VERSION 5.8 ;
BUSBITCHARS "[]" ;
DIVIDERCHAR "/" ;
UNITS
    DATABASE MICRONS 1000 ;
END UNITS

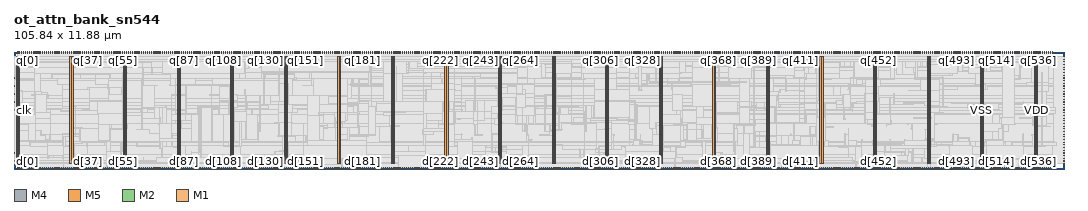
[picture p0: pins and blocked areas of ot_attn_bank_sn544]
MACRO ot_attn_bank_sn544
  FOREIGN ot_attn_bank_sn544 0 0 ;
  CLASS BLOCK ;
  SIZE 105.84 BY 11.88 ;
  PIN clk
    DIRECTION INPUT ;
    USE SIGNAL ;
    PORT
      LAYER M4 ;
        RECT  0 5.928 0.192 5.952 ;
    END
  END clk
  PIN d[0]
    DIRECTION INPUT ;
    USE SIGNAL ;
    PORT
      LAYER M5 ;
        RECT  0.384 0 0.408 0.192 ;
    END
  END d[0]
  PIN d[100]
    DIRECTION INPUT ;
    USE SIGNAL ;
    PORT
      LAYER M5 ;
        RECT  19.584 0 19.608 0.192 ;
    END
  END d[100]
  PIN d[101]
    DIRECTION INPUT ;
    USE SIGNAL ;
    PORT
      LAYER M5 ;
        RECT  19.776 0 19.8 0.192 ;
    END
  END d[101]
  PIN d[102]
    DIRECTION INPUT ;
    USE SIGNAL ;
    PORT
      LAYER M5 ;
        RECT  19.968 0 19.992 0.192 ;
    END
  END d[102]
  PIN d[103]
    DIRECTION INPUT ;
    USE SIGNAL ;
    PORT
      LAYER M5 ;
        RECT  20.16 0 20.184 0.192 ;
    END
  END d[103]
  PIN d[104]
    DIRECTION INPUT ;
    USE SIGNAL ;
    PORT
      LAYER M5 ;
        RECT  20.352 0 20.376 0.192 ;
    END
  END d[104]
  PIN d[105]
    DIRECTION INPUT ;
    USE SIGNAL ;
    PORT
      LAYER M5 ;
        RECT  20.544 0 20.568 0.192 ;
    END
  END d[105]
  PIN d[106]
    DIRECTION INPUT ;
    USE SIGNAL ;
    PORT
      LAYER M5 ;
        RECT  20.736 0 20.76 0.192 ;
    END
  END d[106]
  PIN d[107]
    DIRECTION INPUT ;
    USE SIGNAL ;
    PORT
      LAYER M5 ;
        RECT  20.928 0 20.952 0.192 ;
    END
  END d[107]
  PIN d[108]
    DIRECTION INPUT ;
    USE SIGNAL ;
    PORT
      LAYER M5 ;
        RECT  21.12 0 21.144 0.192 ;
    END
  END d[108]
  PIN d[109]
    DIRECTION INPUT ;
    USE SIGNAL ;
    PORT
      LAYER M5 ;
        RECT  21.312 0 21.336 0.192 ;
    END
  END d[109]
  PIN d[10]
    DIRECTION INPUT ;
    USE SIGNAL ;
    PORT
      LAYER M5 ;
        RECT  2.304 0 2.328 0.192 ;
    END
  END d[10]
  PIN d[110]
    DIRECTION INPUT ;
    USE SIGNAL ;
    PORT
      LAYER M5 ;
        RECT  21.504 0 21.528 0.192 ;
    END
  END d[110]
  PIN d[111]
    DIRECTION INPUT ;
    USE SIGNAL ;
    PORT
      LAYER M5 ;
        RECT  21.696 0 21.72 0.192 ;
    END
  END d[111]
  PIN d[112]
    DIRECTION INPUT ;
    USE SIGNAL ;
    PORT
      LAYER M5 ;
        RECT  21.888 0 21.912 0.192 ;
    END
  END d[112]
  PIN d[113]
    DIRECTION INPUT ;
    USE SIGNAL ;
    PORT
      LAYER M5 ;
        RECT  22.08 0 22.104 0.192 ;
    END
  END d[113]
  PIN d[114]
    DIRECTION INPUT ;
    USE SIGNAL ;
    PORT
      LAYER M5 ;
        RECT  22.272 0 22.296 0.192 ;
    END
  END d[114]
  PIN d[115]
    DIRECTION INPUT ;
    USE SIGNAL ;
    PORT
      LAYER M5 ;
        RECT  22.464 0 22.488 0.192 ;
    END
  END d[115]
  PIN d[116]
    DIRECTION INPUT ;
    USE SIGNAL ;
    PORT
      LAYER M5 ;
        RECT  22.656 0 22.68 0.192 ;
    END
  END d[116]
  PIN d[117]
    DIRECTION INPUT ;
    USE SIGNAL ;
    PORT
      LAYER M5 ;
        RECT  22.848 0 22.872 0.192 ;
    END
  END d[117]
  PIN d[118]
    DIRECTION INPUT ;
    USE SIGNAL ;
    PORT
      LAYER M5 ;
        RECT  23.04 0 23.064 0.192 ;
    END
  END d[118]
  PIN d[119]
    DIRECTION INPUT ;
    USE SIGNAL ;
    PORT
      LAYER M5 ;
        RECT  23.232 0 23.256 0.192 ;
    END
  END d[119]
  PIN d[11]
    DIRECTION INPUT ;
    USE SIGNAL ;
    PORT
      LAYER M5 ;
        RECT  2.496 0 2.52 0.192 ;
    END
  END d[11]
  PIN d[120]
    DIRECTION INPUT ;
    USE SIGNAL ;
    PORT
      LAYER M5 ;
        RECT  23.424 0 23.448 0.192 ;
    END
  END d[120]
  PIN d[121]
    DIRECTION INPUT ;
    USE SIGNAL ;
    PORT
      LAYER M5 ;
        RECT  23.616 0 23.64 0.192 ;
    END
  END d[121]
  PIN d[122]
    DIRECTION INPUT ;
    USE SIGNAL ;
    PORT
      LAYER M5 ;
        RECT  23.808 0 23.832 0.192 ;
    END
  END d[122]
  PIN d[123]
    DIRECTION INPUT ;
    USE SIGNAL ;
    PORT
      LAYER M5 ;
        RECT  24 0 24.024 0.192 ;
    END
  END d[123]
  PIN d[124]
    DIRECTION INPUT ;
    USE SIGNAL ;
    PORT
      LAYER M5 ;
        RECT  24.192 0 24.216 0.192 ;
    END
  END d[124]
  PIN d[125]
    DIRECTION INPUT ;
    USE SIGNAL ;
    PORT
      LAYER M5 ;
        RECT  24.384 0 24.408 0.192 ;
    END
  END d[125]
  PIN d[126]
    DIRECTION INPUT ;
    USE SIGNAL ;
    PORT
      LAYER M5 ;
        RECT  24.576 0 24.6 0.192 ;
    END
  END d[126]
  PIN d[127]
    DIRECTION INPUT ;
    USE SIGNAL ;
    PORT
      LAYER M5 ;
        RECT  24.768 0 24.792 0.192 ;
    END
  END d[127]
  PIN d[128]
    DIRECTION INPUT ;
    USE SIGNAL ;
    PORT
      LAYER M5 ;
        RECT  24.96 0 24.984 0.192 ;
    END
  END d[128]
  PIN d[129]
    DIRECTION INPUT ;
    USE SIGNAL ;
    PORT
      LAYER M5 ;
        RECT  25.152 0 25.176 0.192 ;
    END
  END d[129]
  PIN d[12]
    DIRECTION INPUT ;
    USE SIGNAL ;
    PORT
      LAYER M5 ;
        RECT  2.688 0 2.712 0.192 ;
    END
  END d[12]
  PIN d[130]
    DIRECTION INPUT ;
    USE SIGNAL ;
    PORT
      LAYER M5 ;
        RECT  25.344 0 25.368 0.192 ;
    END
  END d[130]
  PIN d[131]
    DIRECTION INPUT ;
    USE SIGNAL ;
    PORT
      LAYER M5 ;
        RECT  25.536 0 25.56 0.192 ;
    END
  END d[131]
  PIN d[132]
    DIRECTION INPUT ;
    USE SIGNAL ;
    PORT
      LAYER M5 ;
        RECT  25.728 0 25.752 0.192 ;
    END
  END d[132]
  PIN d[133]
    DIRECTION INPUT ;
    USE SIGNAL ;
    PORT
      LAYER M5 ;
        RECT  25.92 0 25.944 0.192 ;
    END
  END d[133]
  PIN d[134]
    DIRECTION INPUT ;
    USE SIGNAL ;
    PORT
      LAYER M5 ;
        RECT  26.112 0 26.136 0.192 ;
    END
  END d[134]
  PIN d[135]
    DIRECTION INPUT ;
    USE SIGNAL ;
    PORT
      LAYER M5 ;
        RECT  26.304 0 26.328 0.192 ;
    END
  END d[135]
  PIN d[136]
    DIRECTION INPUT ;
    USE SIGNAL ;
    PORT
      LAYER M5 ;
        RECT  26.496 0 26.52 0.192 ;
    END
  END d[136]
  PIN d[137]
    DIRECTION INPUT ;
    USE SIGNAL ;
    PORT
      LAYER M5 ;
        RECT  26.688 0 26.712 0.192 ;
    END
  END d[137]
  PIN d[138]
    DIRECTION INPUT ;
    USE SIGNAL ;
    PORT
      LAYER M5 ;
        RECT  26.88 0 26.904 0.192 ;
    END
  END d[138]
  PIN d[139]
    DIRECTION INPUT ;
    USE SIGNAL ;
    PORT
      LAYER M5 ;
        RECT  27.072 0 27.096 0.192 ;
    END
  END d[139]
  PIN d[13]
    DIRECTION INPUT ;
    USE SIGNAL ;
    PORT
      LAYER M5 ;
        RECT  2.88 0 2.904 0.192 ;
    END
  END d[13]
  PIN d[140]
    DIRECTION INPUT ;
    USE SIGNAL ;
    PORT
      LAYER M5 ;
        RECT  27.264 0 27.288 0.192 ;
    END
  END d[140]
  PIN d[141]
    DIRECTION INPUT ;
    USE SIGNAL ;
    PORT
      LAYER M5 ;
        RECT  27.456 0 27.48 0.192 ;
    END
  END d[141]
  PIN d[142]
    DIRECTION INPUT ;
    USE SIGNAL ;
    PORT
      LAYER M5 ;
        RECT  27.648 0 27.672 0.192 ;
    END
  END d[142]
  PIN d[143]
    DIRECTION INPUT ;
    USE SIGNAL ;
    PORT
      LAYER M5 ;
        RECT  27.84 0 27.864 0.192 ;
    END
  END d[143]
  PIN d[144]
    DIRECTION INPUT ;
    USE SIGNAL ;
    PORT
      LAYER M5 ;
        RECT  28.032 0 28.056 0.192 ;
    END
  END d[144]
  PIN d[145]
    DIRECTION INPUT ;
    USE SIGNAL ;
    PORT
      LAYER M5 ;
        RECT  28.224 0 28.248 0.192 ;
    END
  END d[145]
  PIN d[146]
    DIRECTION INPUT ;
    USE SIGNAL ;
    PORT
      LAYER M5 ;
        RECT  28.416 0 28.44 0.192 ;
    END
  END d[146]
  PIN d[147]
    DIRECTION INPUT ;
    USE SIGNAL ;
    PORT
      LAYER M5 ;
        RECT  28.608 0 28.632 0.192 ;
    END
  END d[147]
  PIN d[148]
    DIRECTION INPUT ;
    USE SIGNAL ;
    PORT
      LAYER M5 ;
        RECT  28.8 0 28.824 0.192 ;
    END
  END d[148]
  PIN d[149]
    DIRECTION INPUT ;
    USE SIGNAL ;
    PORT
      LAYER M5 ;
        RECT  28.992 0 29.016 0.192 ;
    END
  END d[149]
  PIN d[14]
    DIRECTION INPUT ;
    USE SIGNAL ;
    PORT
      LAYER M5 ;
        RECT  3.072 0 3.096 0.192 ;
    END
  END d[14]
  PIN d[150]
    DIRECTION INPUT ;
    USE SIGNAL ;
    PORT
      LAYER M5 ;
        RECT  29.184 0 29.208 0.192 ;
    END
  END d[150]
  PIN d[151]
    DIRECTION INPUT ;
    USE SIGNAL ;
    PORT
      LAYER M5 ;
        RECT  29.376 0 29.4 0.192 ;
    END
  END d[151]
  PIN d[152]
    DIRECTION INPUT ;
    USE SIGNAL ;
    PORT
      LAYER M5 ;
        RECT  29.568 0 29.592 0.192 ;
    END
  END d[152]
  PIN d[153]
    DIRECTION INPUT ;
    USE SIGNAL ;
    PORT
      LAYER M5 ;
        RECT  29.76 0 29.784 0.192 ;
    END
  END d[153]
  PIN d[154]
    DIRECTION INPUT ;
    USE SIGNAL ;
    PORT
      LAYER M5 ;
        RECT  29.952 0 29.976 0.192 ;
    END
  END d[154]
  PIN d[155]
    DIRECTION INPUT ;
    USE SIGNAL ;
    PORT
      LAYER M5 ;
        RECT  30.144 0 30.168 0.192 ;
    END
  END d[155]
  PIN d[156]
    DIRECTION INPUT ;
    USE SIGNAL ;
    PORT
      LAYER M5 ;
        RECT  30.336 0 30.36 0.192 ;
    END
  END d[156]
  PIN d[157]
    DIRECTION INPUT ;
    USE SIGNAL ;
    PORT
      LAYER M5 ;
        RECT  30.528 0 30.552 0.192 ;
    END
  END d[157]
  PIN d[158]
    DIRECTION INPUT ;
    USE SIGNAL ;
    PORT
      LAYER M5 ;
        RECT  30.72 0 30.744 0.192 ;
    END
  END d[158]
  PIN d[159]
    DIRECTION INPUT ;
    USE SIGNAL ;
    PORT
      LAYER M5 ;
        RECT  30.912 0 30.936 0.192 ;
    END
  END d[159]
  PIN d[15]
    DIRECTION INPUT ;
    USE SIGNAL ;
    PORT
      LAYER M5 ;
        RECT  3.264 0 3.288 0.192 ;
    END
  END d[15]
  PIN d[160]
    DIRECTION INPUT ;
    USE SIGNAL ;
    PORT
      LAYER M5 ;
        RECT  31.104 0 31.128 0.192 ;
    END
  END d[160]
  PIN d[161]
    DIRECTION INPUT ;
    USE SIGNAL ;
    PORT
      LAYER M5 ;
        RECT  31.296 0 31.32 0.192 ;
    END
  END d[161]
  PIN d[162]
    DIRECTION INPUT ;
    USE SIGNAL ;
    PORT
      LAYER M5 ;
        RECT  31.488 0 31.512 0.192 ;
    END
  END d[162]
  PIN d[163]
    DIRECTION INPUT ;
    USE SIGNAL ;
    PORT
      LAYER M5 ;
        RECT  31.68 0 31.704 0.192 ;
    END
  END d[163]
  PIN d[164]
    DIRECTION INPUT ;
    USE SIGNAL ;
    PORT
      LAYER M5 ;
        RECT  31.872 0 31.896 0.192 ;
    END
  END d[164]
  PIN d[165]
    DIRECTION INPUT ;
    USE SIGNAL ;
    PORT
      LAYER M5 ;
        RECT  32.064 0 32.088 0.192 ;
    END
  END d[165]
  PIN d[166]
    DIRECTION INPUT ;
    USE SIGNAL ;
    PORT
      LAYER M5 ;
        RECT  32.256 0 32.28 0.192 ;
    END
  END d[166]
  PIN d[167]
    DIRECTION INPUT ;
    USE SIGNAL ;
    PORT
      LAYER M5 ;
        RECT  32.448 0 32.472 0.192 ;
    END
  END d[167]
  PIN d[168]
    DIRECTION INPUT ;
    USE SIGNAL ;
    PORT
      LAYER M5 ;
        RECT  32.64 0 32.664 0.192 ;
    END
  END d[168]
  PIN d[169]
    DIRECTION INPUT ;
    USE SIGNAL ;
    PORT
      LAYER M5 ;
        RECT  32.832 0 32.856 0.192 ;
    END
  END d[169]
  PIN d[16]
    DIRECTION INPUT ;
    USE SIGNAL ;
    PORT
      LAYER M5 ;
        RECT  3.456 0 3.48 0.192 ;
    END
  END d[16]
  PIN d[170]
    DIRECTION INPUT ;
    USE SIGNAL ;
    PORT
      LAYER M5 ;
        RECT  33.024 0 33.048 0.192 ;
    END
  END d[170]
  PIN d[171]
    DIRECTION INPUT ;
    USE SIGNAL ;
    PORT
      LAYER M5 ;
        RECT  33.216 0 33.24 0.192 ;
    END
  END d[171]
  PIN d[172]
    DIRECTION INPUT ;
    USE SIGNAL ;
    PORT
      LAYER M5 ;
        RECT  33.408 0 33.432 0.192 ;
    END
  END d[172]
  PIN d[173]
    DIRECTION INPUT ;
    USE SIGNAL ;
    PORT
      LAYER M5 ;
        RECT  33.6 0 33.624 0.192 ;
    END
  END d[173]
  PIN d[174]
    DIRECTION INPUT ;
    USE SIGNAL ;
    PORT
      LAYER M5 ;
        RECT  33.792 0 33.816 0.192 ;
    END
  END d[174]
  PIN d[175]
    DIRECTION INPUT ;
    USE SIGNAL ;
    PORT
      LAYER M5 ;
        RECT  33.984 0 34.008 0.192 ;
    END
  END d[175]
  PIN d[176]
    DIRECTION INPUT ;
    USE SIGNAL ;
    PORT
      LAYER M5 ;
        RECT  34.176 0 34.2 0.192 ;
    END
  END d[176]
  PIN d[177]
    DIRECTION INPUT ;
    USE SIGNAL ;
    PORT
      LAYER M5 ;
        RECT  34.368 0 34.392 0.192 ;
    END
  END d[177]
  PIN d[178]
    DIRECTION INPUT ;
    USE SIGNAL ;
    PORT
      LAYER M5 ;
        RECT  34.56 0 34.584 0.192 ;
    END
  END d[178]
  PIN d[179]
    DIRECTION INPUT ;
    USE SIGNAL ;
    PORT
      LAYER M5 ;
        RECT  34.752 0 34.776 0.192 ;
    END
  END d[179]
  PIN d[17]
    DIRECTION INPUT ;
    USE SIGNAL ;
    PORT
      LAYER M5 ;
        RECT  3.648 0 3.672 0.192 ;
    END
  END d[17]
  PIN d[180]
    DIRECTION INPUT ;
    USE SIGNAL ;
    PORT
      LAYER M5 ;
        RECT  34.944 0 34.968 0.192 ;
    END
  END d[180]
  PIN d[181]
    DIRECTION INPUT ;
    USE SIGNAL ;
    PORT
      LAYER M5 ;
        RECT  35.136 0 35.16 0.192 ;
    END
  END d[181]
  PIN d[182]
    DIRECTION INPUT ;
    USE SIGNAL ;
    PORT
      LAYER M5 ;
        RECT  35.328 0 35.352 0.192 ;
    END
  END d[182]
  PIN d[183]
    DIRECTION INPUT ;
    USE SIGNAL ;
    PORT
      LAYER M5 ;
        RECT  35.52 0 35.544 0.192 ;
    END
  END d[183]
  PIN d[184]
    DIRECTION INPUT ;
    USE SIGNAL ;
    PORT
      LAYER M5 ;
        RECT  35.712 0 35.736 0.192 ;
    END
  END d[184]
  PIN d[185]
    DIRECTION INPUT ;
    USE SIGNAL ;
    PORT
      LAYER M5 ;
        RECT  35.904 0 35.928 0.192 ;
    END
  END d[185]
  PIN d[186]
    DIRECTION INPUT ;
    USE SIGNAL ;
    PORT
      LAYER M5 ;
        RECT  36.096 0 36.12 0.192 ;
    END
  END d[186]
  PIN d[187]
    DIRECTION INPUT ;
    USE SIGNAL ;
    PORT
      LAYER M5 ;
        RECT  36.288 0 36.312 0.192 ;
    END
  END d[187]
  PIN d[188]
    DIRECTION INPUT ;
    USE SIGNAL ;
    PORT
      LAYER M5 ;
        RECT  36.48 0 36.504 0.192 ;
    END
  END d[188]
  PIN d[189]
    DIRECTION INPUT ;
    USE SIGNAL ;
    PORT
      LAYER M5 ;
        RECT  36.672 0 36.696 0.192 ;
    END
  END d[189]
  PIN d[18]
    DIRECTION INPUT ;
    USE SIGNAL ;
    PORT
      LAYER M5 ;
        RECT  3.84 0 3.864 0.192 ;
    END
  END d[18]
  PIN d[190]
    DIRECTION INPUT ;
    USE SIGNAL ;
    PORT
      LAYER M5 ;
        RECT  36.864 0 36.888 0.192 ;
    END
  END d[190]
  PIN d[191]
    DIRECTION INPUT ;
    USE SIGNAL ;
    PORT
      LAYER M5 ;
        RECT  37.056 0 37.08 0.192 ;
    END
  END d[191]
  PIN d[192]
    DIRECTION INPUT ;
    USE SIGNAL ;
    PORT
      LAYER M5 ;
        RECT  37.248 0 37.272 0.192 ;
    END
  END d[192]
  PIN d[193]
    DIRECTION INPUT ;
    USE SIGNAL ;
    PORT
      LAYER M5 ;
        RECT  37.44 0 37.464 0.192 ;
    END
  END d[193]
  PIN d[194]
    DIRECTION INPUT ;
    USE SIGNAL ;
    PORT
      LAYER M5 ;
        RECT  37.632 0 37.656 0.192 ;
    END
  END d[194]
  PIN d[195]
    DIRECTION INPUT ;
    USE SIGNAL ;
    PORT
      LAYER M5 ;
        RECT  37.824 0 37.848 0.192 ;
    END
  END d[195]
  PIN d[196]
    DIRECTION INPUT ;
    USE SIGNAL ;
    PORT
      LAYER M5 ;
        RECT  38.016 0 38.04 0.192 ;
    END
  END d[196]
  PIN d[197]
    DIRECTION INPUT ;
    USE SIGNAL ;
    PORT
      LAYER M5 ;
        RECT  38.208 0 38.232 0.192 ;
    END
  END d[197]
  PIN d[198]
    DIRECTION INPUT ;
    USE SIGNAL ;
    PORT
      LAYER M5 ;
        RECT  38.4 0 38.424 0.192 ;
    END
  END d[198]
  PIN d[199]
    DIRECTION INPUT ;
    USE SIGNAL ;
    PORT
      LAYER M5 ;
        RECT  38.592 0 38.616 0.192 ;
    END
  END d[199]
  PIN d[19]
    DIRECTION INPUT ;
    USE SIGNAL ;
    PORT
      LAYER M5 ;
        RECT  4.032 0 4.056 0.192 ;
    END
  END d[19]
  PIN d[1]
    DIRECTION INPUT ;
    USE SIGNAL ;
    PORT
      LAYER M5 ;
        RECT  0.576 0 0.6 0.192 ;
    END
  END d[1]
  PIN d[200]
    DIRECTION INPUT ;
    USE SIGNAL ;
    PORT
      LAYER M5 ;
        RECT  38.784 0 38.808 0.192 ;
    END
  END d[200]
  PIN d[201]
    DIRECTION INPUT ;
    USE SIGNAL ;
    PORT
      LAYER M5 ;
        RECT  38.976 0 39 0.192 ;
    END
  END d[201]
  PIN d[202]
    DIRECTION INPUT ;
    USE SIGNAL ;
    PORT
      LAYER M5 ;
        RECT  39.168 0 39.192 0.192 ;
    END
  END d[202]
  PIN d[203]
    DIRECTION INPUT ;
    USE SIGNAL ;
    PORT
      LAYER M5 ;
        RECT  39.36 0 39.384 0.192 ;
    END
  END d[203]
  PIN d[204]
    DIRECTION INPUT ;
    USE SIGNAL ;
    PORT
      LAYER M5 ;
        RECT  39.552 0 39.576 0.192 ;
    END
  END d[204]
  PIN d[205]
    DIRECTION INPUT ;
    USE SIGNAL ;
    PORT
      LAYER M5 ;
        RECT  39.744 0 39.768 0.192 ;
    END
  END d[205]
  PIN d[206]
    DIRECTION INPUT ;
    USE SIGNAL ;
    PORT
      LAYER M5 ;
        RECT  39.936 0 39.96 0.192 ;
    END
  END d[206]
  PIN d[207]
    DIRECTION INPUT ;
    USE SIGNAL ;
    PORT
      LAYER M5 ;
        RECT  40.128 0 40.152 0.192 ;
    END
  END d[207]
  PIN d[208]
    DIRECTION INPUT ;
    USE SIGNAL ;
    PORT
      LAYER M5 ;
        RECT  40.32 0 40.344 0.192 ;
    END
  END d[208]
  PIN d[209]
    DIRECTION INPUT ;
    USE SIGNAL ;
    PORT
      LAYER M5 ;
        RECT  40.512 0 40.536 0.192 ;
    END
  END d[209]
  PIN d[20]
    DIRECTION INPUT ;
    USE SIGNAL ;
    PORT
      LAYER M5 ;
        RECT  4.224 0 4.248 0.192 ;
    END
  END d[20]
  PIN d[210]
    DIRECTION INPUT ;
    USE SIGNAL ;
    PORT
      LAYER M5 ;
        RECT  40.704 0 40.728 0.192 ;
    END
  END d[210]
  PIN d[211]
    DIRECTION INPUT ;
    USE SIGNAL ;
    PORT
      LAYER M5 ;
        RECT  40.896 0 40.92 0.192 ;
    END
  END d[211]
  PIN d[212]
    DIRECTION INPUT ;
    USE SIGNAL ;
    PORT
      LAYER M5 ;
        RECT  41.088 0 41.112 0.192 ;
    END
  END d[212]
  PIN d[213]
    DIRECTION INPUT ;
    USE SIGNAL ;
    PORT
      LAYER M5 ;
        RECT  41.28 0 41.304 0.192 ;
    END
  END d[213]
  PIN d[214]
    DIRECTION INPUT ;
    USE SIGNAL ;
    PORT
      LAYER M5 ;
        RECT  41.472 0 41.496 0.192 ;
    END
  END d[214]
  PIN d[215]
    DIRECTION INPUT ;
    USE SIGNAL ;
    PORT
      LAYER M5 ;
        RECT  41.664 0 41.688 0.192 ;
    END
  END d[215]
  PIN d[216]
    DIRECTION INPUT ;
    USE SIGNAL ;
    PORT
      LAYER M5 ;
        RECT  41.856 0 41.88 0.192 ;
    END
  END d[216]
  PIN d[217]
    DIRECTION INPUT ;
    USE SIGNAL ;
    PORT
      LAYER M5 ;
        RECT  42.048 0 42.072 0.192 ;
    END
  END d[217]
  PIN d[218]
    DIRECTION INPUT ;
    USE SIGNAL ;
    PORT
      LAYER M5 ;
        RECT  42.24 0 42.264 0.192 ;
    END
  END d[218]
  PIN d[219]
    DIRECTION INPUT ;
    USE SIGNAL ;
    PORT
      LAYER M5 ;
        RECT  42.432 0 42.456 0.192 ;
    END
  END d[219]
  PIN d[21]
    DIRECTION INPUT ;
    USE SIGNAL ;
    PORT
      LAYER M5 ;
        RECT  4.416 0 4.44 0.192 ;
    END
  END d[21]
  PIN d[220]
    DIRECTION INPUT ;
    USE SIGNAL ;
    PORT
      LAYER M5 ;
        RECT  42.624 0 42.648 0.192 ;
    END
  END d[220]
  PIN d[221]
    DIRECTION INPUT ;
    USE SIGNAL ;
    PORT
      LAYER M5 ;
        RECT  42.816 0 42.84 0.192 ;
    END
  END d[221]
  PIN d[222]
    DIRECTION INPUT ;
    USE SIGNAL ;
    PORT
      LAYER M5 ;
        RECT  43.008 0 43.032 0.192 ;
    END
  END d[222]
  PIN d[223]
    DIRECTION INPUT ;
    USE SIGNAL ;
    PORT
      LAYER M5 ;
        RECT  43.2 0 43.224 0.192 ;
    END
  END d[223]
  PIN d[224]
    DIRECTION INPUT ;
    USE SIGNAL ;
    PORT
      LAYER M5 ;
        RECT  43.392 0 43.416 0.192 ;
    END
  END d[224]
  PIN d[225]
    DIRECTION INPUT ;
    USE SIGNAL ;
    PORT
      LAYER M5 ;
        RECT  43.584 0 43.608 0.192 ;
    END
  END d[225]
  PIN d[226]
    DIRECTION INPUT ;
    USE SIGNAL ;
    PORT
      LAYER M5 ;
        RECT  43.776 0 43.8 0.192 ;
    END
  END d[226]
  PIN d[227]
    DIRECTION INPUT ;
    USE SIGNAL ;
    PORT
      LAYER M5 ;
        RECT  43.968 0 43.992 0.192 ;
    END
  END d[227]
  PIN d[228]
    DIRECTION INPUT ;
    USE SIGNAL ;
    PORT
      LAYER M5 ;
        RECT  44.16 0 44.184 0.192 ;
    END
  END d[228]
  PIN d[229]
    DIRECTION INPUT ;
    USE SIGNAL ;
    PORT
      LAYER M5 ;
        RECT  44.352 0 44.376 0.192 ;
    END
  END d[229]
  PIN d[22]
    DIRECTION INPUT ;
    USE SIGNAL ;
    PORT
      LAYER M5 ;
        RECT  4.608 0 4.632 0.192 ;
    END
  END d[22]
  PIN d[230]
    DIRECTION INPUT ;
    USE SIGNAL ;
    PORT
      LAYER M5 ;
        RECT  44.544 0 44.568 0.192 ;
    END
  END d[230]
  PIN d[231]
    DIRECTION INPUT ;
    USE SIGNAL ;
    PORT
      LAYER M5 ;
        RECT  44.736 0 44.76 0.192 ;
    END
  END d[231]
  PIN d[232]
    DIRECTION INPUT ;
    USE SIGNAL ;
    PORT
      LAYER M5 ;
        RECT  44.928 0 44.952 0.192 ;
    END
  END d[232]
  PIN d[233]
    DIRECTION INPUT ;
    USE SIGNAL ;
    PORT
      LAYER M5 ;
        RECT  45.12 0 45.144 0.192 ;
    END
  END d[233]
  PIN d[234]
    DIRECTION INPUT ;
    USE SIGNAL ;
    PORT
      LAYER M5 ;
        RECT  45.312 0 45.336 0.192 ;
    END
  END d[234]
  PIN d[235]
    DIRECTION INPUT ;
    USE SIGNAL ;
    PORT
      LAYER M5 ;
        RECT  45.504 0 45.528 0.192 ;
    END
  END d[235]
  PIN d[236]
    DIRECTION INPUT ;
    USE SIGNAL ;
    PORT
      LAYER M5 ;
        RECT  45.696 0 45.72 0.192 ;
    END
  END d[236]
  PIN d[237]
    DIRECTION INPUT ;
    USE SIGNAL ;
    PORT
      LAYER M5 ;
        RECT  45.888 0 45.912 0.192 ;
    END
  END d[237]
  PIN d[238]
    DIRECTION INPUT ;
    USE SIGNAL ;
    PORT
      LAYER M5 ;
        RECT  46.08 0 46.104 0.192 ;
    END
  END d[238]
  PIN d[239]
    DIRECTION INPUT ;
    USE SIGNAL ;
    PORT
      LAYER M5 ;
        RECT  46.272 0 46.296 0.192 ;
    END
  END d[239]
  PIN d[23]
    DIRECTION INPUT ;
    USE SIGNAL ;
    PORT
      LAYER M5 ;
        RECT  4.8 0 4.824 0.192 ;
    END
  END d[23]
  PIN d[240]
    DIRECTION INPUT ;
    USE SIGNAL ;
    PORT
      LAYER M5 ;
        RECT  46.464 0 46.488 0.192 ;
    END
  END d[240]
  PIN d[241]
    DIRECTION INPUT ;
    USE SIGNAL ;
    PORT
      LAYER M5 ;
        RECT  46.656 0 46.68 0.192 ;
    END
  END d[241]
  PIN d[242]
    DIRECTION INPUT ;
    USE SIGNAL ;
    PORT
      LAYER M5 ;
        RECT  46.848 0 46.872 0.192 ;
    END
  END d[242]
  PIN d[243]
    DIRECTION INPUT ;
    USE SIGNAL ;
    PORT
      LAYER M5 ;
        RECT  47.04 0 47.064 0.192 ;
    END
  END d[243]
  PIN d[244]
    DIRECTION INPUT ;
    USE SIGNAL ;
    PORT
      LAYER M5 ;
        RECT  47.232 0 47.256 0.192 ;
    END
  END d[244]
  PIN d[245]
    DIRECTION INPUT ;
    USE SIGNAL ;
    PORT
      LAYER M5 ;
        RECT  47.424 0 47.448 0.192 ;
    END
  END d[245]
  PIN d[246]
    DIRECTION INPUT ;
    USE SIGNAL ;
    PORT
      LAYER M5 ;
        RECT  47.616 0 47.64 0.192 ;
    END
  END d[246]
  PIN d[247]
    DIRECTION INPUT ;
    USE SIGNAL ;
    PORT
      LAYER M5 ;
        RECT  47.808 0 47.832 0.192 ;
    END
  END d[247]
  PIN d[248]
    DIRECTION INPUT ;
    USE SIGNAL ;
    PORT
      LAYER M5 ;
        RECT  48 0 48.024 0.192 ;
    END
  END d[248]
  PIN d[249]
    DIRECTION INPUT ;
    USE SIGNAL ;
    PORT
      LAYER M5 ;
        RECT  48.192 0 48.216 0.192 ;
    END
  END d[249]
  PIN d[24]
    DIRECTION INPUT ;
    USE SIGNAL ;
    PORT
      LAYER M5 ;
        RECT  4.992 0 5.016 0.192 ;
    END
  END d[24]
  PIN d[250]
    DIRECTION INPUT ;
    USE SIGNAL ;
    PORT
      LAYER M5 ;
        RECT  48.384 0 48.408 0.192 ;
    END
  END d[250]
  PIN d[251]
    DIRECTION INPUT ;
    USE SIGNAL ;
    PORT
      LAYER M5 ;
        RECT  48.576 0 48.6 0.192 ;
    END
  END d[251]
  PIN d[252]
    DIRECTION INPUT ;
    USE SIGNAL ;
    PORT
      LAYER M5 ;
        RECT  48.768 0 48.792 0.192 ;
    END
  END d[252]
  PIN d[253]
    DIRECTION INPUT ;
    USE SIGNAL ;
    PORT
      LAYER M5 ;
        RECT  48.96 0 48.984 0.192 ;
    END
  END d[253]
  PIN d[254]
    DIRECTION INPUT ;
    USE SIGNAL ;
    PORT
      LAYER M5 ;
        RECT  49.152 0 49.176 0.192 ;
    END
  END d[254]
  PIN d[255]
    DIRECTION INPUT ;
    USE SIGNAL ;
    PORT
      LAYER M5 ;
        RECT  49.344 0 49.368 0.192 ;
    END
  END d[255]
  PIN d[256]
    DIRECTION INPUT ;
    USE SIGNAL ;
    PORT
      LAYER M5 ;
        RECT  49.536 0 49.56 0.192 ;
    END
  END d[256]
  PIN d[257]
    DIRECTION INPUT ;
    USE SIGNAL ;
    PORT
      LAYER M5 ;
        RECT  49.728 0 49.752 0.192 ;
    END
  END d[257]
  PIN d[258]
    DIRECTION INPUT ;
    USE SIGNAL ;
    PORT
      LAYER M5 ;
        RECT  49.92 0 49.944 0.192 ;
    END
  END d[258]
  PIN d[259]
    DIRECTION INPUT ;
    USE SIGNAL ;
    PORT
      LAYER M5 ;
        RECT  50.112 0 50.136 0.192 ;
    END
  END d[259]
  PIN d[25]
    DIRECTION INPUT ;
    USE SIGNAL ;
    PORT
      LAYER M5 ;
        RECT  5.184 0 5.208 0.192 ;
    END
  END d[25]
  PIN d[260]
    DIRECTION INPUT ;
    USE SIGNAL ;
    PORT
      LAYER M5 ;
        RECT  50.304 0 50.328 0.192 ;
    END
  END d[260]
  PIN d[261]
    DIRECTION INPUT ;
    USE SIGNAL ;
    PORT
      LAYER M5 ;
        RECT  50.496 0 50.52 0.192 ;
    END
  END d[261]
  PIN d[262]
    DIRECTION INPUT ;
    USE SIGNAL ;
    PORT
      LAYER M5 ;
        RECT  50.688 0 50.712 0.192 ;
    END
  END d[262]
  PIN d[263]
    DIRECTION INPUT ;
    USE SIGNAL ;
    PORT
      LAYER M5 ;
        RECT  50.88 0 50.904 0.192 ;
    END
  END d[263]
  PIN d[264]
    DIRECTION INPUT ;
    USE SIGNAL ;
    PORT
      LAYER M5 ;
        RECT  51.072 0 51.096 0.192 ;
    END
  END d[264]
  PIN d[265]
    DIRECTION INPUT ;
    USE SIGNAL ;
    PORT
      LAYER M5 ;
        RECT  51.264 0 51.288 0.192 ;
    END
  END d[265]
  PIN d[266]
    DIRECTION INPUT ;
    USE SIGNAL ;
    PORT
      LAYER M5 ;
        RECT  51.456 0 51.48 0.192 ;
    END
  END d[266]
  PIN d[267]
    DIRECTION INPUT ;
    USE SIGNAL ;
    PORT
      LAYER M5 ;
        RECT  51.648 0 51.672 0.192 ;
    END
  END d[267]
  PIN d[268]
    DIRECTION INPUT ;
    USE SIGNAL ;
    PORT
      LAYER M5 ;
        RECT  51.84 0 51.864 0.192 ;
    END
  END d[268]
  PIN d[269]
    DIRECTION INPUT ;
    USE SIGNAL ;
    PORT
      LAYER M5 ;
        RECT  52.032 0 52.056 0.192 ;
    END
  END d[269]
  PIN d[26]
    DIRECTION INPUT ;
    USE SIGNAL ;
    PORT
      LAYER M5 ;
        RECT  5.376 0 5.4 0.192 ;
    END
  END d[26]
  PIN d[270]
    DIRECTION INPUT ;
    USE SIGNAL ;
    PORT
      LAYER M5 ;
        RECT  52.224 0 52.248 0.192 ;
    END
  END d[270]
  PIN d[271]
    DIRECTION INPUT ;
    USE SIGNAL ;
    PORT
      LAYER M5 ;
        RECT  52.416 0 52.44 0.192 ;
    END
  END d[271]
  PIN d[272]
    DIRECTION INPUT ;
    USE SIGNAL ;
    PORT
      LAYER M5 ;
        RECT  52.608 0 52.632 0.192 ;
    END
  END d[272]
  PIN d[273]
    DIRECTION INPUT ;
    USE SIGNAL ;
    PORT
      LAYER M5 ;
        RECT  52.8 0 52.824 0.192 ;
    END
  END d[273]
  PIN d[274]
    DIRECTION INPUT ;
    USE SIGNAL ;
    PORT
      LAYER M5 ;
        RECT  52.992 0 53.016 0.192 ;
    END
  END d[274]
  PIN d[275]
    DIRECTION INPUT ;
    USE SIGNAL ;
    PORT
      LAYER M5 ;
        RECT  53.184 0 53.208 0.192 ;
    END
  END d[275]
  PIN d[276]
    DIRECTION INPUT ;
    USE SIGNAL ;
    PORT
      LAYER M5 ;
        RECT  53.376 0 53.4 0.192 ;
    END
  END d[276]
  PIN d[277]
    DIRECTION INPUT ;
    USE SIGNAL ;
    PORT
      LAYER M5 ;
        RECT  53.568 0 53.592 0.192 ;
    END
  END d[277]
  PIN d[278]
    DIRECTION INPUT ;
    USE SIGNAL ;
    PORT
      LAYER M5 ;
        RECT  53.76 0 53.784 0.192 ;
    END
  END d[278]
  PIN d[279]
    DIRECTION INPUT ;
    USE SIGNAL ;
    PORT
      LAYER M5 ;
        RECT  53.952 0 53.976 0.192 ;
    END
  END d[279]
  PIN d[27]
    DIRECTION INPUT ;
    USE SIGNAL ;
    PORT
      LAYER M5 ;
        RECT  5.568 0 5.592 0.192 ;
    END
  END d[27]
  PIN d[280]
    DIRECTION INPUT ;
    USE SIGNAL ;
    PORT
      LAYER M5 ;
        RECT  54.144 0 54.168 0.192 ;
    END
  END d[280]
  PIN d[281]
    DIRECTION INPUT ;
    USE SIGNAL ;
    PORT
      LAYER M5 ;
        RECT  54.336 0 54.36 0.192 ;
    END
  END d[281]
  PIN d[282]
    DIRECTION INPUT ;
    USE SIGNAL ;
    PORT
      LAYER M5 ;
        RECT  54.528 0 54.552 0.192 ;
    END
  END d[282]
  PIN d[283]
    DIRECTION INPUT ;
    USE SIGNAL ;
    PORT
      LAYER M5 ;
        RECT  54.72 0 54.744 0.192 ;
    END
  END d[283]
  PIN d[284]
    DIRECTION INPUT ;
    USE SIGNAL ;
    PORT
      LAYER M5 ;
        RECT  54.912 0 54.936 0.192 ;
    END
  END d[284]
  PIN d[285]
    DIRECTION INPUT ;
    USE SIGNAL ;
    PORT
      LAYER M5 ;
        RECT  55.104 0 55.128 0.192 ;
    END
  END d[285]
  PIN d[286]
    DIRECTION INPUT ;
    USE SIGNAL ;
    PORT
      LAYER M5 ;
        RECT  55.296 0 55.32 0.192 ;
    END
  END d[286]
  PIN d[287]
    DIRECTION INPUT ;
    USE SIGNAL ;
    PORT
      LAYER M5 ;
        RECT  55.488 0 55.512 0.192 ;
    END
  END d[287]
  PIN d[288]
    DIRECTION INPUT ;
    USE SIGNAL ;
    PORT
      LAYER M5 ;
        RECT  55.68 0 55.704 0.192 ;
    END
  END d[288]
  PIN d[289]
    DIRECTION INPUT ;
    USE SIGNAL ;
    PORT
      LAYER M5 ;
        RECT  55.872 0 55.896 0.192 ;
    END
  END d[289]
  PIN d[28]
    DIRECTION INPUT ;
    USE SIGNAL ;
    PORT
      LAYER M5 ;
        RECT  5.76 0 5.784 0.192 ;
    END
  END d[28]
  PIN d[290]
    DIRECTION INPUT ;
    USE SIGNAL ;
    PORT
      LAYER M5 ;
        RECT  56.064 0 56.088 0.192 ;
    END
  END d[290]
  PIN d[291]
    DIRECTION INPUT ;
    USE SIGNAL ;
    PORT
      LAYER M5 ;
        RECT  56.256 0 56.28 0.192 ;
    END
  END d[291]
  PIN d[292]
    DIRECTION INPUT ;
    USE SIGNAL ;
    PORT
      LAYER M5 ;
        RECT  56.448 0 56.472 0.192 ;
    END
  END d[292]
  PIN d[293]
    DIRECTION INPUT ;
    USE SIGNAL ;
    PORT
      LAYER M5 ;
        RECT  56.64 0 56.664 0.192 ;
    END
  END d[293]
  PIN d[294]
    DIRECTION INPUT ;
    USE SIGNAL ;
    PORT
      LAYER M5 ;
        RECT  56.832 0 56.856 0.192 ;
    END
  END d[294]
  PIN d[295]
    DIRECTION INPUT ;
    USE SIGNAL ;
    PORT
      LAYER M5 ;
        RECT  57.024 0 57.048 0.192 ;
    END
  END d[295]
  PIN d[296]
    DIRECTION INPUT ;
    USE SIGNAL ;
    PORT
      LAYER M5 ;
        RECT  57.216 0 57.24 0.192 ;
    END
  END d[296]
  PIN d[297]
    DIRECTION INPUT ;
    USE SIGNAL ;
    PORT
      LAYER M5 ;
        RECT  57.408 0 57.432 0.192 ;
    END
  END d[297]
  PIN d[298]
    DIRECTION INPUT ;
    USE SIGNAL ;
    PORT
      LAYER M5 ;
        RECT  57.6 0 57.624 0.192 ;
    END
  END d[298]
  PIN d[299]
    DIRECTION INPUT ;
    USE SIGNAL ;
    PORT
      LAYER M5 ;
        RECT  57.792 0 57.816 0.192 ;
    END
  END d[299]
  PIN d[29]
    DIRECTION INPUT ;
    USE SIGNAL ;
    PORT
      LAYER M5 ;
        RECT  5.952 0 5.976 0.192 ;
    END
  END d[29]
  PIN d[2]
    DIRECTION INPUT ;
    USE SIGNAL ;
    PORT
      LAYER M5 ;
        RECT  0.768 0 0.792 0.192 ;
    END
  END d[2]
  PIN d[300]
    DIRECTION INPUT ;
    USE SIGNAL ;
    PORT
      LAYER M5 ;
        RECT  57.984 0 58.008 0.192 ;
    END
  END d[300]
  PIN d[301]
    DIRECTION INPUT ;
    USE SIGNAL ;
    PORT
      LAYER M5 ;
        RECT  58.176 0 58.2 0.192 ;
    END
  END d[301]
  PIN d[302]
    DIRECTION INPUT ;
    USE SIGNAL ;
    PORT
      LAYER M5 ;
        RECT  58.368 0 58.392 0.192 ;
    END
  END d[302]
  PIN d[303]
    DIRECTION INPUT ;
    USE SIGNAL ;
    PORT
      LAYER M5 ;
        RECT  58.56 0 58.584 0.192 ;
    END
  END d[303]
  PIN d[304]
    DIRECTION INPUT ;
    USE SIGNAL ;
    PORT
      LAYER M5 ;
        RECT  58.752 0 58.776 0.192 ;
    END
  END d[304]
  PIN d[305]
    DIRECTION INPUT ;
    USE SIGNAL ;
    PORT
      LAYER M5 ;
        RECT  58.944 0 58.968 0.192 ;
    END
  END d[305]
  PIN d[306]
    DIRECTION INPUT ;
    USE SIGNAL ;
    PORT
      LAYER M5 ;
        RECT  59.136 0 59.16 0.192 ;
    END
  END d[306]
  PIN d[307]
    DIRECTION INPUT ;
    USE SIGNAL ;
    PORT
      LAYER M5 ;
        RECT  59.328 0 59.352 0.192 ;
    END
  END d[307]
  PIN d[308]
    DIRECTION INPUT ;
    USE SIGNAL ;
    PORT
      LAYER M5 ;
        RECT  59.52 0 59.544 0.192 ;
    END
  END d[308]
  PIN d[309]
    DIRECTION INPUT ;
    USE SIGNAL ;
    PORT
      LAYER M5 ;
        RECT  59.712 0 59.736 0.192 ;
    END
  END d[309]
  PIN d[30]
    DIRECTION INPUT ;
    USE SIGNAL ;
    PORT
      LAYER M5 ;
        RECT  6.144 0 6.168 0.192 ;
    END
  END d[30]
  PIN d[310]
    DIRECTION INPUT ;
    USE SIGNAL ;
    PORT
      LAYER M5 ;
        RECT  59.904 0 59.928 0.192 ;
    END
  END d[310]
  PIN d[311]
    DIRECTION INPUT ;
    USE SIGNAL ;
    PORT
      LAYER M5 ;
        RECT  60.096 0 60.12 0.192 ;
    END
  END d[311]
  PIN d[312]
    DIRECTION INPUT ;
    USE SIGNAL ;
    PORT
      LAYER M5 ;
        RECT  60.288 0 60.312 0.192 ;
    END
  END d[312]
  PIN d[313]
    DIRECTION INPUT ;
    USE SIGNAL ;
    PORT
      LAYER M5 ;
        RECT  60.48 0 60.504 0.192 ;
    END
  END d[313]
  PIN d[314]
    DIRECTION INPUT ;
    USE SIGNAL ;
    PORT
      LAYER M5 ;
        RECT  60.672 0 60.696 0.192 ;
    END
  END d[314]
  PIN d[315]
    DIRECTION INPUT ;
    USE SIGNAL ;
    PORT
      LAYER M5 ;
        RECT  60.864 0 60.888 0.192 ;
    END
  END d[315]
  PIN d[316]
    DIRECTION INPUT ;
    USE SIGNAL ;
    PORT
      LAYER M5 ;
        RECT  61.056 0 61.08 0.192 ;
    END
  END d[316]
  PIN d[317]
    DIRECTION INPUT ;
    USE SIGNAL ;
    PORT
      LAYER M5 ;
        RECT  61.248 0 61.272 0.192 ;
    END
  END d[317]
  PIN d[318]
    DIRECTION INPUT ;
    USE SIGNAL ;
    PORT
      LAYER M5 ;
        RECT  61.44 0 61.464 0.192 ;
    END
  END d[318]
  PIN d[319]
    DIRECTION INPUT ;
    USE SIGNAL ;
    PORT
      LAYER M5 ;
        RECT  61.632 0 61.656 0.192 ;
    END
  END d[319]
  PIN d[31]
    DIRECTION INPUT ;
    USE SIGNAL ;
    PORT
      LAYER M5 ;
        RECT  6.336 0 6.36 0.192 ;
    END
  END d[31]
  PIN d[320]
    DIRECTION INPUT ;
    USE SIGNAL ;
    PORT
      LAYER M5 ;
        RECT  61.824 0 61.848 0.192 ;
    END
  END d[320]
  PIN d[321]
    DIRECTION INPUT ;
    USE SIGNAL ;
    PORT
      LAYER M5 ;
        RECT  62.016 0 62.04 0.192 ;
    END
  END d[321]
  PIN d[322]
    DIRECTION INPUT ;
    USE SIGNAL ;
    PORT
      LAYER M5 ;
        RECT  62.208 0 62.232 0.192 ;
    END
  END d[322]
  PIN d[323]
    DIRECTION INPUT ;
    USE SIGNAL ;
    PORT
      LAYER M5 ;
        RECT  62.4 0 62.424 0.192 ;
    END
  END d[323]
  PIN d[324]
    DIRECTION INPUT ;
    USE SIGNAL ;
    PORT
      LAYER M5 ;
        RECT  62.592 0 62.616 0.192 ;
    END
  END d[324]
  PIN d[325]
    DIRECTION INPUT ;
    USE SIGNAL ;
    PORT
      LAYER M5 ;
        RECT  62.784 0 62.808 0.192 ;
    END
  END d[325]
  PIN d[326]
    DIRECTION INPUT ;
    USE SIGNAL ;
    PORT
      LAYER M5 ;
        RECT  62.976 0 63 0.192 ;
    END
  END d[326]
  PIN d[327]
    DIRECTION INPUT ;
    USE SIGNAL ;
    PORT
      LAYER M5 ;
        RECT  63.168 0 63.192 0.192 ;
    END
  END d[327]
  PIN d[328]
    DIRECTION INPUT ;
    USE SIGNAL ;
    PORT
      LAYER M5 ;
        RECT  63.36 0 63.384 0.192 ;
    END
  END d[328]
  PIN d[329]
    DIRECTION INPUT ;
    USE SIGNAL ;
    PORT
      LAYER M5 ;
        RECT  63.552 0 63.576 0.192 ;
    END
  END d[329]
  PIN d[32]
    DIRECTION INPUT ;
    USE SIGNAL ;
    PORT
      LAYER M5 ;
        RECT  6.528 0 6.552 0.192 ;
    END
  END d[32]
  PIN d[330]
    DIRECTION INPUT ;
    USE SIGNAL ;
    PORT
      LAYER M5 ;
        RECT  63.744 0 63.768 0.192 ;
    END
  END d[330]
  PIN d[331]
    DIRECTION INPUT ;
    USE SIGNAL ;
    PORT
      LAYER M5 ;
        RECT  63.936 0 63.96 0.192 ;
    END
  END d[331]
  PIN d[332]
    DIRECTION INPUT ;
    USE SIGNAL ;
    PORT
      LAYER M5 ;
        RECT  64.128 0 64.152 0.192 ;
    END
  END d[332]
  PIN d[333]
    DIRECTION INPUT ;
    USE SIGNAL ;
    PORT
      LAYER M5 ;
        RECT  64.32 0 64.344 0.192 ;
    END
  END d[333]
  PIN d[334]
    DIRECTION INPUT ;
    USE SIGNAL ;
    PORT
      LAYER M5 ;
        RECT  64.512 0 64.536 0.192 ;
    END
  END d[334]
  PIN d[335]
    DIRECTION INPUT ;
    USE SIGNAL ;
    PORT
      LAYER M5 ;
        RECT  64.704 0 64.728 0.192 ;
    END
  END d[335]
  PIN d[336]
    DIRECTION INPUT ;
    USE SIGNAL ;
    PORT
      LAYER M5 ;
        RECT  64.896 0 64.92 0.192 ;
    END
  END d[336]
  PIN d[337]
    DIRECTION INPUT ;
    USE SIGNAL ;
    PORT
      LAYER M5 ;
        RECT  65.088 0 65.112 0.192 ;
    END
  END d[337]
  PIN d[338]
    DIRECTION INPUT ;
    USE SIGNAL ;
    PORT
      LAYER M5 ;
        RECT  65.28 0 65.304 0.192 ;
    END
  END d[338]
  PIN d[339]
    DIRECTION INPUT ;
    USE SIGNAL ;
    PORT
      LAYER M5 ;
        RECT  65.472 0 65.496 0.192 ;
    END
  END d[339]
  PIN d[33]
    DIRECTION INPUT ;
    USE SIGNAL ;
    PORT
      LAYER M5 ;
        RECT  6.72 0 6.744 0.192 ;
    END
  END d[33]
  PIN d[340]
    DIRECTION INPUT ;
    USE SIGNAL ;
    PORT
      LAYER M5 ;
        RECT  65.664 0 65.688 0.192 ;
    END
  END d[340]
  PIN d[341]
    DIRECTION INPUT ;
    USE SIGNAL ;
    PORT
      LAYER M5 ;
        RECT  65.856 0 65.88 0.192 ;
    END
  END d[341]
  PIN d[342]
    DIRECTION INPUT ;
    USE SIGNAL ;
    PORT
      LAYER M5 ;
        RECT  66.048 0 66.072 0.192 ;
    END
  END d[342]
  PIN d[343]
    DIRECTION INPUT ;
    USE SIGNAL ;
    PORT
      LAYER M5 ;
        RECT  66.24 0 66.264 0.192 ;
    END
  END d[343]
  PIN d[344]
    DIRECTION INPUT ;
    USE SIGNAL ;
    PORT
      LAYER M5 ;
        RECT  66.432 0 66.456 0.192 ;
    END
  END d[344]
  PIN d[345]
    DIRECTION INPUT ;
    USE SIGNAL ;
    PORT
      LAYER M5 ;
        RECT  66.624 0 66.648 0.192 ;
    END
  END d[345]
  PIN d[346]
    DIRECTION INPUT ;
    USE SIGNAL ;
    PORT
      LAYER M5 ;
        RECT  66.816 0 66.84 0.192 ;
    END
  END d[346]
  PIN d[347]
    DIRECTION INPUT ;
    USE SIGNAL ;
    PORT
      LAYER M5 ;
        RECT  67.008 0 67.032 0.192 ;
    END
  END d[347]
  PIN d[348]
    DIRECTION INPUT ;
    USE SIGNAL ;
    PORT
      LAYER M5 ;
        RECT  67.2 0 67.224 0.192 ;
    END
  END d[348]
  PIN d[349]
    DIRECTION INPUT ;
    USE SIGNAL ;
    PORT
      LAYER M5 ;
        RECT  67.392 0 67.416 0.192 ;
    END
  END d[349]
  PIN d[34]
    DIRECTION INPUT ;
    USE SIGNAL ;
    PORT
      LAYER M5 ;
        RECT  6.912 0 6.936 0.192 ;
    END
  END d[34]
  PIN d[350]
    DIRECTION INPUT ;
    USE SIGNAL ;
    PORT
      LAYER M5 ;
        RECT  67.584 0 67.608 0.192 ;
    END
  END d[350]
  PIN d[351]
    DIRECTION INPUT ;
    USE SIGNAL ;
    PORT
      LAYER M5 ;
        RECT  67.776 0 67.8 0.192 ;
    END
  END d[351]
  PIN d[352]
    DIRECTION INPUT ;
    USE SIGNAL ;
    PORT
      LAYER M5 ;
        RECT  67.968 0 67.992 0.192 ;
    END
  END d[352]
  PIN d[353]
    DIRECTION INPUT ;
    USE SIGNAL ;
    PORT
      LAYER M5 ;
        RECT  68.16 0 68.184 0.192 ;
    END
  END d[353]
  PIN d[354]
    DIRECTION INPUT ;
    USE SIGNAL ;
    PORT
      LAYER M5 ;
        RECT  68.352 0 68.376 0.192 ;
    END
  END d[354]
  PIN d[355]
    DIRECTION INPUT ;
    USE SIGNAL ;
    PORT
      LAYER M5 ;
        RECT  68.544 0 68.568 0.192 ;
    END
  END d[355]
  PIN d[356]
    DIRECTION INPUT ;
    USE SIGNAL ;
    PORT
      LAYER M5 ;
        RECT  68.736 0 68.76 0.192 ;
    END
  END d[356]
  PIN d[357]
    DIRECTION INPUT ;
    USE SIGNAL ;
    PORT
      LAYER M5 ;
        RECT  68.928 0 68.952 0.192 ;
    END
  END d[357]
  PIN d[358]
    DIRECTION INPUT ;
    USE SIGNAL ;
    PORT
      LAYER M5 ;
        RECT  69.12 0 69.144 0.192 ;
    END
  END d[358]
  PIN d[359]
    DIRECTION INPUT ;
    USE SIGNAL ;
    PORT
      LAYER M5 ;
        RECT  69.312 0 69.336 0.192 ;
    END
  END d[359]
  PIN d[35]
    DIRECTION INPUT ;
    USE SIGNAL ;
    PORT
      LAYER M5 ;
        RECT  7.104 0 7.128 0.192 ;
    END
  END d[35]
  PIN d[360]
    DIRECTION INPUT ;
    USE SIGNAL ;
    PORT
      LAYER M5 ;
        RECT  69.504 0 69.528 0.192 ;
    END
  END d[360]
  PIN d[361]
    DIRECTION INPUT ;
    USE SIGNAL ;
    PORT
      LAYER M5 ;
        RECT  69.696 0 69.72 0.192 ;
    END
  END d[361]
  PIN d[362]
    DIRECTION INPUT ;
    USE SIGNAL ;
    PORT
      LAYER M5 ;
        RECT  69.888 0 69.912 0.192 ;
    END
  END d[362]
  PIN d[363]
    DIRECTION INPUT ;
    USE SIGNAL ;
    PORT
      LAYER M5 ;
        RECT  70.08 0 70.104 0.192 ;
    END
  END d[363]
  PIN d[364]
    DIRECTION INPUT ;
    USE SIGNAL ;
    PORT
      LAYER M5 ;
        RECT  70.272 0 70.296 0.192 ;
    END
  END d[364]
  PIN d[365]
    DIRECTION INPUT ;
    USE SIGNAL ;
    PORT
      LAYER M5 ;
        RECT  70.464 0 70.488 0.192 ;
    END
  END d[365]
  PIN d[366]
    DIRECTION INPUT ;
    USE SIGNAL ;
    PORT
      LAYER M5 ;
        RECT  70.656 0 70.68 0.192 ;
    END
  END d[366]
  PIN d[367]
    DIRECTION INPUT ;
    USE SIGNAL ;
    PORT
      LAYER M5 ;
        RECT  70.848 0 70.872 0.192 ;
    END
  END d[367]
  PIN d[368]
    DIRECTION INPUT ;
    USE SIGNAL ;
    PORT
      LAYER M5 ;
        RECT  71.04 0 71.064 0.192 ;
    END
  END d[368]
  PIN d[369]
    DIRECTION INPUT ;
    USE SIGNAL ;
    PORT
      LAYER M5 ;
        RECT  71.232 0 71.256 0.192 ;
    END
  END d[369]
  PIN d[36]
    DIRECTION INPUT ;
    USE SIGNAL ;
    PORT
      LAYER M5 ;
        RECT  7.296 0 7.32 0.192 ;
    END
  END d[36]
  PIN d[370]
    DIRECTION INPUT ;
    USE SIGNAL ;
    PORT
      LAYER M5 ;
        RECT  71.424 0 71.448 0.192 ;
    END
  END d[370]
  PIN d[371]
    DIRECTION INPUT ;
    USE SIGNAL ;
    PORT
      LAYER M5 ;
        RECT  71.616 0 71.64 0.192 ;
    END
  END d[371]
  PIN d[372]
    DIRECTION INPUT ;
    USE SIGNAL ;
    PORT
      LAYER M5 ;
        RECT  71.808 0 71.832 0.192 ;
    END
  END d[372]
  PIN d[373]
    DIRECTION INPUT ;
    USE SIGNAL ;
    PORT
      LAYER M5 ;
        RECT  72 0 72.024 0.192 ;
    END
  END d[373]
  PIN d[374]
    DIRECTION INPUT ;
    USE SIGNAL ;
    PORT
      LAYER M5 ;
        RECT  72.192 0 72.216 0.192 ;
    END
  END d[374]
  PIN d[375]
    DIRECTION INPUT ;
    USE SIGNAL ;
    PORT
      LAYER M5 ;
        RECT  72.384 0 72.408 0.192 ;
    END
  END d[375]
  PIN d[376]
    DIRECTION INPUT ;
    USE SIGNAL ;
    PORT
      LAYER M5 ;
        RECT  72.576 0 72.6 0.192 ;
    END
  END d[376]
  PIN d[377]
    DIRECTION INPUT ;
    USE SIGNAL ;
    PORT
      LAYER M5 ;
        RECT  72.768 0 72.792 0.192 ;
    END
  END d[377]
  PIN d[378]
    DIRECTION INPUT ;
    USE SIGNAL ;
    PORT
      LAYER M5 ;
        RECT  72.96 0 72.984 0.192 ;
    END
  END d[378]
  PIN d[379]
    DIRECTION INPUT ;
    USE SIGNAL ;
    PORT
      LAYER M5 ;
        RECT  73.152 0 73.176 0.192 ;
    END
  END d[379]
  PIN d[37]
    DIRECTION INPUT ;
    USE SIGNAL ;
    PORT
      LAYER M5 ;
        RECT  7.488 0 7.512 0.192 ;
    END
  END d[37]
  PIN d[380]
    DIRECTION INPUT ;
    USE SIGNAL ;
    PORT
      LAYER M5 ;
        RECT  73.344 0 73.368 0.192 ;
    END
  END d[380]
  PIN d[381]
    DIRECTION INPUT ;
    USE SIGNAL ;
    PORT
      LAYER M5 ;
        RECT  73.536 0 73.56 0.192 ;
    END
  END d[381]
  PIN d[382]
    DIRECTION INPUT ;
    USE SIGNAL ;
    PORT
      LAYER M5 ;
        RECT  73.728 0 73.752 0.192 ;
    END
  END d[382]
  PIN d[383]
    DIRECTION INPUT ;
    USE SIGNAL ;
    PORT
      LAYER M5 ;
        RECT  73.92 0 73.944 0.192 ;
    END
  END d[383]
  PIN d[384]
    DIRECTION INPUT ;
    USE SIGNAL ;
    PORT
      LAYER M5 ;
        RECT  74.112 0 74.136 0.192 ;
    END
  END d[384]
  PIN d[385]
    DIRECTION INPUT ;
    USE SIGNAL ;
    PORT
      LAYER M5 ;
        RECT  74.304 0 74.328 0.192 ;
    END
  END d[385]
  PIN d[386]
    DIRECTION INPUT ;
    USE SIGNAL ;
    PORT
      LAYER M5 ;
        RECT  74.496 0 74.52 0.192 ;
    END
  END d[386]
  PIN d[387]
    DIRECTION INPUT ;
    USE SIGNAL ;
    PORT
      LAYER M5 ;
        RECT  74.688 0 74.712 0.192 ;
    END
  END d[387]
  PIN d[388]
    DIRECTION INPUT ;
    USE SIGNAL ;
    PORT
      LAYER M5 ;
        RECT  74.88 0 74.904 0.192 ;
    END
  END d[388]
  PIN d[389]
    DIRECTION INPUT ;
    USE SIGNAL ;
    PORT
      LAYER M5 ;
        RECT  75.072 0 75.096 0.192 ;
    END
  END d[389]
  PIN d[38]
    DIRECTION INPUT ;
    USE SIGNAL ;
    PORT
      LAYER M5 ;
        RECT  7.68 0 7.704 0.192 ;
    END
  END d[38]
  PIN d[390]
    DIRECTION INPUT ;
    USE SIGNAL ;
    PORT
      LAYER M5 ;
        RECT  75.264 0 75.288 0.192 ;
    END
  END d[390]
  PIN d[391]
    DIRECTION INPUT ;
    USE SIGNAL ;
    PORT
      LAYER M5 ;
        RECT  75.456 0 75.48 0.192 ;
    END
  END d[391]
  PIN d[392]
    DIRECTION INPUT ;
    USE SIGNAL ;
    PORT
      LAYER M5 ;
        RECT  75.648 0 75.672 0.192 ;
    END
  END d[392]
  PIN d[393]
    DIRECTION INPUT ;
    USE SIGNAL ;
    PORT
      LAYER M5 ;
        RECT  75.84 0 75.864 0.192 ;
    END
  END d[393]
  PIN d[394]
    DIRECTION INPUT ;
    USE SIGNAL ;
    PORT
      LAYER M5 ;
        RECT  76.032 0 76.056 0.192 ;
    END
  END d[394]
  PIN d[395]
    DIRECTION INPUT ;
    USE SIGNAL ;
    PORT
      LAYER M5 ;
        RECT  76.224 0 76.248 0.192 ;
    END
  END d[395]
  PIN d[396]
    DIRECTION INPUT ;
    USE SIGNAL ;
    PORT
      LAYER M5 ;
        RECT  76.416 0 76.44 0.192 ;
    END
  END d[396]
  PIN d[397]
    DIRECTION INPUT ;
    USE SIGNAL ;
    PORT
      LAYER M5 ;
        RECT  76.608 0 76.632 0.192 ;
    END
  END d[397]
  PIN d[398]
    DIRECTION INPUT ;
    USE SIGNAL ;
    PORT
      LAYER M5 ;
        RECT  76.8 0 76.824 0.192 ;
    END
  END d[398]
  PIN d[399]
    DIRECTION INPUT ;
    USE SIGNAL ;
    PORT
      LAYER M5 ;
        RECT  76.992 0 77.016 0.192 ;
    END
  END d[399]
  PIN d[39]
    DIRECTION INPUT ;
    USE SIGNAL ;
    PORT
      LAYER M5 ;
        RECT  7.872 0 7.896 0.192 ;
    END
  END d[39]
  PIN d[3]
    DIRECTION INPUT ;
    USE SIGNAL ;
    PORT
      LAYER M5 ;
        RECT  0.96 0 0.984 0.192 ;
    END
  END d[3]
  PIN d[400]
    DIRECTION INPUT ;
    USE SIGNAL ;
    PORT
      LAYER M5 ;
        RECT  77.184 0 77.208 0.192 ;
    END
  END d[400]
  PIN d[401]
    DIRECTION INPUT ;
    USE SIGNAL ;
    PORT
      LAYER M5 ;
        RECT  77.376 0 77.4 0.192 ;
    END
  END d[401]
  PIN d[402]
    DIRECTION INPUT ;
    USE SIGNAL ;
    PORT
      LAYER M5 ;
        RECT  77.568 0 77.592 0.192 ;
    END
  END d[402]
  PIN d[403]
    DIRECTION INPUT ;
    USE SIGNAL ;
    PORT
      LAYER M5 ;
        RECT  77.76 0 77.784 0.192 ;
    END
  END d[403]
  PIN d[404]
    DIRECTION INPUT ;
    USE SIGNAL ;
    PORT
      LAYER M5 ;
        RECT  77.952 0 77.976 0.192 ;
    END
  END d[404]
  PIN d[405]
    DIRECTION INPUT ;
    USE SIGNAL ;
    PORT
      LAYER M5 ;
        RECT  78.144 0 78.168 0.192 ;
    END
  END d[405]
  PIN d[406]
    DIRECTION INPUT ;
    USE SIGNAL ;
    PORT
      LAYER M5 ;
        RECT  78.336 0 78.36 0.192 ;
    END
  END d[406]
  PIN d[407]
    DIRECTION INPUT ;
    USE SIGNAL ;
    PORT
      LAYER M5 ;
        RECT  78.528 0 78.552 0.192 ;
    END
  END d[407]
  PIN d[408]
    DIRECTION INPUT ;
    USE SIGNAL ;
    PORT
      LAYER M5 ;
        RECT  78.72 0 78.744 0.192 ;
    END
  END d[408]
  PIN d[409]
    DIRECTION INPUT ;
    USE SIGNAL ;
    PORT
      LAYER M5 ;
        RECT  78.912 0 78.936 0.192 ;
    END
  END d[409]
  PIN d[40]
    DIRECTION INPUT ;
    USE SIGNAL ;
    PORT
      LAYER M5 ;
        RECT  8.064 0 8.088 0.192 ;
    END
  END d[40]
  PIN d[410]
    DIRECTION INPUT ;
    USE SIGNAL ;
    PORT
      LAYER M5 ;
        RECT  79.104 0 79.128 0.192 ;
    END
  END d[410]
  PIN d[411]
    DIRECTION INPUT ;
    USE SIGNAL ;
    PORT
      LAYER M5 ;
        RECT  79.296 0 79.32 0.192 ;
    END
  END d[411]
  PIN d[412]
    DIRECTION INPUT ;
    USE SIGNAL ;
    PORT
      LAYER M5 ;
        RECT  79.488 0 79.512 0.192 ;
    END
  END d[412]
  PIN d[413]
    DIRECTION INPUT ;
    USE SIGNAL ;
    PORT
      LAYER M5 ;
        RECT  79.68 0 79.704 0.192 ;
    END
  END d[413]
  PIN d[414]
    DIRECTION INPUT ;
    USE SIGNAL ;
    PORT
      LAYER M5 ;
        RECT  79.872 0 79.896 0.192 ;
    END
  END d[414]
  PIN d[415]
    DIRECTION INPUT ;
    USE SIGNAL ;
    PORT
      LAYER M5 ;
        RECT  80.064 0 80.088 0.192 ;
    END
  END d[415]
  PIN d[416]
    DIRECTION INPUT ;
    USE SIGNAL ;
    PORT
      LAYER M5 ;
        RECT  80.256 0 80.28 0.192 ;
    END
  END d[416]
  PIN d[417]
    DIRECTION INPUT ;
    USE SIGNAL ;
    PORT
      LAYER M5 ;
        RECT  80.448 0 80.472 0.192 ;
    END
  END d[417]
  PIN d[418]
    DIRECTION INPUT ;
    USE SIGNAL ;
    PORT
      LAYER M5 ;
        RECT  80.64 0 80.664 0.192 ;
    END
  END d[418]
  PIN d[419]
    DIRECTION INPUT ;
    USE SIGNAL ;
    PORT
      LAYER M5 ;
        RECT  80.832 0 80.856 0.192 ;
    END
  END d[419]
  PIN d[41]
    DIRECTION INPUT ;
    USE SIGNAL ;
    PORT
      LAYER M5 ;
        RECT  8.256 0 8.28 0.192 ;
    END
  END d[41]
  PIN d[420]
    DIRECTION INPUT ;
    USE SIGNAL ;
    PORT
      LAYER M5 ;
        RECT  81.024 0 81.048 0.192 ;
    END
  END d[420]
  PIN d[421]
    DIRECTION INPUT ;
    USE SIGNAL ;
    PORT
      LAYER M5 ;
        RECT  81.216 0 81.24 0.192 ;
    END
  END d[421]
  PIN d[422]
    DIRECTION INPUT ;
    USE SIGNAL ;
    PORT
      LAYER M5 ;
        RECT  81.408 0 81.432 0.192 ;
    END
  END d[422]
  PIN d[423]
    DIRECTION INPUT ;
    USE SIGNAL ;
    PORT
      LAYER M5 ;
        RECT  81.6 0 81.624 0.192 ;
    END
  END d[423]
  PIN d[424]
    DIRECTION INPUT ;
    USE SIGNAL ;
    PORT
      LAYER M5 ;
        RECT  81.792 0 81.816 0.192 ;
    END
  END d[424]
  PIN d[425]
    DIRECTION INPUT ;
    USE SIGNAL ;
    PORT
      LAYER M5 ;
        RECT  81.984 0 82.008 0.192 ;
    END
  END d[425]
  PIN d[426]
    DIRECTION INPUT ;
    USE SIGNAL ;
    PORT
      LAYER M5 ;
        RECT  82.176 0 82.2 0.192 ;
    END
  END d[426]
  PIN d[427]
    DIRECTION INPUT ;
    USE SIGNAL ;
    PORT
      LAYER M5 ;
        RECT  82.368 0 82.392 0.192 ;
    END
  END d[427]
  PIN d[428]
    DIRECTION INPUT ;
    USE SIGNAL ;
    PORT
      LAYER M5 ;
        RECT  82.56 0 82.584 0.192 ;
    END
  END d[428]
  PIN d[429]
    DIRECTION INPUT ;
    USE SIGNAL ;
    PORT
      LAYER M5 ;
        RECT  82.752 0 82.776 0.192 ;
    END
  END d[429]
  PIN d[42]
    DIRECTION INPUT ;
    USE SIGNAL ;
    PORT
      LAYER M5 ;
        RECT  8.448 0 8.472 0.192 ;
    END
  END d[42]
  PIN d[430]
    DIRECTION INPUT ;
    USE SIGNAL ;
    PORT
      LAYER M5 ;
        RECT  82.944 0 82.968 0.192 ;
    END
  END d[430]
  PIN d[431]
    DIRECTION INPUT ;
    USE SIGNAL ;
    PORT
      LAYER M5 ;
        RECT  83.136 0 83.16 0.192 ;
    END
  END d[431]
  PIN d[432]
    DIRECTION INPUT ;
    USE SIGNAL ;
    PORT
      LAYER M5 ;
        RECT  83.328 0 83.352 0.192 ;
    END
  END d[432]
  PIN d[433]
    DIRECTION INPUT ;
    USE SIGNAL ;
    PORT
      LAYER M5 ;
        RECT  83.52 0 83.544 0.192 ;
    END
  END d[433]
  PIN d[434]
    DIRECTION INPUT ;
    USE SIGNAL ;
    PORT
      LAYER M5 ;
        RECT  83.712 0 83.736 0.192 ;
    END
  END d[434]
  PIN d[435]
    DIRECTION INPUT ;
    USE SIGNAL ;
    PORT
      LAYER M5 ;
        RECT  83.904 0 83.928 0.192 ;
    END
  END d[435]
  PIN d[436]
    DIRECTION INPUT ;
    USE SIGNAL ;
    PORT
      LAYER M5 ;
        RECT  84.096 0 84.12 0.192 ;
    END
  END d[436]
  PIN d[437]
    DIRECTION INPUT ;
    USE SIGNAL ;
    PORT
      LAYER M5 ;
        RECT  84.288 0 84.312 0.192 ;
    END
  END d[437]
  PIN d[438]
    DIRECTION INPUT ;
    USE SIGNAL ;
    PORT
      LAYER M5 ;
        RECT  84.48 0 84.504 0.192 ;
    END
  END d[438]
  PIN d[439]
    DIRECTION INPUT ;
    USE SIGNAL ;
    PORT
      LAYER M5 ;
        RECT  84.672 0 84.696 0.192 ;
    END
  END d[439]
  PIN d[43]
    DIRECTION INPUT ;
    USE SIGNAL ;
    PORT
      LAYER M5 ;
        RECT  8.64 0 8.664 0.192 ;
    END
  END d[43]
  PIN d[440]
    DIRECTION INPUT ;
    USE SIGNAL ;
    PORT
      LAYER M5 ;
        RECT  84.864 0 84.888 0.192 ;
    END
  END d[440]
  PIN d[441]
    DIRECTION INPUT ;
    USE SIGNAL ;
    PORT
      LAYER M5 ;
        RECT  85.056 0 85.08 0.192 ;
    END
  END d[441]
  PIN d[442]
    DIRECTION INPUT ;
    USE SIGNAL ;
    PORT
      LAYER M5 ;
        RECT  85.248 0 85.272 0.192 ;
    END
  END d[442]
  PIN d[443]
    DIRECTION INPUT ;
    USE SIGNAL ;
    PORT
      LAYER M5 ;
        RECT  85.44 0 85.464 0.192 ;
    END
  END d[443]
  PIN d[444]
    DIRECTION INPUT ;
    USE SIGNAL ;
    PORT
      LAYER M5 ;
        RECT  85.632 0 85.656 0.192 ;
    END
  END d[444]
  PIN d[445]
    DIRECTION INPUT ;
    USE SIGNAL ;
    PORT
      LAYER M5 ;
        RECT  85.824 0 85.848 0.192 ;
    END
  END d[445]
  PIN d[446]
    DIRECTION INPUT ;
    USE SIGNAL ;
    PORT
      LAYER M5 ;
        RECT  86.016 0 86.04 0.192 ;
    END
  END d[446]
  PIN d[447]
    DIRECTION INPUT ;
    USE SIGNAL ;
    PORT
      LAYER M5 ;
        RECT  86.208 0 86.232 0.192 ;
    END
  END d[447]
  PIN d[448]
    DIRECTION INPUT ;
    USE SIGNAL ;
    PORT
      LAYER M5 ;
        RECT  86.4 0 86.424 0.192 ;
    END
  END d[448]
  PIN d[449]
    DIRECTION INPUT ;
    USE SIGNAL ;
    PORT
      LAYER M5 ;
        RECT  86.592 0 86.616 0.192 ;
    END
  END d[449]
  PIN d[44]
    DIRECTION INPUT ;
    USE SIGNAL ;
    PORT
      LAYER M5 ;
        RECT  8.832 0 8.856 0.192 ;
    END
  END d[44]
  PIN d[450]
    DIRECTION INPUT ;
    USE SIGNAL ;
    PORT
      LAYER M5 ;
        RECT  86.784 0 86.808 0.192 ;
    END
  END d[450]
  PIN d[451]
    DIRECTION INPUT ;
    USE SIGNAL ;
    PORT
      LAYER M5 ;
        RECT  86.976 0 87 0.192 ;
    END
  END d[451]
  PIN d[452]
    DIRECTION INPUT ;
    USE SIGNAL ;
    PORT
      LAYER M5 ;
        RECT  87.168 0 87.192 0.192 ;
    END
  END d[452]
  PIN d[453]
    DIRECTION INPUT ;
    USE SIGNAL ;
    PORT
      LAYER M5 ;
        RECT  87.36 0 87.384 0.192 ;
    END
  END d[453]
  PIN d[454]
    DIRECTION INPUT ;
    USE SIGNAL ;
    PORT
      LAYER M5 ;
        RECT  87.552 0 87.576 0.192 ;
    END
  END d[454]
  PIN d[455]
    DIRECTION INPUT ;
    USE SIGNAL ;
    PORT
      LAYER M5 ;
        RECT  87.744 0 87.768 0.192 ;
    END
  END d[455]
  PIN d[456]
    DIRECTION INPUT ;
    USE SIGNAL ;
    PORT
      LAYER M5 ;
        RECT  87.936 0 87.96 0.192 ;
    END
  END d[456]
  PIN d[457]
    DIRECTION INPUT ;
    USE SIGNAL ;
    PORT
      LAYER M5 ;
        RECT  88.128 0 88.152 0.192 ;
    END
  END d[457]
  PIN d[458]
    DIRECTION INPUT ;
    USE SIGNAL ;
    PORT
      LAYER M5 ;
        RECT  88.32 0 88.344 0.192 ;
    END
  END d[458]
  PIN d[459]
    DIRECTION INPUT ;
    USE SIGNAL ;
    PORT
      LAYER M5 ;
        RECT  88.512 0 88.536 0.192 ;
    END
  END d[459]
  PIN d[45]
    DIRECTION INPUT ;
    USE SIGNAL ;
    PORT
      LAYER M5 ;
        RECT  9.024 0 9.048 0.192 ;
    END
  END d[45]
  PIN d[460]
    DIRECTION INPUT ;
    USE SIGNAL ;
    PORT
      LAYER M5 ;
        RECT  88.704 0 88.728 0.192 ;
    END
  END d[460]
  PIN d[461]
    DIRECTION INPUT ;
    USE SIGNAL ;
    PORT
      LAYER M5 ;
        RECT  88.896 0 88.92 0.192 ;
    END
  END d[461]
  PIN d[462]
    DIRECTION INPUT ;
    USE SIGNAL ;
    PORT
      LAYER M5 ;
        RECT  89.088 0 89.112 0.192 ;
    END
  END d[462]
  PIN d[463]
    DIRECTION INPUT ;
    USE SIGNAL ;
    PORT
      LAYER M5 ;
        RECT  89.28 0 89.304 0.192 ;
    END
  END d[463]
  PIN d[464]
    DIRECTION INPUT ;
    USE SIGNAL ;
    PORT
      LAYER M5 ;
        RECT  89.472 0 89.496 0.192 ;
    END
  END d[464]
  PIN d[465]
    DIRECTION INPUT ;
    USE SIGNAL ;
    PORT
      LAYER M5 ;
        RECT  89.664 0 89.688 0.192 ;
    END
  END d[465]
  PIN d[466]
    DIRECTION INPUT ;
    USE SIGNAL ;
    PORT
      LAYER M5 ;
        RECT  89.856 0 89.88 0.192 ;
    END
  END d[466]
  PIN d[467]
    DIRECTION INPUT ;
    USE SIGNAL ;
    PORT
      LAYER M5 ;
        RECT  90.048 0 90.072 0.192 ;
    END
  END d[467]
  PIN d[468]
    DIRECTION INPUT ;
    USE SIGNAL ;
    PORT
      LAYER M5 ;
        RECT  90.24 0 90.264 0.192 ;
    END
  END d[468]
  PIN d[469]
    DIRECTION INPUT ;
    USE SIGNAL ;
    PORT
      LAYER M5 ;
        RECT  90.432 0 90.456 0.192 ;
    END
  END d[469]
  PIN d[46]
    DIRECTION INPUT ;
    USE SIGNAL ;
    PORT
      LAYER M5 ;
        RECT  9.216 0 9.24 0.192 ;
    END
  END d[46]
  PIN d[470]
    DIRECTION INPUT ;
    USE SIGNAL ;
    PORT
      LAYER M5 ;
        RECT  90.624 0 90.648 0.192 ;
    END
  END d[470]
  PIN d[471]
    DIRECTION INPUT ;
    USE SIGNAL ;
    PORT
      LAYER M5 ;
        RECT  90.816 0 90.84 0.192 ;
    END
  END d[471]
  PIN d[472]
    DIRECTION INPUT ;
    USE SIGNAL ;
    PORT
      LAYER M5 ;
        RECT  91.008 0 91.032 0.192 ;
    END
  END d[472]
  PIN d[473]
    DIRECTION INPUT ;
    USE SIGNAL ;
    PORT
      LAYER M5 ;
        RECT  91.2 0 91.224 0.192 ;
    END
  END d[473]
  PIN d[474]
    DIRECTION INPUT ;
    USE SIGNAL ;
    PORT
      LAYER M5 ;
        RECT  91.392 0 91.416 0.192 ;
    END
  END d[474]
  PIN d[475]
    DIRECTION INPUT ;
    USE SIGNAL ;
    PORT
      LAYER M5 ;
        RECT  91.584 0 91.608 0.192 ;
    END
  END d[475]
  PIN d[476]
    DIRECTION INPUT ;
    USE SIGNAL ;
    PORT
      LAYER M5 ;
        RECT  91.776 0 91.8 0.192 ;
    END
  END d[476]
  PIN d[477]
    DIRECTION INPUT ;
    USE SIGNAL ;
    PORT
      LAYER M5 ;
        RECT  91.968 0 91.992 0.192 ;
    END
  END d[477]
  PIN d[478]
    DIRECTION INPUT ;
    USE SIGNAL ;
    PORT
      LAYER M5 ;
        RECT  92.16 0 92.184 0.192 ;
    END
  END d[478]
  PIN d[479]
    DIRECTION INPUT ;
    USE SIGNAL ;
    PORT
      LAYER M5 ;
        RECT  92.352 0 92.376 0.192 ;
    END
  END d[479]
  PIN d[47]
    DIRECTION INPUT ;
    USE SIGNAL ;
    PORT
      LAYER M5 ;
        RECT  9.408 0 9.432 0.192 ;
    END
  END d[47]
  PIN d[480]
    DIRECTION INPUT ;
    USE SIGNAL ;
    PORT
      LAYER M5 ;
        RECT  92.544 0 92.568 0.192 ;
    END
  END d[480]
  PIN d[481]
    DIRECTION INPUT ;
    USE SIGNAL ;
    PORT
      LAYER M5 ;
        RECT  92.736 0 92.76 0.192 ;
    END
  END d[481]
  PIN d[482]
    DIRECTION INPUT ;
    USE SIGNAL ;
    PORT
      LAYER M5 ;
        RECT  92.928 0 92.952 0.192 ;
    END
  END d[482]
  PIN d[483]
    DIRECTION INPUT ;
    USE SIGNAL ;
    PORT
      LAYER M5 ;
        RECT  93.12 0 93.144 0.192 ;
    END
  END d[483]
  PIN d[484]
    DIRECTION INPUT ;
    USE SIGNAL ;
    PORT
      LAYER M5 ;
        RECT  93.312 0 93.336 0.192 ;
    END
  END d[484]
  PIN d[485]
    DIRECTION INPUT ;
    USE SIGNAL ;
    PORT
      LAYER M5 ;
        RECT  93.504 0 93.528 0.192 ;
    END
  END d[485]
  PIN d[486]
    DIRECTION INPUT ;
    USE SIGNAL ;
    PORT
      LAYER M5 ;
        RECT  93.696 0 93.72 0.192 ;
    END
  END d[486]
  PIN d[487]
    DIRECTION INPUT ;
    USE SIGNAL ;
    PORT
      LAYER M5 ;
        RECT  93.888 0 93.912 0.192 ;
    END
  END d[487]
  PIN d[488]
    DIRECTION INPUT ;
    USE SIGNAL ;
    PORT
      LAYER M5 ;
        RECT  94.08 0 94.104 0.192 ;
    END
  END d[488]
  PIN d[489]
    DIRECTION INPUT ;
    USE SIGNAL ;
    PORT
      LAYER M5 ;
        RECT  94.272 0 94.296 0.192 ;
    END
  END d[489]
  PIN d[48]
    DIRECTION INPUT ;
    USE SIGNAL ;
    PORT
      LAYER M5 ;
        RECT  9.6 0 9.624 0.192 ;
    END
  END d[48]
  PIN d[490]
    DIRECTION INPUT ;
    USE SIGNAL ;
    PORT
      LAYER M5 ;
        RECT  94.464 0 94.488 0.192 ;
    END
  END d[490]
  PIN d[491]
    DIRECTION INPUT ;
    USE SIGNAL ;
    PORT
      LAYER M5 ;
        RECT  94.656 0 94.68 0.192 ;
    END
  END d[491]
  PIN d[492]
    DIRECTION INPUT ;
    USE SIGNAL ;
    PORT
      LAYER M5 ;
        RECT  94.848 0 94.872 0.192 ;
    END
  END d[492]
  PIN d[493]
    DIRECTION INPUT ;
    USE SIGNAL ;
    PORT
      LAYER M5 ;
        RECT  95.04 0 95.064 0.192 ;
    END
  END d[493]
  PIN d[494]
    DIRECTION INPUT ;
    USE SIGNAL ;
    PORT
      LAYER M5 ;
        RECT  95.232 0 95.256 0.192 ;
    END
  END d[494]
  PIN d[495]
    DIRECTION INPUT ;
    USE SIGNAL ;
    PORT
      LAYER M5 ;
        RECT  95.424 0 95.448 0.192 ;
    END
  END d[495]
  PIN d[496]
    DIRECTION INPUT ;
    USE SIGNAL ;
    PORT
      LAYER M5 ;
        RECT  95.616 0 95.64 0.192 ;
    END
  END d[496]
  PIN d[497]
    DIRECTION INPUT ;
    USE SIGNAL ;
    PORT
      LAYER M5 ;
        RECT  95.808 0 95.832 0.192 ;
    END
  END d[497]
  PIN d[498]
    DIRECTION INPUT ;
    USE SIGNAL ;
    PORT
      LAYER M5 ;
        RECT  96 0 96.024 0.192 ;
    END
  END d[498]
  PIN d[499]
    DIRECTION INPUT ;
    USE SIGNAL ;
    PORT
      LAYER M5 ;
        RECT  96.192 0 96.216 0.192 ;
    END
  END d[499]
  PIN d[49]
    DIRECTION INPUT ;
    USE SIGNAL ;
    PORT
      LAYER M5 ;
        RECT  9.792 0 9.816 0.192 ;
    END
  END d[49]
  PIN d[4]
    DIRECTION INPUT ;
    USE SIGNAL ;
    PORT
      LAYER M5 ;
        RECT  1.152 0 1.176 0.192 ;
    END
  END d[4]
  PIN d[500]
    DIRECTION INPUT ;
    USE SIGNAL ;
    PORT
      LAYER M5 ;
        RECT  96.384 0 96.408 0.192 ;
    END
  END d[500]
  PIN d[501]
    DIRECTION INPUT ;
    USE SIGNAL ;
    PORT
      LAYER M5 ;
        RECT  96.576 0 96.6 0.192 ;
    END
  END d[501]
  PIN d[502]
    DIRECTION INPUT ;
    USE SIGNAL ;
    PORT
      LAYER M5 ;
        RECT  96.768 0 96.792 0.192 ;
    END
  END d[502]
  PIN d[503]
    DIRECTION INPUT ;
    USE SIGNAL ;
    PORT
      LAYER M5 ;
        RECT  96.96 0 96.984 0.192 ;
    END
  END d[503]
  PIN d[504]
    DIRECTION INPUT ;
    USE SIGNAL ;
    PORT
      LAYER M5 ;
        RECT  97.152 0 97.176 0.192 ;
    END
  END d[504]
  PIN d[505]
    DIRECTION INPUT ;
    USE SIGNAL ;
    PORT
      LAYER M5 ;
        RECT  97.344 0 97.368 0.192 ;
    END
  END d[505]
  PIN d[506]
    DIRECTION INPUT ;
    USE SIGNAL ;
    PORT
      LAYER M5 ;
        RECT  97.536 0 97.56 0.192 ;
    END
  END d[506]
  PIN d[507]
    DIRECTION INPUT ;
    USE SIGNAL ;
    PORT
      LAYER M5 ;
        RECT  97.728 0 97.752 0.192 ;
    END
  END d[507]
  PIN d[508]
    DIRECTION INPUT ;
    USE SIGNAL ;
    PORT
      LAYER M5 ;
        RECT  97.92 0 97.944 0.192 ;
    END
  END d[508]
  PIN d[509]
    DIRECTION INPUT ;
    USE SIGNAL ;
    PORT
      LAYER M5 ;
        RECT  98.112 0 98.136 0.192 ;
    END
  END d[509]
  PIN d[50]
    DIRECTION INPUT ;
    USE SIGNAL ;
    PORT
      LAYER M5 ;
        RECT  9.984 0 10.008 0.192 ;
    END
  END d[50]
  PIN d[510]
    DIRECTION INPUT ;
    USE SIGNAL ;
    PORT
      LAYER M5 ;
        RECT  98.304 0 98.328 0.192 ;
    END
  END d[510]
  PIN d[511]
    DIRECTION INPUT ;
    USE SIGNAL ;
    PORT
      LAYER M5 ;
        RECT  98.496 0 98.52 0.192 ;
    END
  END d[511]
  PIN d[512]
    DIRECTION INPUT ;
    USE SIGNAL ;
    PORT
      LAYER M5 ;
        RECT  98.688 0 98.712 0.192 ;
    END
  END d[512]
  PIN d[513]
    DIRECTION INPUT ;
    USE SIGNAL ;
    PORT
      LAYER M5 ;
        RECT  98.88 0 98.904 0.192 ;
    END
  END d[513]
  PIN d[514]
    DIRECTION INPUT ;
    USE SIGNAL ;
    PORT
      LAYER M5 ;
        RECT  99.072 0 99.096 0.192 ;
    END
  END d[514]
  PIN d[515]
    DIRECTION INPUT ;
    USE SIGNAL ;
    PORT
      LAYER M5 ;
        RECT  99.264 0 99.288 0.192 ;
    END
  END d[515]
  PIN d[516]
    DIRECTION INPUT ;
    USE SIGNAL ;
    PORT
      LAYER M5 ;
        RECT  99.456 0 99.48 0.192 ;
    END
  END d[516]
  PIN d[517]
    DIRECTION INPUT ;
    USE SIGNAL ;
    PORT
      LAYER M5 ;
        RECT  99.648 0 99.672 0.192 ;
    END
  END d[517]
  PIN d[518]
    DIRECTION INPUT ;
    USE SIGNAL ;
    PORT
      LAYER M5 ;
        RECT  99.84 0 99.864 0.192 ;
    END
  END d[518]
  PIN d[519]
    DIRECTION INPUT ;
    USE SIGNAL ;
    PORT
      LAYER M5 ;
        RECT  100.032 0 100.056 0.192 ;
    END
  END d[519]
  PIN d[51]
    DIRECTION INPUT ;
    USE SIGNAL ;
    PORT
      LAYER M5 ;
        RECT  10.176 0 10.2 0.192 ;
    END
  END d[51]
  PIN d[520]
    DIRECTION INPUT ;
    USE SIGNAL ;
    PORT
      LAYER M5 ;
        RECT  100.224 0 100.248 0.192 ;
    END
  END d[520]
  PIN d[521]
    DIRECTION INPUT ;
    USE SIGNAL ;
    PORT
      LAYER M5 ;
        RECT  100.416 0 100.44 0.192 ;
    END
  END d[521]
  PIN d[522]
    DIRECTION INPUT ;
    USE SIGNAL ;
    PORT
      LAYER M5 ;
        RECT  100.608 0 100.632 0.192 ;
    END
  END d[522]
  PIN d[523]
    DIRECTION INPUT ;
    USE SIGNAL ;
    PORT
      LAYER M5 ;
        RECT  100.8 0 100.824 0.192 ;
    END
  END d[523]
  PIN d[524]
    DIRECTION INPUT ;
    USE SIGNAL ;
    PORT
      LAYER M5 ;
        RECT  100.992 0 101.016 0.192 ;
    END
  END d[524]
  PIN d[525]
    DIRECTION INPUT ;
    USE SIGNAL ;
    PORT
      LAYER M5 ;
        RECT  101.184 0 101.208 0.192 ;
    END
  END d[525]
  PIN d[526]
    DIRECTION INPUT ;
    USE SIGNAL ;
    PORT
      LAYER M5 ;
        RECT  101.376 0 101.4 0.192 ;
    END
  END d[526]
  PIN d[527]
    DIRECTION INPUT ;
    USE SIGNAL ;
    PORT
      LAYER M5 ;
        RECT  101.568 0 101.592 0.192 ;
    END
  END d[527]
  PIN d[528]
    DIRECTION INPUT ;
    USE SIGNAL ;
    PORT
      LAYER M5 ;
        RECT  101.76 0 101.784 0.192 ;
    END
  END d[528]
  PIN d[529]
    DIRECTION INPUT ;
    USE SIGNAL ;
    PORT
      LAYER M5 ;
        RECT  101.952 0 101.976 0.192 ;
    END
  END d[529]
  PIN d[52]
    DIRECTION INPUT ;
    USE SIGNAL ;
    PORT
      LAYER M5 ;
        RECT  10.368 0 10.392 0.192 ;
    END
  END d[52]
  PIN d[530]
    DIRECTION INPUT ;
    USE SIGNAL ;
    PORT
      LAYER M5 ;
        RECT  102.144 0 102.168 0.192 ;
    END
  END d[530]
  PIN d[531]
    DIRECTION INPUT ;
    USE SIGNAL ;
    PORT
      LAYER M5 ;
        RECT  102.336 0 102.36 0.192 ;
    END
  END d[531]
  PIN d[532]
    DIRECTION INPUT ;
    USE SIGNAL ;
    PORT
      LAYER M5 ;
        RECT  102.528 0 102.552 0.192 ;
    END
  END d[532]
  PIN d[533]
    DIRECTION INPUT ;
    USE SIGNAL ;
    PORT
      LAYER M5 ;
        RECT  102.72 0 102.744 0.192 ;
    END
  END d[533]
  PIN d[534]
    DIRECTION INPUT ;
    USE SIGNAL ;
    PORT
      LAYER M5 ;
        RECT  102.912 0 102.936 0.192 ;
    END
  END d[534]
  PIN d[535]
    DIRECTION INPUT ;
    USE SIGNAL ;
    PORT
      LAYER M5 ;
        RECT  103.104 0 103.128 0.192 ;
    END
  END d[535]
  PIN d[536]
    DIRECTION INPUT ;
    USE SIGNAL ;
    PORT
      LAYER M5 ;
        RECT  103.296 0 103.32 0.192 ;
    END
  END d[536]
  PIN d[537]
    DIRECTION INPUT ;
    USE SIGNAL ;
    PORT
      LAYER M5 ;
        RECT  103.488 0 103.512 0.192 ;
    END
  END d[537]
  PIN d[538]
    DIRECTION INPUT ;
    USE SIGNAL ;
    PORT
      LAYER M5 ;
        RECT  103.68 0 103.704 0.192 ;
    END
  END d[538]
  PIN d[539]
    DIRECTION INPUT ;
    USE SIGNAL ;
    PORT
      LAYER M5 ;
        RECT  103.872 0 103.896 0.192 ;
    END
  END d[539]
  PIN d[53]
    DIRECTION INPUT ;
    USE SIGNAL ;
    PORT
      LAYER M5 ;
        RECT  10.56 0 10.584 0.192 ;
    END
  END d[53]
  PIN d[540]
    DIRECTION INPUT ;
    USE SIGNAL ;
    PORT
      LAYER M5 ;
        RECT  104.064 0 104.088 0.192 ;
    END
  END d[540]
  PIN d[541]
    DIRECTION INPUT ;
    USE SIGNAL ;
    PORT
      LAYER M5 ;
        RECT  104.256 0 104.28 0.192 ;
    END
  END d[541]
  PIN d[542]
    DIRECTION INPUT ;
    USE SIGNAL ;
    PORT
      LAYER M5 ;
        RECT  104.448 0 104.472 0.192 ;
    END
  END d[542]
  PIN d[543]
    DIRECTION INPUT ;
    USE SIGNAL ;
    PORT
      LAYER M5 ;
        RECT  104.64 0 104.664 0.192 ;
    END
  END d[543]
  PIN d[54]
    DIRECTION INPUT ;
    USE SIGNAL ;
    PORT
      LAYER M5 ;
        RECT  10.752 0 10.776 0.192 ;
    END
  END d[54]
  PIN d[55]
    DIRECTION INPUT ;
    USE SIGNAL ;
    PORT
      LAYER M5 ;
        RECT  10.944 0 10.968 0.192 ;
    END
  END d[55]
  PIN d[56]
    DIRECTION INPUT ;
    USE SIGNAL ;
    PORT
      LAYER M5 ;
        RECT  11.136 0 11.16 0.192 ;
    END
  END d[56]
  PIN d[57]
    DIRECTION INPUT ;
    USE SIGNAL ;
    PORT
      LAYER M5 ;
        RECT  11.328 0 11.352 0.192 ;
    END
  END d[57]
  PIN d[58]
    DIRECTION INPUT ;
    USE SIGNAL ;
    PORT
      LAYER M5 ;
        RECT  11.52 0 11.544 0.192 ;
    END
  END d[58]
  PIN d[59]
    DIRECTION INPUT ;
    USE SIGNAL ;
    PORT
      LAYER M5 ;
        RECT  11.712 0 11.736 0.192 ;
    END
  END d[59]
  PIN d[5]
    DIRECTION INPUT ;
    USE SIGNAL ;
    PORT
      LAYER M5 ;
        RECT  1.344 0 1.368 0.192 ;
    END
  END d[5]
  PIN d[60]
    DIRECTION INPUT ;
    USE SIGNAL ;
    PORT
      LAYER M5 ;
        RECT  11.904 0 11.928 0.192 ;
    END
  END d[60]
  PIN d[61]
    DIRECTION INPUT ;
    USE SIGNAL ;
    PORT
      LAYER M5 ;
        RECT  12.096 0 12.12 0.192 ;
    END
  END d[61]
  PIN d[62]
    DIRECTION INPUT ;
    USE SIGNAL ;
    PORT
      LAYER M5 ;
        RECT  12.288 0 12.312 0.192 ;
    END
  END d[62]
  PIN d[63]
    DIRECTION INPUT ;
    USE SIGNAL ;
    PORT
      LAYER M5 ;
        RECT  12.48 0 12.504 0.192 ;
    END
  END d[63]
  PIN d[64]
    DIRECTION INPUT ;
    USE SIGNAL ;
    PORT
      LAYER M5 ;
        RECT  12.672 0 12.696 0.192 ;
    END
  END d[64]
  PIN d[65]
    DIRECTION INPUT ;
    USE SIGNAL ;
    PORT
      LAYER M5 ;
        RECT  12.864 0 12.888 0.192 ;
    END
  END d[65]
  PIN d[66]
    DIRECTION INPUT ;
    USE SIGNAL ;
    PORT
      LAYER M5 ;
        RECT  13.056 0 13.08 0.192 ;
    END
  END d[66]
  PIN d[67]
    DIRECTION INPUT ;
    USE SIGNAL ;
    PORT
      LAYER M5 ;
        RECT  13.248 0 13.272 0.192 ;
    END
  END d[67]
  PIN d[68]
    DIRECTION INPUT ;
    USE SIGNAL ;
    PORT
      LAYER M5 ;
        RECT  13.44 0 13.464 0.192 ;
    END
  END d[68]
  PIN d[69]
    DIRECTION INPUT ;
    USE SIGNAL ;
    PORT
      LAYER M5 ;
        RECT  13.632 0 13.656 0.192 ;
    END
  END d[69]
  PIN d[6]
    DIRECTION INPUT ;
    USE SIGNAL ;
    PORT
      LAYER M5 ;
        RECT  1.536 0 1.56 0.192 ;
    END
  END d[6]
  PIN d[70]
    DIRECTION INPUT ;
    USE SIGNAL ;
    PORT
      LAYER M5 ;
        RECT  13.824 0 13.848 0.192 ;
    END
  END d[70]
  PIN d[71]
    DIRECTION INPUT ;
    USE SIGNAL ;
    PORT
      LAYER M5 ;
        RECT  14.016 0 14.04 0.192 ;
    END
  END d[71]
  PIN d[72]
    DIRECTION INPUT ;
    USE SIGNAL ;
    PORT
      LAYER M5 ;
        RECT  14.208 0 14.232 0.192 ;
    END
  END d[72]
  PIN d[73]
    DIRECTION INPUT ;
    USE SIGNAL ;
    PORT
      LAYER M5 ;
        RECT  14.4 0 14.424 0.192 ;
    END
  END d[73]
  PIN d[74]
    DIRECTION INPUT ;
    USE SIGNAL ;
    PORT
      LAYER M5 ;
        RECT  14.592 0 14.616 0.192 ;
    END
  END d[74]
  PIN d[75]
    DIRECTION INPUT ;
    USE SIGNAL ;
    PORT
      LAYER M5 ;
        RECT  14.784 0 14.808 0.192 ;
    END
  END d[75]
  PIN d[76]
    DIRECTION INPUT ;
    USE SIGNAL ;
    PORT
      LAYER M5 ;
        RECT  14.976 0 15 0.192 ;
    END
  END d[76]
  PIN d[77]
    DIRECTION INPUT ;
    USE SIGNAL ;
    PORT
      LAYER M5 ;
        RECT  15.168 0 15.192 0.192 ;
    END
  END d[77]
  PIN d[78]
    DIRECTION INPUT ;
    USE SIGNAL ;
    PORT
      LAYER M5 ;
        RECT  15.36 0 15.384 0.192 ;
    END
  END d[78]
  PIN d[79]
    DIRECTION INPUT ;
    USE SIGNAL ;
    PORT
      LAYER M5 ;
        RECT  15.552 0 15.576 0.192 ;
    END
  END d[79]
  PIN d[7]
    DIRECTION INPUT ;
    USE SIGNAL ;
    PORT
      LAYER M5 ;
        RECT  1.728 0 1.752 0.192 ;
    END
  END d[7]
  PIN d[80]
    DIRECTION INPUT ;
    USE SIGNAL ;
    PORT
      LAYER M5 ;
        RECT  15.744 0 15.768 0.192 ;
    END
  END d[80]
  PIN d[81]
    DIRECTION INPUT ;
    USE SIGNAL ;
    PORT
      LAYER M5 ;
        RECT  15.936 0 15.96 0.192 ;
    END
  END d[81]
  PIN d[82]
    DIRECTION INPUT ;
    USE SIGNAL ;
    PORT
      LAYER M5 ;
        RECT  16.128 0 16.152 0.192 ;
    END
  END d[82]
  PIN d[83]
    DIRECTION INPUT ;
    USE SIGNAL ;
    PORT
      LAYER M5 ;
        RECT  16.32 0 16.344 0.192 ;
    END
  END d[83]
  PIN d[84]
    DIRECTION INPUT ;
    USE SIGNAL ;
    PORT
      LAYER M5 ;
        RECT  16.512 0 16.536 0.192 ;
    END
  END d[84]
  PIN d[85]
    DIRECTION INPUT ;
    USE SIGNAL ;
    PORT
      LAYER M5 ;
        RECT  16.704 0 16.728 0.192 ;
    END
  END d[85]
  PIN d[86]
    DIRECTION INPUT ;
    USE SIGNAL ;
    PORT
      LAYER M5 ;
        RECT  16.896 0 16.92 0.192 ;
    END
  END d[86]
  PIN d[87]
    DIRECTION INPUT ;
    USE SIGNAL ;
    PORT
      LAYER M5 ;
        RECT  17.088 0 17.112 0.192 ;
    END
  END d[87]
  PIN d[88]
    DIRECTION INPUT ;
    USE SIGNAL ;
    PORT
      LAYER M5 ;
        RECT  17.28 0 17.304 0.192 ;
    END
  END d[88]
  PIN d[89]
    DIRECTION INPUT ;
    USE SIGNAL ;
    PORT
      LAYER M5 ;
        RECT  17.472 0 17.496 0.192 ;
    END
  END d[89]
  PIN d[8]
    DIRECTION INPUT ;
    USE SIGNAL ;
    PORT
      LAYER M5 ;
        RECT  1.92 0 1.944 0.192 ;
    END
  END d[8]
  PIN d[90]
    DIRECTION INPUT ;
    USE SIGNAL ;
    PORT
      LAYER M5 ;
        RECT  17.664 0 17.688 0.192 ;
    END
  END d[90]
  PIN d[91]
    DIRECTION INPUT ;
    USE SIGNAL ;
    PORT
      LAYER M5 ;
        RECT  17.856 0 17.88 0.192 ;
    END
  END d[91]
  PIN d[92]
    DIRECTION INPUT ;
    USE SIGNAL ;
    PORT
      LAYER M5 ;
        RECT  18.048 0 18.072 0.192 ;
    END
  END d[92]
  PIN d[93]
    DIRECTION INPUT ;
    USE SIGNAL ;
    PORT
      LAYER M5 ;
        RECT  18.24 0 18.264 0.192 ;
    END
  END d[93]
  PIN d[94]
    DIRECTION INPUT ;
    USE SIGNAL ;
    PORT
      LAYER M5 ;
        RECT  18.432 0 18.456 0.192 ;
    END
  END d[94]
  PIN d[95]
    DIRECTION INPUT ;
    USE SIGNAL ;
    PORT
      LAYER M5 ;
        RECT  18.624 0 18.648 0.192 ;
    END
  END d[95]
  PIN d[96]
    DIRECTION INPUT ;
    USE SIGNAL ;
    PORT
      LAYER M5 ;
        RECT  18.816 0 18.84 0.192 ;
    END
  END d[96]
  PIN d[97]
    DIRECTION INPUT ;
    USE SIGNAL ;
    PORT
      LAYER M5 ;
        RECT  19.008 0 19.032 0.192 ;
    END
  END d[97]
  PIN d[98]
    DIRECTION INPUT ;
    USE SIGNAL ;
    PORT
      LAYER M5 ;
        RECT  19.2 0 19.224 0.192 ;
    END
  END d[98]
  PIN d[99]
    DIRECTION INPUT ;
    USE SIGNAL ;
    PORT
      LAYER M5 ;
        RECT  19.392 0 19.416 0.192 ;
    END
  END d[99]
  PIN d[9]
    DIRECTION INPUT ;
    USE SIGNAL ;
    PORT
      LAYER M5 ;
        RECT  2.112 0 2.136 0.192 ;
    END
  END d[9]
  PIN q[0]
    DIRECTION OUTPUT ;
    USE SIGNAL ;
    PORT
      LAYER M5 ;
        RECT  0.384 11.688 0.408 11.88 ;
    END
  END q[0]
  PIN q[100]
    DIRECTION OUTPUT ;
    USE SIGNAL ;
    PORT
      LAYER M5 ;
        RECT  19.584 11.688 19.608 11.88 ;
    END
  END q[100]
  PIN q[101]
    DIRECTION OUTPUT ;
    USE SIGNAL ;
    PORT
      LAYER M5 ;
        RECT  19.776 11.688 19.8 11.88 ;
    END
  END q[101]
  PIN q[102]
    DIRECTION OUTPUT ;
    USE SIGNAL ;
    PORT
      LAYER M5 ;
        RECT  19.968 11.688 19.992 11.88 ;
    END
  END q[102]
  PIN q[103]
    DIRECTION OUTPUT ;
    USE SIGNAL ;
    PORT
      LAYER M5 ;
        RECT  20.16 11.688 20.184 11.88 ;
    END
  END q[103]
  PIN q[104]
    DIRECTION OUTPUT ;
    USE SIGNAL ;
    PORT
      LAYER M5 ;
        RECT  20.352 11.688 20.376 11.88 ;
    END
  END q[104]
  PIN q[105]
    DIRECTION OUTPUT ;
    USE SIGNAL ;
    PORT
      LAYER M5 ;
        RECT  20.544 11.688 20.568 11.88 ;
    END
  END q[105]
  PIN q[106]
    DIRECTION OUTPUT ;
    USE SIGNAL ;
    PORT
      LAYER M5 ;
        RECT  20.736 11.688 20.76 11.88 ;
    END
  END q[106]
  PIN q[107]
    DIRECTION OUTPUT ;
    USE SIGNAL ;
    PORT
      LAYER M5 ;
        RECT  20.928 11.688 20.952 11.88 ;
    END
  END q[107]
  PIN q[108]
    DIRECTION OUTPUT ;
    USE SIGNAL ;
    PORT
      LAYER M5 ;
        RECT  21.12 11.688 21.144 11.88 ;
    END
  END q[108]
  PIN q[109]
    DIRECTION OUTPUT ;
    USE SIGNAL ;
    PORT
      LAYER M5 ;
        RECT  21.312 11.688 21.336 11.88 ;
    END
  END q[109]
  PIN q[10]
    DIRECTION OUTPUT ;
    USE SIGNAL ;
    PORT
      LAYER M5 ;
        RECT  2.304 11.688 2.328 11.88 ;
    END
  END q[10]
  PIN q[110]
    DIRECTION OUTPUT ;
    USE SIGNAL ;
    PORT
      LAYER M5 ;
        RECT  21.504 11.688 21.528 11.88 ;
    END
  END q[110]
  PIN q[111]
    DIRECTION OUTPUT ;
    USE SIGNAL ;
    PORT
      LAYER M5 ;
        RECT  21.696 11.688 21.72 11.88 ;
    END
  END q[111]
  PIN q[112]
    DIRECTION OUTPUT ;
    USE SIGNAL ;
    PORT
      LAYER M5 ;
        RECT  21.888 11.688 21.912 11.88 ;
    END
  END q[112]
  PIN q[113]
    DIRECTION OUTPUT ;
    USE SIGNAL ;
    PORT
      LAYER M5 ;
        RECT  22.08 11.688 22.104 11.88 ;
    END
  END q[113]
  PIN q[114]
    DIRECTION OUTPUT ;
    USE SIGNAL ;
    PORT
      LAYER M5 ;
        RECT  22.272 11.688 22.296 11.88 ;
    END
  END q[114]
  PIN q[115]
    DIRECTION OUTPUT ;
    USE SIGNAL ;
    PORT
      LAYER M5 ;
        RECT  22.464 11.688 22.488 11.88 ;
    END
  END q[115]
  PIN q[116]
    DIRECTION OUTPUT ;
    USE SIGNAL ;
    PORT
      LAYER M5 ;
        RECT  22.656 11.688 22.68 11.88 ;
    END
  END q[116]
  PIN q[117]
    DIRECTION OUTPUT ;
    USE SIGNAL ;
    PORT
      LAYER M5 ;
        RECT  22.848 11.688 22.872 11.88 ;
    END
  END q[117]
  PIN q[118]
    DIRECTION OUTPUT ;
    USE SIGNAL ;
    PORT
      LAYER M5 ;
        RECT  23.04 11.688 23.064 11.88 ;
    END
  END q[118]
  PIN q[119]
    DIRECTION OUTPUT ;
    USE SIGNAL ;
    PORT
      LAYER M5 ;
        RECT  23.232 11.688 23.256 11.88 ;
    END
  END q[119]
  PIN q[11]
    DIRECTION OUTPUT ;
    USE SIGNAL ;
    PORT
      LAYER M5 ;
        RECT  2.496 11.688 2.52 11.88 ;
    END
  END q[11]
  PIN q[120]
    DIRECTION OUTPUT ;
    USE SIGNAL ;
    PORT
      LAYER M5 ;
        RECT  23.424 11.688 23.448 11.88 ;
    END
  END q[120]
  PIN q[121]
    DIRECTION OUTPUT ;
    USE SIGNAL ;
    PORT
      LAYER M5 ;
        RECT  23.616 11.688 23.64 11.88 ;
    END
  END q[121]
  PIN q[122]
    DIRECTION OUTPUT ;
    USE SIGNAL ;
    PORT
      LAYER M5 ;
        RECT  23.808 11.688 23.832 11.88 ;
    END
  END q[122]
  PIN q[123]
    DIRECTION OUTPUT ;
    USE SIGNAL ;
    PORT
      LAYER M5 ;
        RECT  24 11.688 24.024 11.88 ;
    END
  END q[123]
  PIN q[124]
    DIRECTION OUTPUT ;
    USE SIGNAL ;
    PORT
      LAYER M5 ;
        RECT  24.192 11.688 24.216 11.88 ;
    END
  END q[124]
  PIN q[125]
    DIRECTION OUTPUT ;
    USE SIGNAL ;
    PORT
      LAYER M5 ;
        RECT  24.384 11.688 24.408 11.88 ;
    END
  END q[125]
  PIN q[126]
    DIRECTION OUTPUT ;
    USE SIGNAL ;
    PORT
      LAYER M5 ;
        RECT  24.576 11.688 24.6 11.88 ;
    END
  END q[126]
  PIN q[127]
    DIRECTION OUTPUT ;
    USE SIGNAL ;
    PORT
      LAYER M5 ;
        RECT  24.768 11.688 24.792 11.88 ;
    END
  END q[127]
  PIN q[128]
    DIRECTION OUTPUT ;
    USE SIGNAL ;
    PORT
      LAYER M5 ;
        RECT  24.96 11.688 24.984 11.88 ;
    END
  END q[128]
  PIN q[129]
    DIRECTION OUTPUT ;
    USE SIGNAL ;
    PORT
      LAYER M5 ;
        RECT  25.152 11.688 25.176 11.88 ;
    END
  END q[129]
  PIN q[12]
    DIRECTION OUTPUT ;
    USE SIGNAL ;
    PORT
      LAYER M5 ;
        RECT  2.688 11.688 2.712 11.88 ;
    END
  END q[12]
  PIN q[130]
    DIRECTION OUTPUT ;
    USE SIGNAL ;
    PORT
      LAYER M5 ;
        RECT  25.344 11.688 25.368 11.88 ;
    END
  END q[130]
  PIN q[131]
    DIRECTION OUTPUT ;
    USE SIGNAL ;
    PORT
      LAYER M5 ;
        RECT  25.536 11.688 25.56 11.88 ;
    END
  END q[131]
  PIN q[132]
    DIRECTION OUTPUT ;
    USE SIGNAL ;
    PORT
      LAYER M5 ;
        RECT  25.728 11.688 25.752 11.88 ;
    END
  END q[132]
  PIN q[133]
    DIRECTION OUTPUT ;
    USE SIGNAL ;
    PORT
      LAYER M5 ;
        RECT  25.92 11.688 25.944 11.88 ;
    END
  END q[133]
  PIN q[134]
    DIRECTION OUTPUT ;
    USE SIGNAL ;
    PORT
      LAYER M5 ;
        RECT  26.112 11.688 26.136 11.88 ;
    END
  END q[134]
  PIN q[135]
    DIRECTION OUTPUT ;
    USE SIGNAL ;
    PORT
      LAYER M5 ;
        RECT  26.304 11.688 26.328 11.88 ;
    END
  END q[135]
  PIN q[136]
    DIRECTION OUTPUT ;
    USE SIGNAL ;
    PORT
      LAYER M5 ;
        RECT  26.496 11.688 26.52 11.88 ;
    END
  END q[136]
  PIN q[137]
    DIRECTION OUTPUT ;
    USE SIGNAL ;
    PORT
      LAYER M5 ;
        RECT  26.688 11.688 26.712 11.88 ;
    END
  END q[137]
  PIN q[138]
    DIRECTION OUTPUT ;
    USE SIGNAL ;
    PORT
      LAYER M5 ;
        RECT  26.88 11.688 26.904 11.88 ;
    END
  END q[138]
  PIN q[139]
    DIRECTION OUTPUT ;
    USE SIGNAL ;
    PORT
      LAYER M5 ;
        RECT  27.072 11.688 27.096 11.88 ;
    END
  END q[139]
  PIN q[13]
    DIRECTION OUTPUT ;
    USE SIGNAL ;
    PORT
      LAYER M5 ;
        RECT  2.88 11.688 2.904 11.88 ;
    END
  END q[13]
  PIN q[140]
    DIRECTION OUTPUT ;
    USE SIGNAL ;
    PORT
      LAYER M5 ;
        RECT  27.264 11.688 27.288 11.88 ;
    END
  END q[140]
  PIN q[141]
    DIRECTION OUTPUT ;
    USE SIGNAL ;
    PORT
      LAYER M5 ;
        RECT  27.456 11.688 27.48 11.88 ;
    END
  END q[141]
  PIN q[142]
    DIRECTION OUTPUT ;
    USE SIGNAL ;
    PORT
      LAYER M5 ;
        RECT  27.648 11.688 27.672 11.88 ;
    END
  END q[142]
  PIN q[143]
    DIRECTION OUTPUT ;
    USE SIGNAL ;
    PORT
      LAYER M5 ;
        RECT  27.84 11.688 27.864 11.88 ;
    END
  END q[143]
  PIN q[144]
    DIRECTION OUTPUT ;
    USE SIGNAL ;
    PORT
      LAYER M5 ;
        RECT  28.032 11.688 28.056 11.88 ;
    END
  END q[144]
  PIN q[145]
    DIRECTION OUTPUT ;
    USE SIGNAL ;
    PORT
      LAYER M5 ;
        RECT  28.224 11.688 28.248 11.88 ;
    END
  END q[145]
  PIN q[146]
    DIRECTION OUTPUT ;
    USE SIGNAL ;
    PORT
      LAYER M5 ;
        RECT  28.416 11.688 28.44 11.88 ;
    END
  END q[146]
  PIN q[147]
    DIRECTION OUTPUT ;
    USE SIGNAL ;
    PORT
      LAYER M5 ;
        RECT  28.608 11.688 28.632 11.88 ;
    END
  END q[147]
  PIN q[148]
    DIRECTION OUTPUT ;
    USE SIGNAL ;
    PORT
      LAYER M5 ;
        RECT  28.8 11.688 28.824 11.88 ;
    END
  END q[148]
  PIN q[149]
    DIRECTION OUTPUT ;
    USE SIGNAL ;
    PORT
      LAYER M5 ;
        RECT  28.992 11.688 29.016 11.88 ;
    END
  END q[149]
  PIN q[14]
    DIRECTION OUTPUT ;
    USE SIGNAL ;
    PORT
      LAYER M5 ;
        RECT  3.072 11.688 3.096 11.88 ;
    END
  END q[14]
  PIN q[150]
    DIRECTION OUTPUT ;
    USE SIGNAL ;
    PORT
      LAYER M5 ;
        RECT  29.184 11.688 29.208 11.88 ;
    END
  END q[150]
  PIN q[151]
    DIRECTION OUTPUT ;
    USE SIGNAL ;
    PORT
      LAYER M5 ;
        RECT  29.376 11.688 29.4 11.88 ;
    END
  END q[151]
  PIN q[152]
    DIRECTION OUTPUT ;
    USE SIGNAL ;
    PORT
      LAYER M5 ;
        RECT  29.568 11.688 29.592 11.88 ;
    END
  END q[152]
  PIN q[153]
    DIRECTION OUTPUT ;
    USE SIGNAL ;
    PORT
      LAYER M5 ;
        RECT  29.76 11.688 29.784 11.88 ;
    END
  END q[153]
  PIN q[154]
    DIRECTION OUTPUT ;
    USE SIGNAL ;
    PORT
      LAYER M5 ;
        RECT  29.952 11.688 29.976 11.88 ;
    END
  END q[154]
  PIN q[155]
    DIRECTION OUTPUT ;
    USE SIGNAL ;
    PORT
      LAYER M5 ;
        RECT  30.144 11.688 30.168 11.88 ;
    END
  END q[155]
  PIN q[156]
    DIRECTION OUTPUT ;
    USE SIGNAL ;
    PORT
      LAYER M5 ;
        RECT  30.336 11.688 30.36 11.88 ;
    END
  END q[156]
  PIN q[157]
    DIRECTION OUTPUT ;
    USE SIGNAL ;
    PORT
      LAYER M5 ;
        RECT  30.528 11.688 30.552 11.88 ;
    END
  END q[157]
  PIN q[158]
    DIRECTION OUTPUT ;
    USE SIGNAL ;
    PORT
      LAYER M5 ;
        RECT  30.72 11.688 30.744 11.88 ;
    END
  END q[158]
  PIN q[159]
    DIRECTION OUTPUT ;
    USE SIGNAL ;
    PORT
      LAYER M5 ;
        RECT  30.912 11.688 30.936 11.88 ;
    END
  END q[159]
  PIN q[15]
    DIRECTION OUTPUT ;
    USE SIGNAL ;
    PORT
      LAYER M5 ;
        RECT  3.264 11.688 3.288 11.88 ;
    END
  END q[15]
  PIN q[160]
    DIRECTION OUTPUT ;
    USE SIGNAL ;
    PORT
      LAYER M5 ;
        RECT  31.104 11.688 31.128 11.88 ;
    END
  END q[160]
  PIN q[161]
    DIRECTION OUTPUT ;
    USE SIGNAL ;
    PORT
      LAYER M5 ;
        RECT  31.296 11.688 31.32 11.88 ;
    END
  END q[161]
  PIN q[162]
    DIRECTION OUTPUT ;
    USE SIGNAL ;
    PORT
      LAYER M5 ;
        RECT  31.488 11.688 31.512 11.88 ;
    END
  END q[162]
  PIN q[163]
    DIRECTION OUTPUT ;
    USE SIGNAL ;
    PORT
      LAYER M5 ;
        RECT  31.68 11.688 31.704 11.88 ;
    END
  END q[163]
  PIN q[164]
    DIRECTION OUTPUT ;
    USE SIGNAL ;
    PORT
      LAYER M5 ;
        RECT  31.872 11.688 31.896 11.88 ;
    END
  END q[164]
  PIN q[165]
    DIRECTION OUTPUT ;
    USE SIGNAL ;
    PORT
      LAYER M5 ;
        RECT  32.064 11.688 32.088 11.88 ;
    END
  END q[165]
  PIN q[166]
    DIRECTION OUTPUT ;
    USE SIGNAL ;
    PORT
      LAYER M5 ;
        RECT  32.256 11.688 32.28 11.88 ;
    END
  END q[166]
  PIN q[167]
    DIRECTION OUTPUT ;
    USE SIGNAL ;
    PORT
      LAYER M5 ;
        RECT  32.448 11.688 32.472 11.88 ;
    END
  END q[167]
  PIN q[168]
    DIRECTION OUTPUT ;
    USE SIGNAL ;
    PORT
      LAYER M5 ;
        RECT  32.64 11.688 32.664 11.88 ;
    END
  END q[168]
  PIN q[169]
    DIRECTION OUTPUT ;
    USE SIGNAL ;
    PORT
      LAYER M5 ;
        RECT  32.832 11.688 32.856 11.88 ;
    END
  END q[169]
  PIN q[16]
    DIRECTION OUTPUT ;
    USE SIGNAL ;
    PORT
      LAYER M5 ;
        RECT  3.456 11.688 3.48 11.88 ;
    END
  END q[16]
  PIN q[170]
    DIRECTION OUTPUT ;
    USE SIGNAL ;
    PORT
      LAYER M5 ;
        RECT  33.024 11.688 33.048 11.88 ;
    END
  END q[170]
  PIN q[171]
    DIRECTION OUTPUT ;
    USE SIGNAL ;
    PORT
      LAYER M5 ;
        RECT  33.216 11.688 33.24 11.88 ;
    END
  END q[171]
  PIN q[172]
    DIRECTION OUTPUT ;
    USE SIGNAL ;
    PORT
      LAYER M5 ;
        RECT  33.408 11.688 33.432 11.88 ;
    END
  END q[172]
  PIN q[173]
    DIRECTION OUTPUT ;
    USE SIGNAL ;
    PORT
      LAYER M5 ;
        RECT  33.6 11.688 33.624 11.88 ;
    END
  END q[173]
  PIN q[174]
    DIRECTION OUTPUT ;
    USE SIGNAL ;
    PORT
      LAYER M5 ;
        RECT  33.792 11.688 33.816 11.88 ;
    END
  END q[174]
  PIN q[175]
    DIRECTION OUTPUT ;
    USE SIGNAL ;
    PORT
      LAYER M5 ;
        RECT  33.984 11.688 34.008 11.88 ;
    END
  END q[175]
  PIN q[176]
    DIRECTION OUTPUT ;
    USE SIGNAL ;
    PORT
      LAYER M5 ;
        RECT  34.176 11.688 34.2 11.88 ;
    END
  END q[176]
  PIN q[177]
    DIRECTION OUTPUT ;
    USE SIGNAL ;
    PORT
      LAYER M5 ;
        RECT  34.368 11.688 34.392 11.88 ;
    END
  END q[177]
  PIN q[178]
    DIRECTION OUTPUT ;
    USE SIGNAL ;
    PORT
      LAYER M5 ;
        RECT  34.56 11.688 34.584 11.88 ;
    END
  END q[178]
  PIN q[179]
    DIRECTION OUTPUT ;
    USE SIGNAL ;
    PORT
      LAYER M5 ;
        RECT  34.752 11.688 34.776 11.88 ;
    END
  END q[179]
  PIN q[17]
    DIRECTION OUTPUT ;
    USE SIGNAL ;
    PORT
      LAYER M5 ;
        RECT  3.648 11.688 3.672 11.88 ;
    END
  END q[17]
  PIN q[180]
    DIRECTION OUTPUT ;
    USE SIGNAL ;
    PORT
      LAYER M5 ;
        RECT  34.944 11.688 34.968 11.88 ;
    END
  END q[180]
  PIN q[181]
    DIRECTION OUTPUT ;
    USE SIGNAL ;
    PORT
      LAYER M5 ;
        RECT  35.136 11.688 35.16 11.88 ;
    END
  END q[181]
  PIN q[182]
    DIRECTION OUTPUT ;
    USE SIGNAL ;
    PORT
      LAYER M5 ;
        RECT  35.328 11.688 35.352 11.88 ;
    END
  END q[182]
  PIN q[183]
    DIRECTION OUTPUT ;
    USE SIGNAL ;
    PORT
      LAYER M5 ;
        RECT  35.52 11.688 35.544 11.88 ;
    END
  END q[183]
  PIN q[184]
    DIRECTION OUTPUT ;
    USE SIGNAL ;
    PORT
      LAYER M5 ;
        RECT  35.712 11.688 35.736 11.88 ;
    END
  END q[184]
  PIN q[185]
    DIRECTION OUTPUT ;
    USE SIGNAL ;
    PORT
      LAYER M5 ;
        RECT  35.904 11.688 35.928 11.88 ;
    END
  END q[185]
  PIN q[186]
    DIRECTION OUTPUT ;
    USE SIGNAL ;
    PORT
      LAYER M5 ;
        RECT  36.096 11.688 36.12 11.88 ;
    END
  END q[186]
  PIN q[187]
    DIRECTION OUTPUT ;
    USE SIGNAL ;
    PORT
      LAYER M5 ;
        RECT  36.288 11.688 36.312 11.88 ;
    END
  END q[187]
  PIN q[188]
    DIRECTION OUTPUT ;
    USE SIGNAL ;
    PORT
      LAYER M5 ;
        RECT  36.48 11.688 36.504 11.88 ;
    END
  END q[188]
  PIN q[189]
    DIRECTION OUTPUT ;
    USE SIGNAL ;
    PORT
      LAYER M5 ;
        RECT  36.672 11.688 36.696 11.88 ;
    END
  END q[189]
  PIN q[18]
    DIRECTION OUTPUT ;
    USE SIGNAL ;
    PORT
      LAYER M5 ;
        RECT  3.84 11.688 3.864 11.88 ;
    END
  END q[18]
  PIN q[190]
    DIRECTION OUTPUT ;
    USE SIGNAL ;
    PORT
      LAYER M5 ;
        RECT  36.864 11.688 36.888 11.88 ;
    END
  END q[190]
  PIN q[191]
    DIRECTION OUTPUT ;
    USE SIGNAL ;
    PORT
      LAYER M5 ;
        RECT  37.056 11.688 37.08 11.88 ;
    END
  END q[191]
  PIN q[192]
    DIRECTION OUTPUT ;
    USE SIGNAL ;
    PORT
      LAYER M5 ;
        RECT  37.248 11.688 37.272 11.88 ;
    END
  END q[192]
  PIN q[193]
    DIRECTION OUTPUT ;
    USE SIGNAL ;
    PORT
      LAYER M5 ;
        RECT  37.44 11.688 37.464 11.88 ;
    END
  END q[193]
  PIN q[194]
    DIRECTION OUTPUT ;
    USE SIGNAL ;
    PORT
      LAYER M5 ;
        RECT  37.632 11.688 37.656 11.88 ;
    END
  END q[194]
  PIN q[195]
    DIRECTION OUTPUT ;
    USE SIGNAL ;
    PORT
      LAYER M5 ;
        RECT  37.824 11.688 37.848 11.88 ;
    END
  END q[195]
  PIN q[196]
    DIRECTION OUTPUT ;
    USE SIGNAL ;
    PORT
      LAYER M5 ;
        RECT  38.016 11.688 38.04 11.88 ;
    END
  END q[196]
  PIN q[197]
    DIRECTION OUTPUT ;
    USE SIGNAL ;
    PORT
      LAYER M5 ;
        RECT  38.208 11.688 38.232 11.88 ;
    END
  END q[197]
  PIN q[198]
    DIRECTION OUTPUT ;
    USE SIGNAL ;
    PORT
      LAYER M5 ;
        RECT  38.4 11.688 38.424 11.88 ;
    END
  END q[198]
  PIN q[199]
    DIRECTION OUTPUT ;
    USE SIGNAL ;
    PORT
      LAYER M5 ;
        RECT  38.592 11.688 38.616 11.88 ;
    END
  END q[199]
  PIN q[19]
    DIRECTION OUTPUT ;
    USE SIGNAL ;
    PORT
      LAYER M5 ;
        RECT  4.032 11.688 4.056 11.88 ;
    END
  END q[19]
  PIN q[1]
    DIRECTION OUTPUT ;
    USE SIGNAL ;
    PORT
      LAYER M5 ;
        RECT  0.576 11.688 0.6 11.88 ;
    END
  END q[1]
  PIN q[200]
    DIRECTION OUTPUT ;
    USE SIGNAL ;
    PORT
      LAYER M5 ;
        RECT  38.784 11.688 38.808 11.88 ;
    END
  END q[200]
  PIN q[201]
    DIRECTION OUTPUT ;
    USE SIGNAL ;
    PORT
      LAYER M5 ;
        RECT  38.976 11.688 39 11.88 ;
    END
  END q[201]
  PIN q[202]
    DIRECTION OUTPUT ;
    USE SIGNAL ;
    PORT
      LAYER M5 ;
        RECT  39.168 11.688 39.192 11.88 ;
    END
  END q[202]
  PIN q[203]
    DIRECTION OUTPUT ;
    USE SIGNAL ;
    PORT
      LAYER M5 ;
        RECT  39.36 11.688 39.384 11.88 ;
    END
  END q[203]
  PIN q[204]
    DIRECTION OUTPUT ;
    USE SIGNAL ;
    PORT
      LAYER M5 ;
        RECT  39.552 11.688 39.576 11.88 ;
    END
  END q[204]
  PIN q[205]
    DIRECTION OUTPUT ;
    USE SIGNAL ;
    PORT
      LAYER M5 ;
        RECT  39.744 11.688 39.768 11.88 ;
    END
  END q[205]
  PIN q[206]
    DIRECTION OUTPUT ;
    USE SIGNAL ;
    PORT
      LAYER M5 ;
        RECT  39.936 11.688 39.96 11.88 ;
    END
  END q[206]
  PIN q[207]
    DIRECTION OUTPUT ;
    USE SIGNAL ;
    PORT
      LAYER M5 ;
        RECT  40.128 11.688 40.152 11.88 ;
    END
  END q[207]
  PIN q[208]
    DIRECTION OUTPUT ;
    USE SIGNAL ;
    PORT
      LAYER M5 ;
        RECT  40.32 11.688 40.344 11.88 ;
    END
  END q[208]
  PIN q[209]
    DIRECTION OUTPUT ;
    USE SIGNAL ;
    PORT
      LAYER M5 ;
        RECT  40.512 11.688 40.536 11.88 ;
    END
  END q[209]
  PIN q[20]
    DIRECTION OUTPUT ;
    USE SIGNAL ;
    PORT
      LAYER M5 ;
        RECT  4.224 11.688 4.248 11.88 ;
    END
  END q[20]
  PIN q[210]
    DIRECTION OUTPUT ;
    USE SIGNAL ;
    PORT
      LAYER M5 ;
        RECT  40.704 11.688 40.728 11.88 ;
    END
  END q[210]
  PIN q[211]
    DIRECTION OUTPUT ;
    USE SIGNAL ;
    PORT
      LAYER M5 ;
        RECT  40.896 11.688 40.92 11.88 ;
    END
  END q[211]
  PIN q[212]
    DIRECTION OUTPUT ;
    USE SIGNAL ;
    PORT
      LAYER M5 ;
        RECT  41.088 11.688 41.112 11.88 ;
    END
  END q[212]
  PIN q[213]
    DIRECTION OUTPUT ;
    USE SIGNAL ;
    PORT
      LAYER M5 ;
        RECT  41.28 11.688 41.304 11.88 ;
    END
  END q[213]
  PIN q[214]
    DIRECTION OUTPUT ;
    USE SIGNAL ;
    PORT
      LAYER M5 ;
        RECT  41.472 11.688 41.496 11.88 ;
    END
  END q[214]
  PIN q[215]
    DIRECTION OUTPUT ;
    USE SIGNAL ;
    PORT
      LAYER M5 ;
        RECT  41.664 11.688 41.688 11.88 ;
    END
  END q[215]
  PIN q[216]
    DIRECTION OUTPUT ;
    USE SIGNAL ;
    PORT
      LAYER M5 ;
        RECT  41.856 11.688 41.88 11.88 ;
    END
  END q[216]
  PIN q[217]
    DIRECTION OUTPUT ;
    USE SIGNAL ;
    PORT
      LAYER M5 ;
        RECT  42.048 11.688 42.072 11.88 ;
    END
  END q[217]
  PIN q[218]
    DIRECTION OUTPUT ;
    USE SIGNAL ;
    PORT
      LAYER M5 ;
        RECT  42.24 11.688 42.264 11.88 ;
    END
  END q[218]
  PIN q[219]
    DIRECTION OUTPUT ;
    USE SIGNAL ;
    PORT
      LAYER M5 ;
        RECT  42.432 11.688 42.456 11.88 ;
    END
  END q[219]
  PIN q[21]
    DIRECTION OUTPUT ;
    USE SIGNAL ;
    PORT
      LAYER M5 ;
        RECT  4.416 11.688 4.44 11.88 ;
    END
  END q[21]
  PIN q[220]
    DIRECTION OUTPUT ;
    USE SIGNAL ;
    PORT
      LAYER M5 ;
        RECT  42.624 11.688 42.648 11.88 ;
    END
  END q[220]
  PIN q[221]
    DIRECTION OUTPUT ;
    USE SIGNAL ;
    PORT
      LAYER M5 ;
        RECT  42.816 11.688 42.84 11.88 ;
    END
  END q[221]
  PIN q[222]
    DIRECTION OUTPUT ;
    USE SIGNAL ;
    PORT
      LAYER M5 ;
        RECT  43.008 11.688 43.032 11.88 ;
    END
  END q[222]
  PIN q[223]
    DIRECTION OUTPUT ;
    USE SIGNAL ;
    PORT
      LAYER M5 ;
        RECT  43.2 11.688 43.224 11.88 ;
    END
  END q[223]
  PIN q[224]
    DIRECTION OUTPUT ;
    USE SIGNAL ;
    PORT
      LAYER M5 ;
        RECT  43.392 11.688 43.416 11.88 ;
    END
  END q[224]
  PIN q[225]
    DIRECTION OUTPUT ;
    USE SIGNAL ;
    PORT
      LAYER M5 ;
        RECT  43.584 11.688 43.608 11.88 ;
    END
  END q[225]
  PIN q[226]
    DIRECTION OUTPUT ;
    USE SIGNAL ;
    PORT
      LAYER M5 ;
        RECT  43.776 11.688 43.8 11.88 ;
    END
  END q[226]
  PIN q[227]
    DIRECTION OUTPUT ;
    USE SIGNAL ;
    PORT
      LAYER M5 ;
        RECT  43.968 11.688 43.992 11.88 ;
    END
  END q[227]
  PIN q[228]
    DIRECTION OUTPUT ;
    USE SIGNAL ;
    PORT
      LAYER M5 ;
        RECT  44.16 11.688 44.184 11.88 ;
    END
  END q[228]
  PIN q[229]
    DIRECTION OUTPUT ;
    USE SIGNAL ;
    PORT
      LAYER M5 ;
        RECT  44.352 11.688 44.376 11.88 ;
    END
  END q[229]
  PIN q[22]
    DIRECTION OUTPUT ;
    USE SIGNAL ;
    PORT
      LAYER M5 ;
        RECT  4.608 11.688 4.632 11.88 ;
    END
  END q[22]
  PIN q[230]
    DIRECTION OUTPUT ;
    USE SIGNAL ;
    PORT
      LAYER M5 ;
        RECT  44.544 11.688 44.568 11.88 ;
    END
  END q[230]
  PIN q[231]
    DIRECTION OUTPUT ;
    USE SIGNAL ;
    PORT
      LAYER M5 ;
        RECT  44.736 11.688 44.76 11.88 ;
    END
  END q[231]
  PIN q[232]
    DIRECTION OUTPUT ;
    USE SIGNAL ;
    PORT
      LAYER M5 ;
        RECT  44.928 11.688 44.952 11.88 ;
    END
  END q[232]
  PIN q[233]
    DIRECTION OUTPUT ;
    USE SIGNAL ;
    PORT
      LAYER M5 ;
        RECT  45.12 11.688 45.144 11.88 ;
    END
  END q[233]
  PIN q[234]
    DIRECTION OUTPUT ;
    USE SIGNAL ;
    PORT
      LAYER M5 ;
        RECT  45.312 11.688 45.336 11.88 ;
    END
  END q[234]
  PIN q[235]
    DIRECTION OUTPUT ;
    USE SIGNAL ;
    PORT
      LAYER M5 ;
        RECT  45.504 11.688 45.528 11.88 ;
    END
  END q[235]
  PIN q[236]
    DIRECTION OUTPUT ;
    USE SIGNAL ;
    PORT
      LAYER M5 ;
        RECT  45.696 11.688 45.72 11.88 ;
    END
  END q[236]
  PIN q[237]
    DIRECTION OUTPUT ;
    USE SIGNAL ;
    PORT
      LAYER M5 ;
        RECT  45.888 11.688 45.912 11.88 ;
    END
  END q[237]
  PIN q[238]
    DIRECTION OUTPUT ;
    USE SIGNAL ;
    PORT
      LAYER M5 ;
        RECT  46.08 11.688 46.104 11.88 ;
    END
  END q[238]
  PIN q[239]
    DIRECTION OUTPUT ;
    USE SIGNAL ;
    PORT
      LAYER M5 ;
        RECT  46.272 11.688 46.296 11.88 ;
    END
  END q[239]
  PIN q[23]
    DIRECTION OUTPUT ;
    USE SIGNAL ;
    PORT
      LAYER M5 ;
        RECT  4.8 11.688 4.824 11.88 ;
    END
  END q[23]
  PIN q[240]
    DIRECTION OUTPUT ;
    USE SIGNAL ;
    PORT
      LAYER M5 ;
        RECT  46.464 11.688 46.488 11.88 ;
    END
  END q[240]
  PIN q[241]
    DIRECTION OUTPUT ;
    USE SIGNAL ;
    PORT
      LAYER M5 ;
        RECT  46.656 11.688 46.68 11.88 ;
    END
  END q[241]
  PIN q[242]
    DIRECTION OUTPUT ;
    USE SIGNAL ;
    PORT
      LAYER M5 ;
        RECT  46.848 11.688 46.872 11.88 ;
    END
  END q[242]
  PIN q[243]
    DIRECTION OUTPUT ;
    USE SIGNAL ;
    PORT
      LAYER M5 ;
        RECT  47.04 11.688 47.064 11.88 ;
    END
  END q[243]
  PIN q[244]
    DIRECTION OUTPUT ;
    USE SIGNAL ;
    PORT
      LAYER M5 ;
        RECT  47.232 11.688 47.256 11.88 ;
    END
  END q[244]
  PIN q[245]
    DIRECTION OUTPUT ;
    USE SIGNAL ;
    PORT
      LAYER M5 ;
        RECT  47.424 11.688 47.448 11.88 ;
    END
  END q[245]
  PIN q[246]
    DIRECTION OUTPUT ;
    USE SIGNAL ;
    PORT
      LAYER M5 ;
        RECT  47.616 11.688 47.64 11.88 ;
    END
  END q[246]
  PIN q[247]
    DIRECTION OUTPUT ;
    USE SIGNAL ;
    PORT
      LAYER M5 ;
        RECT  47.808 11.688 47.832 11.88 ;
    END
  END q[247]
  PIN q[248]
    DIRECTION OUTPUT ;
    USE SIGNAL ;
    PORT
      LAYER M5 ;
        RECT  48 11.688 48.024 11.88 ;
    END
  END q[248]
  PIN q[249]
    DIRECTION OUTPUT ;
    USE SIGNAL ;
    PORT
      LAYER M5 ;
        RECT  48.192 11.688 48.216 11.88 ;
    END
  END q[249]
  PIN q[24]
    DIRECTION OUTPUT ;
    USE SIGNAL ;
    PORT
      LAYER M5 ;
        RECT  4.992 11.688 5.016 11.88 ;
    END
  END q[24]
  PIN q[250]
    DIRECTION OUTPUT ;
    USE SIGNAL ;
    PORT
      LAYER M5 ;
        RECT  48.384 11.688 48.408 11.88 ;
    END
  END q[250]
  PIN q[251]
    DIRECTION OUTPUT ;
    USE SIGNAL ;
    PORT
      LAYER M5 ;
        RECT  48.576 11.688 48.6 11.88 ;
    END
  END q[251]
  PIN q[252]
    DIRECTION OUTPUT ;
    USE SIGNAL ;
    PORT
      LAYER M5 ;
        RECT  48.768 11.688 48.792 11.88 ;
    END
  END q[252]
  PIN q[253]
    DIRECTION OUTPUT ;
    USE SIGNAL ;
    PORT
      LAYER M5 ;
        RECT  48.96 11.688 48.984 11.88 ;
    END
  END q[253]
  PIN q[254]
    DIRECTION OUTPUT ;
    USE SIGNAL ;
    PORT
      LAYER M5 ;
        RECT  49.152 11.688 49.176 11.88 ;
    END
  END q[254]
  PIN q[255]
    DIRECTION OUTPUT ;
    USE SIGNAL ;
    PORT
      LAYER M5 ;
        RECT  49.344 11.688 49.368 11.88 ;
    END
  END q[255]
  PIN q[256]
    DIRECTION OUTPUT ;
    USE SIGNAL ;
    PORT
      LAYER M5 ;
        RECT  49.536 11.688 49.56 11.88 ;
    END
  END q[256]
  PIN q[257]
    DIRECTION OUTPUT ;
    USE SIGNAL ;
    PORT
      LAYER M5 ;
        RECT  49.728 11.688 49.752 11.88 ;
    END
  END q[257]
  PIN q[258]
    DIRECTION OUTPUT ;
    USE SIGNAL ;
    PORT
      LAYER M5 ;
        RECT  49.92 11.688 49.944 11.88 ;
    END
  END q[258]
  PIN q[259]
    DIRECTION OUTPUT ;
    USE SIGNAL ;
    PORT
      LAYER M5 ;
        RECT  50.112 11.688 50.136 11.88 ;
    END
  END q[259]
  PIN q[25]
    DIRECTION OUTPUT ;
    USE SIGNAL ;
    PORT
      LAYER M5 ;
        RECT  5.184 11.688 5.208 11.88 ;
    END
  END q[25]
  PIN q[260]
    DIRECTION OUTPUT ;
    USE SIGNAL ;
    PORT
      LAYER M5 ;
        RECT  50.304 11.688 50.328 11.88 ;
    END
  END q[260]
  PIN q[261]
    DIRECTION OUTPUT ;
    USE SIGNAL ;
    PORT
      LAYER M5 ;
        RECT  50.496 11.688 50.52 11.88 ;
    END
  END q[261]
  PIN q[262]
    DIRECTION OUTPUT ;
    USE SIGNAL ;
    PORT
      LAYER M5 ;
        RECT  50.688 11.688 50.712 11.88 ;
    END
  END q[262]
  PIN q[263]
    DIRECTION OUTPUT ;
    USE SIGNAL ;
    PORT
      LAYER M5 ;
        RECT  50.88 11.688 50.904 11.88 ;
    END
  END q[263]
  PIN q[264]
    DIRECTION OUTPUT ;
    USE SIGNAL ;
    PORT
      LAYER M5 ;
        RECT  51.072 11.688 51.096 11.88 ;
    END
  END q[264]
  PIN q[265]
    DIRECTION OUTPUT ;
    USE SIGNAL ;
    PORT
      LAYER M5 ;
        RECT  51.264 11.688 51.288 11.88 ;
    END
  END q[265]
  PIN q[266]
    DIRECTION OUTPUT ;
    USE SIGNAL ;
    PORT
      LAYER M5 ;
        RECT  51.456 11.688 51.48 11.88 ;
    END
  END q[266]
  PIN q[267]
    DIRECTION OUTPUT ;
    USE SIGNAL ;
    PORT
      LAYER M5 ;
        RECT  51.648 11.688 51.672 11.88 ;
    END
  END q[267]
  PIN q[268]
    DIRECTION OUTPUT ;
    USE SIGNAL ;
    PORT
      LAYER M5 ;
        RECT  51.84 11.688 51.864 11.88 ;
    END
  END q[268]
  PIN q[269]
    DIRECTION OUTPUT ;
    USE SIGNAL ;
    PORT
      LAYER M5 ;
        RECT  52.032 11.688 52.056 11.88 ;
    END
  END q[269]
  PIN q[26]
    DIRECTION OUTPUT ;
    USE SIGNAL ;
    PORT
      LAYER M5 ;
        RECT  5.376 11.688 5.4 11.88 ;
    END
  END q[26]
  PIN q[270]
    DIRECTION OUTPUT ;
    USE SIGNAL ;
    PORT
      LAYER M5 ;
        RECT  52.224 11.688 52.248 11.88 ;
    END
  END q[270]
  PIN q[271]
    DIRECTION OUTPUT ;
    USE SIGNAL ;
    PORT
      LAYER M5 ;
        RECT  52.416 11.688 52.44 11.88 ;
    END
  END q[271]
  PIN q[272]
    DIRECTION OUTPUT ;
    USE SIGNAL ;
    PORT
      LAYER M5 ;
        RECT  52.608 11.688 52.632 11.88 ;
    END
  END q[272]
  PIN q[273]
    DIRECTION OUTPUT ;
    USE SIGNAL ;
    PORT
      LAYER M5 ;
        RECT  52.8 11.688 52.824 11.88 ;
    END
  END q[273]
  PIN q[274]
    DIRECTION OUTPUT ;
    USE SIGNAL ;
    PORT
      LAYER M5 ;
        RECT  52.992 11.688 53.016 11.88 ;
    END
  END q[274]
  PIN q[275]
    DIRECTION OUTPUT ;
    USE SIGNAL ;
    PORT
      LAYER M5 ;
        RECT  53.184 11.688 53.208 11.88 ;
    END
  END q[275]
  PIN q[276]
    DIRECTION OUTPUT ;
    USE SIGNAL ;
    PORT
      LAYER M5 ;
        RECT  53.376 11.688 53.4 11.88 ;
    END
  END q[276]
  PIN q[277]
    DIRECTION OUTPUT ;
    USE SIGNAL ;
    PORT
      LAYER M5 ;
        RECT  53.568 11.688 53.592 11.88 ;
    END
  END q[277]
  PIN q[278]
    DIRECTION OUTPUT ;
    USE SIGNAL ;
    PORT
      LAYER M5 ;
        RECT  53.76 11.688 53.784 11.88 ;
    END
  END q[278]
  PIN q[279]
    DIRECTION OUTPUT ;
    USE SIGNAL ;
    PORT
      LAYER M5 ;
        RECT  53.952 11.688 53.976 11.88 ;
    END
  END q[279]
  PIN q[27]
    DIRECTION OUTPUT ;
    USE SIGNAL ;
    PORT
      LAYER M5 ;
        RECT  5.568 11.688 5.592 11.88 ;
    END
  END q[27]
  PIN q[280]
    DIRECTION OUTPUT ;
    USE SIGNAL ;
    PORT
      LAYER M5 ;
        RECT  54.144 11.688 54.168 11.88 ;
    END
  END q[280]
  PIN q[281]
    DIRECTION OUTPUT ;
    USE SIGNAL ;
    PORT
      LAYER M5 ;
        RECT  54.336 11.688 54.36 11.88 ;
    END
  END q[281]
  PIN q[282]
    DIRECTION OUTPUT ;
    USE SIGNAL ;
    PORT
      LAYER M5 ;
        RECT  54.528 11.688 54.552 11.88 ;
    END
  END q[282]
  PIN q[283]
    DIRECTION OUTPUT ;
    USE SIGNAL ;
    PORT
      LAYER M5 ;
        RECT  54.72 11.688 54.744 11.88 ;
    END
  END q[283]
  PIN q[284]
    DIRECTION OUTPUT ;
    USE SIGNAL ;
    PORT
      LAYER M5 ;
        RECT  54.912 11.688 54.936 11.88 ;
    END
  END q[284]
  PIN q[285]
    DIRECTION OUTPUT ;
    USE SIGNAL ;
    PORT
      LAYER M5 ;
        RECT  55.104 11.688 55.128 11.88 ;
    END
  END q[285]
  PIN q[286]
    DIRECTION OUTPUT ;
    USE SIGNAL ;
    PORT
      LAYER M5 ;
        RECT  55.296 11.688 55.32 11.88 ;
    END
  END q[286]
  PIN q[287]
    DIRECTION OUTPUT ;
    USE SIGNAL ;
    PORT
      LAYER M5 ;
        RECT  55.488 11.688 55.512 11.88 ;
    END
  END q[287]
  PIN q[288]
    DIRECTION OUTPUT ;
    USE SIGNAL ;
    PORT
      LAYER M5 ;
        RECT  55.68 11.688 55.704 11.88 ;
    END
  END q[288]
  PIN q[289]
    DIRECTION OUTPUT ;
    USE SIGNAL ;
    PORT
      LAYER M5 ;
        RECT  55.872 11.688 55.896 11.88 ;
    END
  END q[289]
  PIN q[28]
    DIRECTION OUTPUT ;
    USE SIGNAL ;
    PORT
      LAYER M5 ;
        RECT  5.76 11.688 5.784 11.88 ;
    END
  END q[28]
  PIN q[290]
    DIRECTION OUTPUT ;
    USE SIGNAL ;
    PORT
      LAYER M5 ;
        RECT  56.064 11.688 56.088 11.88 ;
    END
  END q[290]
  PIN q[291]
    DIRECTION OUTPUT ;
    USE SIGNAL ;
    PORT
      LAYER M5 ;
        RECT  56.256 11.688 56.28 11.88 ;
    END
  END q[291]
  PIN q[292]
    DIRECTION OUTPUT ;
    USE SIGNAL ;
    PORT
      LAYER M5 ;
        RECT  56.448 11.688 56.472 11.88 ;
    END
  END q[292]
  PIN q[293]
    DIRECTION OUTPUT ;
    USE SIGNAL ;
    PORT
      LAYER M5 ;
        RECT  56.64 11.688 56.664 11.88 ;
    END
  END q[293]
  PIN q[294]
    DIRECTION OUTPUT ;
    USE SIGNAL ;
    PORT
      LAYER M5 ;
        RECT  56.832 11.688 56.856 11.88 ;
    END
  END q[294]
  PIN q[295]
    DIRECTION OUTPUT ;
    USE SIGNAL ;
    PORT
      LAYER M5 ;
        RECT  57.024 11.688 57.048 11.88 ;
    END
  END q[295]
  PIN q[296]
    DIRECTION OUTPUT ;
    USE SIGNAL ;
    PORT
      LAYER M5 ;
        RECT  57.216 11.688 57.24 11.88 ;
    END
  END q[296]
  PIN q[297]
    DIRECTION OUTPUT ;
    USE SIGNAL ;
    PORT
      LAYER M5 ;
        RECT  57.408 11.688 57.432 11.88 ;
    END
  END q[297]
  PIN q[298]
    DIRECTION OUTPUT ;
    USE SIGNAL ;
    PORT
      LAYER M5 ;
        RECT  57.6 11.688 57.624 11.88 ;
    END
  END q[298]
  PIN q[299]
    DIRECTION OUTPUT ;
    USE SIGNAL ;
    PORT
      LAYER M5 ;
        RECT  57.792 11.688 57.816 11.88 ;
    END
  END q[299]
  PIN q[29]
    DIRECTION OUTPUT ;
    USE SIGNAL ;
    PORT
      LAYER M5 ;
        RECT  5.952 11.688 5.976 11.88 ;
    END
  END q[29]
  PIN q[2]
    DIRECTION OUTPUT ;
    USE SIGNAL ;
    PORT
      LAYER M5 ;
        RECT  0.768 11.688 0.792 11.88 ;
    END
  END q[2]
  PIN q[300]
    DIRECTION OUTPUT ;
    USE SIGNAL ;
    PORT
      LAYER M5 ;
        RECT  57.984 11.688 58.008 11.88 ;
    END
  END q[300]
  PIN q[301]
    DIRECTION OUTPUT ;
    USE SIGNAL ;
    PORT
      LAYER M5 ;
        RECT  58.176 11.688 58.2 11.88 ;
    END
  END q[301]
  PIN q[302]
    DIRECTION OUTPUT ;
    USE SIGNAL ;
    PORT
      LAYER M5 ;
        RECT  58.368 11.688 58.392 11.88 ;
    END
  END q[302]
  PIN q[303]
    DIRECTION OUTPUT ;
    USE SIGNAL ;
    PORT
      LAYER M5 ;
        RECT  58.56 11.688 58.584 11.88 ;
    END
  END q[303]
  PIN q[304]
    DIRECTION OUTPUT ;
    USE SIGNAL ;
    PORT
      LAYER M5 ;
        RECT  58.752 11.688 58.776 11.88 ;
    END
  END q[304]
  PIN q[305]
    DIRECTION OUTPUT ;
    USE SIGNAL ;
    PORT
      LAYER M5 ;
        RECT  58.944 11.688 58.968 11.88 ;
    END
  END q[305]
  PIN q[306]
    DIRECTION OUTPUT ;
    USE SIGNAL ;
    PORT
      LAYER M5 ;
        RECT  59.136 11.688 59.16 11.88 ;
    END
  END q[306]
  PIN q[307]
    DIRECTION OUTPUT ;
    USE SIGNAL ;
    PORT
      LAYER M5 ;
        RECT  59.328 11.688 59.352 11.88 ;
    END
  END q[307]
  PIN q[308]
    DIRECTION OUTPUT ;
    USE SIGNAL ;
    PORT
      LAYER M5 ;
        RECT  59.52 11.688 59.544 11.88 ;
    END
  END q[308]
  PIN q[309]
    DIRECTION OUTPUT ;
    USE SIGNAL ;
    PORT
      LAYER M5 ;
        RECT  59.712 11.688 59.736 11.88 ;
    END
  END q[309]
  PIN q[30]
    DIRECTION OUTPUT ;
    USE SIGNAL ;
    PORT
      LAYER M5 ;
        RECT  6.144 11.688 6.168 11.88 ;
    END
  END q[30]
  PIN q[310]
    DIRECTION OUTPUT ;
    USE SIGNAL ;
    PORT
      LAYER M5 ;
        RECT  59.904 11.688 59.928 11.88 ;
    END
  END q[310]
  PIN q[311]
    DIRECTION OUTPUT ;
    USE SIGNAL ;
    PORT
      LAYER M5 ;
        RECT  60.096 11.688 60.12 11.88 ;
    END
  END q[311]
  PIN q[312]
    DIRECTION OUTPUT ;
    USE SIGNAL ;
    PORT
      LAYER M5 ;
        RECT  60.288 11.688 60.312 11.88 ;
    END
  END q[312]
  PIN q[313]
    DIRECTION OUTPUT ;
    USE SIGNAL ;
    PORT
      LAYER M5 ;
        RECT  60.48 11.688 60.504 11.88 ;
    END
  END q[313]
  PIN q[314]
    DIRECTION OUTPUT ;
    USE SIGNAL ;
    PORT
      LAYER M5 ;
        RECT  60.672 11.688 60.696 11.88 ;
    END
  END q[314]
  PIN q[315]
    DIRECTION OUTPUT ;
    USE SIGNAL ;
    PORT
      LAYER M5 ;
        RECT  60.864 11.688 60.888 11.88 ;
    END
  END q[315]
  PIN q[316]
    DIRECTION OUTPUT ;
    USE SIGNAL ;
    PORT
      LAYER M5 ;
        RECT  61.056 11.688 61.08 11.88 ;
    END
  END q[316]
  PIN q[317]
    DIRECTION OUTPUT ;
    USE SIGNAL ;
    PORT
      LAYER M5 ;
        RECT  61.248 11.688 61.272 11.88 ;
    END
  END q[317]
  PIN q[318]
    DIRECTION OUTPUT ;
    USE SIGNAL ;
    PORT
      LAYER M5 ;
        RECT  61.44 11.688 61.464 11.88 ;
    END
  END q[318]
  PIN q[319]
    DIRECTION OUTPUT ;
    USE SIGNAL ;
    PORT
      LAYER M5 ;
        RECT  61.632 11.688 61.656 11.88 ;
    END
  END q[319]
  PIN q[31]
    DIRECTION OUTPUT ;
    USE SIGNAL ;
    PORT
      LAYER M5 ;
        RECT  6.336 11.688 6.36 11.88 ;
    END
  END q[31]
  PIN q[320]
    DIRECTION OUTPUT ;
    USE SIGNAL ;
    PORT
      LAYER M5 ;
        RECT  61.824 11.688 61.848 11.88 ;
    END
  END q[320]
  PIN q[321]
    DIRECTION OUTPUT ;
    USE SIGNAL ;
    PORT
      LAYER M5 ;
        RECT  62.016 11.688 62.04 11.88 ;
    END
  END q[321]
  PIN q[322]
    DIRECTION OUTPUT ;
    USE SIGNAL ;
    PORT
      LAYER M5 ;
        RECT  62.208 11.688 62.232 11.88 ;
    END
  END q[322]
  PIN q[323]
    DIRECTION OUTPUT ;
    USE SIGNAL ;
    PORT
      LAYER M5 ;
        RECT  62.4 11.688 62.424 11.88 ;
    END
  END q[323]
  PIN q[324]
    DIRECTION OUTPUT ;
    USE SIGNAL ;
    PORT
      LAYER M5 ;
        RECT  62.592 11.688 62.616 11.88 ;
    END
  END q[324]
  PIN q[325]
    DIRECTION OUTPUT ;
    USE SIGNAL ;
    PORT
      LAYER M5 ;
        RECT  62.784 11.688 62.808 11.88 ;
    END
  END q[325]
  PIN q[326]
    DIRECTION OUTPUT ;
    USE SIGNAL ;
    PORT
      LAYER M5 ;
        RECT  62.976 11.688 63 11.88 ;
    END
  END q[326]
  PIN q[327]
    DIRECTION OUTPUT ;
    USE SIGNAL ;
    PORT
      LAYER M5 ;
        RECT  63.168 11.688 63.192 11.88 ;
    END
  END q[327]
  PIN q[328]
    DIRECTION OUTPUT ;
    USE SIGNAL ;
    PORT
      LAYER M5 ;
        RECT  63.36 11.688 63.384 11.88 ;
    END
  END q[328]
  PIN q[329]
    DIRECTION OUTPUT ;
    USE SIGNAL ;
    PORT
      LAYER M5 ;
        RECT  63.552 11.688 63.576 11.88 ;
    END
  END q[329]
  PIN q[32]
    DIRECTION OUTPUT ;
    USE SIGNAL ;
    PORT
      LAYER M5 ;
        RECT  6.528 11.688 6.552 11.88 ;
    END
  END q[32]
  PIN q[330]
    DIRECTION OUTPUT ;
    USE SIGNAL ;
    PORT
      LAYER M5 ;
        RECT  63.744 11.688 63.768 11.88 ;
    END
  END q[330]
  PIN q[331]
    DIRECTION OUTPUT ;
    USE SIGNAL ;
    PORT
      LAYER M5 ;
        RECT  63.936 11.688 63.96 11.88 ;
    END
  END q[331]
  PIN q[332]
    DIRECTION OUTPUT ;
    USE SIGNAL ;
    PORT
      LAYER M5 ;
        RECT  64.128 11.688 64.152 11.88 ;
    END
  END q[332]
  PIN q[333]
    DIRECTION OUTPUT ;
    USE SIGNAL ;
    PORT
      LAYER M5 ;
        RECT  64.32 11.688 64.344 11.88 ;
    END
  END q[333]
  PIN q[334]
    DIRECTION OUTPUT ;
    USE SIGNAL ;
    PORT
      LAYER M5 ;
        RECT  64.512 11.688 64.536 11.88 ;
    END
  END q[334]
  PIN q[335]
    DIRECTION OUTPUT ;
    USE SIGNAL ;
    PORT
      LAYER M5 ;
        RECT  64.704 11.688 64.728 11.88 ;
    END
  END q[335]
  PIN q[336]
    DIRECTION OUTPUT ;
    USE SIGNAL ;
    PORT
      LAYER M5 ;
        RECT  64.896 11.688 64.92 11.88 ;
    END
  END q[336]
  PIN q[337]
    DIRECTION OUTPUT ;
    USE SIGNAL ;
    PORT
      LAYER M5 ;
        RECT  65.088 11.688 65.112 11.88 ;
    END
  END q[337]
  PIN q[338]
    DIRECTION OUTPUT ;
    USE SIGNAL ;
    PORT
      LAYER M5 ;
        RECT  65.28 11.688 65.304 11.88 ;
    END
  END q[338]
  PIN q[339]
    DIRECTION OUTPUT ;
    USE SIGNAL ;
    PORT
      LAYER M5 ;
        RECT  65.472 11.688 65.496 11.88 ;
    END
  END q[339]
  PIN q[33]
    DIRECTION OUTPUT ;
    USE SIGNAL ;
    PORT
      LAYER M5 ;
        RECT  6.72 11.688 6.744 11.88 ;
    END
  END q[33]
  PIN q[340]
    DIRECTION OUTPUT ;
    USE SIGNAL ;
    PORT
      LAYER M5 ;
        RECT  65.664 11.688 65.688 11.88 ;
    END
  END q[340]
  PIN q[341]
    DIRECTION OUTPUT ;
    USE SIGNAL ;
    PORT
      LAYER M5 ;
        RECT  65.856 11.688 65.88 11.88 ;
    END
  END q[341]
  PIN q[342]
    DIRECTION OUTPUT ;
    USE SIGNAL ;
    PORT
      LAYER M5 ;
        RECT  66.048 11.688 66.072 11.88 ;
    END
  END q[342]
  PIN q[343]
    DIRECTION OUTPUT ;
    USE SIGNAL ;
    PORT
      LAYER M5 ;
        RECT  66.24 11.688 66.264 11.88 ;
    END
  END q[343]
  PIN q[344]
    DIRECTION OUTPUT ;
    USE SIGNAL ;
    PORT
      LAYER M5 ;
        RECT  66.432 11.688 66.456 11.88 ;
    END
  END q[344]
  PIN q[345]
    DIRECTION OUTPUT ;
    USE SIGNAL ;
    PORT
      LAYER M5 ;
        RECT  66.624 11.688 66.648 11.88 ;
    END
  END q[345]
  PIN q[346]
    DIRECTION OUTPUT ;
    USE SIGNAL ;
    PORT
      LAYER M5 ;
        RECT  66.816 11.688 66.84 11.88 ;
    END
  END q[346]
  PIN q[347]
    DIRECTION OUTPUT ;
    USE SIGNAL ;
    PORT
      LAYER M5 ;
        RECT  67.008 11.688 67.032 11.88 ;
    END
  END q[347]
  PIN q[348]
    DIRECTION OUTPUT ;
    USE SIGNAL ;
    PORT
      LAYER M5 ;
        RECT  67.2 11.688 67.224 11.88 ;
    END
  END q[348]
  PIN q[349]
    DIRECTION OUTPUT ;
    USE SIGNAL ;
    PORT
      LAYER M5 ;
        RECT  67.392 11.688 67.416 11.88 ;
    END
  END q[349]
  PIN q[34]
    DIRECTION OUTPUT ;
    USE SIGNAL ;
    PORT
      LAYER M5 ;
        RECT  6.912 11.688 6.936 11.88 ;
    END
  END q[34]
  PIN q[350]
    DIRECTION OUTPUT ;
    USE SIGNAL ;
    PORT
      LAYER M5 ;
        RECT  67.584 11.688 67.608 11.88 ;
    END
  END q[350]
  PIN q[351]
    DIRECTION OUTPUT ;
    USE SIGNAL ;
    PORT
      LAYER M5 ;
        RECT  67.776 11.688 67.8 11.88 ;
    END
  END q[351]
  PIN q[352]
    DIRECTION OUTPUT ;
    USE SIGNAL ;
    PORT
      LAYER M5 ;
        RECT  67.968 11.688 67.992 11.88 ;
    END
  END q[352]
  PIN q[353]
    DIRECTION OUTPUT ;
    USE SIGNAL ;
    PORT
      LAYER M5 ;
        RECT  68.16 11.688 68.184 11.88 ;
    END
  END q[353]
  PIN q[354]
    DIRECTION OUTPUT ;
    USE SIGNAL ;
    PORT
      LAYER M5 ;
        RECT  68.352 11.688 68.376 11.88 ;
    END
  END q[354]
  PIN q[355]
    DIRECTION OUTPUT ;
    USE SIGNAL ;
    PORT
      LAYER M5 ;
        RECT  68.544 11.688 68.568 11.88 ;
    END
  END q[355]
  PIN q[356]
    DIRECTION OUTPUT ;
    USE SIGNAL ;
    PORT
      LAYER M5 ;
        RECT  68.736 11.688 68.76 11.88 ;
    END
  END q[356]
  PIN q[357]
    DIRECTION OUTPUT ;
    USE SIGNAL ;
    PORT
      LAYER M5 ;
        RECT  68.928 11.688 68.952 11.88 ;
    END
  END q[357]
  PIN q[358]
    DIRECTION OUTPUT ;
    USE SIGNAL ;
    PORT
      LAYER M5 ;
        RECT  69.12 11.688 69.144 11.88 ;
    END
  END q[358]
  PIN q[359]
    DIRECTION OUTPUT ;
    USE SIGNAL ;
    PORT
      LAYER M5 ;
        RECT  69.312 11.688 69.336 11.88 ;
    END
  END q[359]
  PIN q[35]
    DIRECTION OUTPUT ;
    USE SIGNAL ;
    PORT
      LAYER M5 ;
        RECT  7.104 11.688 7.128 11.88 ;
    END
  END q[35]
  PIN q[360]
    DIRECTION OUTPUT ;
    USE SIGNAL ;
    PORT
      LAYER M5 ;
        RECT  69.504 11.688 69.528 11.88 ;
    END
  END q[360]
  PIN q[361]
    DIRECTION OUTPUT ;
    USE SIGNAL ;
    PORT
      LAYER M5 ;
        RECT  69.696 11.688 69.72 11.88 ;
    END
  END q[361]
  PIN q[362]
    DIRECTION OUTPUT ;
    USE SIGNAL ;
    PORT
      LAYER M5 ;
        RECT  69.888 11.688 69.912 11.88 ;
    END
  END q[362]
  PIN q[363]
    DIRECTION OUTPUT ;
    USE SIGNAL ;
    PORT
      LAYER M5 ;
        RECT  70.08 11.688 70.104 11.88 ;
    END
  END q[363]
  PIN q[364]
    DIRECTION OUTPUT ;
    USE SIGNAL ;
    PORT
      LAYER M5 ;
        RECT  70.272 11.688 70.296 11.88 ;
    END
  END q[364]
  PIN q[365]
    DIRECTION OUTPUT ;
    USE SIGNAL ;
    PORT
      LAYER M5 ;
        RECT  70.464 11.688 70.488 11.88 ;
    END
  END q[365]
  PIN q[366]
    DIRECTION OUTPUT ;
    USE SIGNAL ;
    PORT
      LAYER M5 ;
        RECT  70.656 11.688 70.68 11.88 ;
    END
  END q[366]
  PIN q[367]
    DIRECTION OUTPUT ;
    USE SIGNAL ;
    PORT
      LAYER M5 ;
        RECT  70.848 11.688 70.872 11.88 ;
    END
  END q[367]
  PIN q[368]
    DIRECTION OUTPUT ;
    USE SIGNAL ;
    PORT
      LAYER M5 ;
        RECT  71.04 11.688 71.064 11.88 ;
    END
  END q[368]
  PIN q[369]
    DIRECTION OUTPUT ;
    USE SIGNAL ;
    PORT
      LAYER M5 ;
        RECT  71.232 11.688 71.256 11.88 ;
    END
  END q[369]
  PIN q[36]
    DIRECTION OUTPUT ;
    USE SIGNAL ;
    PORT
      LAYER M5 ;
        RECT  7.296 11.688 7.32 11.88 ;
    END
  END q[36]
  PIN q[370]
    DIRECTION OUTPUT ;
    USE SIGNAL ;
    PORT
      LAYER M5 ;
        RECT  71.424 11.688 71.448 11.88 ;
    END
  END q[370]
  PIN q[371]
    DIRECTION OUTPUT ;
    USE SIGNAL ;
    PORT
      LAYER M5 ;
        RECT  71.616 11.688 71.64 11.88 ;
    END
  END q[371]
  PIN q[372]
    DIRECTION OUTPUT ;
    USE SIGNAL ;
    PORT
      LAYER M5 ;
        RECT  71.808 11.688 71.832 11.88 ;
    END
  END q[372]
  PIN q[373]
    DIRECTION OUTPUT ;
    USE SIGNAL ;
    PORT
      LAYER M5 ;
        RECT  72 11.688 72.024 11.88 ;
    END
  END q[373]
  PIN q[374]
    DIRECTION OUTPUT ;
    USE SIGNAL ;
    PORT
      LAYER M5 ;
        RECT  72.192 11.688 72.216 11.88 ;
    END
  END q[374]
  PIN q[375]
    DIRECTION OUTPUT ;
    USE SIGNAL ;
    PORT
      LAYER M5 ;
        RECT  72.384 11.688 72.408 11.88 ;
    END
  END q[375]
  PIN q[376]
    DIRECTION OUTPUT ;
    USE SIGNAL ;
    PORT
      LAYER M5 ;
        RECT  72.576 11.688 72.6 11.88 ;
    END
  END q[376]
  PIN q[377]
    DIRECTION OUTPUT ;
    USE SIGNAL ;
    PORT
      LAYER M5 ;
        RECT  72.768 11.688 72.792 11.88 ;
    END
  END q[377]
  PIN q[378]
    DIRECTION OUTPUT ;
    USE SIGNAL ;
    PORT
      LAYER M5 ;
        RECT  72.96 11.688 72.984 11.88 ;
    END
  END q[378]
  PIN q[379]
    DIRECTION OUTPUT ;
    USE SIGNAL ;
    PORT
      LAYER M5 ;
        RECT  73.152 11.688 73.176 11.88 ;
    END
  END q[379]
  PIN q[37]
    DIRECTION OUTPUT ;
    USE SIGNAL ;
    PORT
      LAYER M5 ;
        RECT  7.488 11.688 7.512 11.88 ;
    END
  END q[37]
  PIN q[380]
    DIRECTION OUTPUT ;
    USE SIGNAL ;
    PORT
      LAYER M5 ;
        RECT  73.344 11.688 73.368 11.88 ;
    END
  END q[380]
  PIN q[381]
    DIRECTION OUTPUT ;
    USE SIGNAL ;
    PORT
      LAYER M5 ;
        RECT  73.536 11.688 73.56 11.88 ;
    END
  END q[381]
  PIN q[382]
    DIRECTION OUTPUT ;
    USE SIGNAL ;
    PORT
      LAYER M5 ;
        RECT  73.728 11.688 73.752 11.88 ;
    END
  END q[382]
  PIN q[383]
    DIRECTION OUTPUT ;
    USE SIGNAL ;
    PORT
      LAYER M5 ;
        RECT  73.92 11.688 73.944 11.88 ;
    END
  END q[383]
  PIN q[384]
    DIRECTION OUTPUT ;
    USE SIGNAL ;
    PORT
      LAYER M5 ;
        RECT  74.112 11.688 74.136 11.88 ;
    END
  END q[384]
  PIN q[385]
    DIRECTION OUTPUT ;
    USE SIGNAL ;
    PORT
      LAYER M5 ;
        RECT  74.304 11.688 74.328 11.88 ;
    END
  END q[385]
  PIN q[386]
    DIRECTION OUTPUT ;
    USE SIGNAL ;
    PORT
      LAYER M5 ;
        RECT  74.496 11.688 74.52 11.88 ;
    END
  END q[386]
  PIN q[387]
    DIRECTION OUTPUT ;
    USE SIGNAL ;
    PORT
      LAYER M5 ;
        RECT  74.688 11.688 74.712 11.88 ;
    END
  END q[387]
  PIN q[388]
    DIRECTION OUTPUT ;
    USE SIGNAL ;
    PORT
      LAYER M5 ;
        RECT  74.88 11.688 74.904 11.88 ;
    END
  END q[388]
  PIN q[389]
    DIRECTION OUTPUT ;
    USE SIGNAL ;
    PORT
      LAYER M5 ;
        RECT  75.072 11.688 75.096 11.88 ;
    END
  END q[389]
  PIN q[38]
    DIRECTION OUTPUT ;
    USE SIGNAL ;
    PORT
      LAYER M5 ;
        RECT  7.68 11.688 7.704 11.88 ;
    END
  END q[38]
  PIN q[390]
    DIRECTION OUTPUT ;
    USE SIGNAL ;
    PORT
      LAYER M5 ;
        RECT  75.264 11.688 75.288 11.88 ;
    END
  END q[390]
  PIN q[391]
    DIRECTION OUTPUT ;
    USE SIGNAL ;
    PORT
      LAYER M5 ;
        RECT  75.456 11.688 75.48 11.88 ;
    END
  END q[391]
  PIN q[392]
    DIRECTION OUTPUT ;
    USE SIGNAL ;
    PORT
      LAYER M5 ;
        RECT  75.648 11.688 75.672 11.88 ;
    END
  END q[392]
  PIN q[393]
    DIRECTION OUTPUT ;
    USE SIGNAL ;
    PORT
      LAYER M5 ;
        RECT  75.84 11.688 75.864 11.88 ;
    END
  END q[393]
  PIN q[394]
    DIRECTION OUTPUT ;
    USE SIGNAL ;
    PORT
      LAYER M5 ;
        RECT  76.032 11.688 76.056 11.88 ;
    END
  END q[394]
  PIN q[395]
    DIRECTION OUTPUT ;
    USE SIGNAL ;
    PORT
      LAYER M5 ;
        RECT  76.224 11.688 76.248 11.88 ;
    END
  END q[395]
  PIN q[396]
    DIRECTION OUTPUT ;
    USE SIGNAL ;
    PORT
      LAYER M5 ;
        RECT  76.416 11.688 76.44 11.88 ;
    END
  END q[396]
  PIN q[397]
    DIRECTION OUTPUT ;
    USE SIGNAL ;
    PORT
      LAYER M5 ;
        RECT  76.608 11.688 76.632 11.88 ;
    END
  END q[397]
  PIN q[398]
    DIRECTION OUTPUT ;
    USE SIGNAL ;
    PORT
      LAYER M5 ;
        RECT  76.8 11.688 76.824 11.88 ;
    END
  END q[398]
  PIN q[399]
    DIRECTION OUTPUT ;
    USE SIGNAL ;
    PORT
      LAYER M5 ;
        RECT  76.992 11.688 77.016 11.88 ;
    END
  END q[399]
  PIN q[39]
    DIRECTION OUTPUT ;
    USE SIGNAL ;
    PORT
      LAYER M5 ;
        RECT  7.872 11.688 7.896 11.88 ;
    END
  END q[39]
  PIN q[3]
    DIRECTION OUTPUT ;
    USE SIGNAL ;
    PORT
      LAYER M5 ;
        RECT  0.96 11.688 0.984 11.88 ;
    END
  END q[3]
  PIN q[400]
    DIRECTION OUTPUT ;
    USE SIGNAL ;
    PORT
      LAYER M5 ;
        RECT  77.184 11.688 77.208 11.88 ;
    END
  END q[400]
  PIN q[401]
    DIRECTION OUTPUT ;
    USE SIGNAL ;
    PORT
      LAYER M5 ;
        RECT  77.376 11.688 77.4 11.88 ;
    END
  END q[401]
  PIN q[402]
    DIRECTION OUTPUT ;
    USE SIGNAL ;
    PORT
      LAYER M5 ;
        RECT  77.568 11.688 77.592 11.88 ;
    END
  END q[402]
  PIN q[403]
    DIRECTION OUTPUT ;
    USE SIGNAL ;
    PORT
      LAYER M5 ;
        RECT  77.76 11.688 77.784 11.88 ;
    END
  END q[403]
  PIN q[404]
    DIRECTION OUTPUT ;
    USE SIGNAL ;
    PORT
      LAYER M5 ;
        RECT  77.952 11.688 77.976 11.88 ;
    END
  END q[404]
  PIN q[405]
    DIRECTION OUTPUT ;
    USE SIGNAL ;
    PORT
      LAYER M5 ;
        RECT  78.144 11.688 78.168 11.88 ;
    END
  END q[405]
  PIN q[406]
    DIRECTION OUTPUT ;
    USE SIGNAL ;
    PORT
      LAYER M5 ;
        RECT  78.336 11.688 78.36 11.88 ;
    END
  END q[406]
  PIN q[407]
    DIRECTION OUTPUT ;
    USE SIGNAL ;
    PORT
      LAYER M5 ;
        RECT  78.528 11.688 78.552 11.88 ;
    END
  END q[407]
  PIN q[408]
    DIRECTION OUTPUT ;
    USE SIGNAL ;
    PORT
      LAYER M5 ;
        RECT  78.72 11.688 78.744 11.88 ;
    END
  END q[408]
  PIN q[409]
    DIRECTION OUTPUT ;
    USE SIGNAL ;
    PORT
      LAYER M5 ;
        RECT  78.912 11.688 78.936 11.88 ;
    END
  END q[409]
  PIN q[40]
    DIRECTION OUTPUT ;
    USE SIGNAL ;
    PORT
      LAYER M5 ;
        RECT  8.064 11.688 8.088 11.88 ;
    END
  END q[40]
  PIN q[410]
    DIRECTION OUTPUT ;
    USE SIGNAL ;
    PORT
      LAYER M5 ;
        RECT  79.104 11.688 79.128 11.88 ;
    END
  END q[410]
  PIN q[411]
    DIRECTION OUTPUT ;
    USE SIGNAL ;
    PORT
      LAYER M5 ;
        RECT  79.296 11.688 79.32 11.88 ;
    END
  END q[411]
  PIN q[412]
    DIRECTION OUTPUT ;
    USE SIGNAL ;
    PORT
      LAYER M5 ;
        RECT  79.488 11.688 79.512 11.88 ;
    END
  END q[412]
  PIN q[413]
    DIRECTION OUTPUT ;
    USE SIGNAL ;
    PORT
      LAYER M5 ;
        RECT  79.68 11.688 79.704 11.88 ;
    END
  END q[413]
  PIN q[414]
    DIRECTION OUTPUT ;
    USE SIGNAL ;
    PORT
      LAYER M5 ;
        RECT  79.872 11.688 79.896 11.88 ;
    END
  END q[414]
  PIN q[415]
    DIRECTION OUTPUT ;
    USE SIGNAL ;
    PORT
      LAYER M5 ;
        RECT  80.064 11.688 80.088 11.88 ;
    END
  END q[415]
  PIN q[416]
    DIRECTION OUTPUT ;
    USE SIGNAL ;
    PORT
      LAYER M5 ;
        RECT  80.256 11.688 80.28 11.88 ;
    END
  END q[416]
  PIN q[417]
    DIRECTION OUTPUT ;
    USE SIGNAL ;
    PORT
      LAYER M5 ;
        RECT  80.448 11.688 80.472 11.88 ;
    END
  END q[417]
  PIN q[418]
    DIRECTION OUTPUT ;
    USE SIGNAL ;
    PORT
      LAYER M5 ;
        RECT  80.64 11.688 80.664 11.88 ;
    END
  END q[418]
  PIN q[419]
    DIRECTION OUTPUT ;
    USE SIGNAL ;
    PORT
      LAYER M5 ;
        RECT  80.832 11.688 80.856 11.88 ;
    END
  END q[419]
  PIN q[41]
    DIRECTION OUTPUT ;
    USE SIGNAL ;
    PORT
      LAYER M5 ;
        RECT  8.256 11.688 8.28 11.88 ;
    END
  END q[41]
  PIN q[420]
    DIRECTION OUTPUT ;
    USE SIGNAL ;
    PORT
      LAYER M5 ;
        RECT  81.024 11.688 81.048 11.88 ;
    END
  END q[420]
  PIN q[421]
    DIRECTION OUTPUT ;
    USE SIGNAL ;
    PORT
      LAYER M5 ;
        RECT  81.216 11.688 81.24 11.88 ;
    END
  END q[421]
  PIN q[422]
    DIRECTION OUTPUT ;
    USE SIGNAL ;
    PORT
      LAYER M5 ;
        RECT  81.408 11.688 81.432 11.88 ;
    END
  END q[422]
  PIN q[423]
    DIRECTION OUTPUT ;
    USE SIGNAL ;
    PORT
      LAYER M5 ;
        RECT  81.6 11.688 81.624 11.88 ;
    END
  END q[423]
  PIN q[424]
    DIRECTION OUTPUT ;
    USE SIGNAL ;
    PORT
      LAYER M5 ;
        RECT  81.792 11.688 81.816 11.88 ;
    END
  END q[424]
  PIN q[425]
    DIRECTION OUTPUT ;
    USE SIGNAL ;
    PORT
      LAYER M5 ;
        RECT  81.984 11.688 82.008 11.88 ;
    END
  END q[425]
  PIN q[426]
    DIRECTION OUTPUT ;
    USE SIGNAL ;
    PORT
      LAYER M5 ;
        RECT  82.176 11.688 82.2 11.88 ;
    END
  END q[426]
  PIN q[427]
    DIRECTION OUTPUT ;
    USE SIGNAL ;
    PORT
      LAYER M5 ;
        RECT  82.368 11.688 82.392 11.88 ;
    END
  END q[427]
  PIN q[428]
    DIRECTION OUTPUT ;
    USE SIGNAL ;
    PORT
      LAYER M5 ;
        RECT  82.56 11.688 82.584 11.88 ;
    END
  END q[428]
  PIN q[429]
    DIRECTION OUTPUT ;
    USE SIGNAL ;
    PORT
      LAYER M5 ;
        RECT  82.752 11.688 82.776 11.88 ;
    END
  END q[429]
  PIN q[42]
    DIRECTION OUTPUT ;
    USE SIGNAL ;
    PORT
      LAYER M5 ;
        RECT  8.448 11.688 8.472 11.88 ;
    END
  END q[42]
  PIN q[430]
    DIRECTION OUTPUT ;
    USE SIGNAL ;
    PORT
      LAYER M5 ;
        RECT  82.944 11.688 82.968 11.88 ;
    END
  END q[430]
  PIN q[431]
    DIRECTION OUTPUT ;
    USE SIGNAL ;
    PORT
      LAYER M5 ;
        RECT  83.136 11.688 83.16 11.88 ;
    END
  END q[431]
  PIN q[432]
    DIRECTION OUTPUT ;
    USE SIGNAL ;
    PORT
      LAYER M5 ;
        RECT  83.328 11.688 83.352 11.88 ;
    END
  END q[432]
  PIN q[433]
    DIRECTION OUTPUT ;
    USE SIGNAL ;
    PORT
      LAYER M5 ;
        RECT  83.52 11.688 83.544 11.88 ;
    END
  END q[433]
  PIN q[434]
    DIRECTION OUTPUT ;
    USE SIGNAL ;
    PORT
      LAYER M5 ;
        RECT  83.712 11.688 83.736 11.88 ;
    END
  END q[434]
  PIN q[435]
    DIRECTION OUTPUT ;
    USE SIGNAL ;
    PORT
      LAYER M5 ;
        RECT  83.904 11.688 83.928 11.88 ;
    END
  END q[435]
  PIN q[436]
    DIRECTION OUTPUT ;
    USE SIGNAL ;
    PORT
      LAYER M5 ;
        RECT  84.096 11.688 84.12 11.88 ;
    END
  END q[436]
  PIN q[437]
    DIRECTION OUTPUT ;
    USE SIGNAL ;
    PORT
      LAYER M5 ;
        RECT  84.288 11.688 84.312 11.88 ;
    END
  END q[437]
  PIN q[438]
    DIRECTION OUTPUT ;
    USE SIGNAL ;
    PORT
      LAYER M5 ;
        RECT  84.48 11.688 84.504 11.88 ;
    END
  END q[438]
  PIN q[439]
    DIRECTION OUTPUT ;
    USE SIGNAL ;
    PORT
      LAYER M5 ;
        RECT  84.672 11.688 84.696 11.88 ;
    END
  END q[439]
  PIN q[43]
    DIRECTION OUTPUT ;
    USE SIGNAL ;
    PORT
      LAYER M5 ;
        RECT  8.64 11.688 8.664 11.88 ;
    END
  END q[43]
  PIN q[440]
    DIRECTION OUTPUT ;
    USE SIGNAL ;
    PORT
      LAYER M5 ;
        RECT  84.864 11.688 84.888 11.88 ;
    END
  END q[440]
  PIN q[441]
    DIRECTION OUTPUT ;
    USE SIGNAL ;
    PORT
      LAYER M5 ;
        RECT  85.056 11.688 85.08 11.88 ;
    END
  END q[441]
  PIN q[442]
    DIRECTION OUTPUT ;
    USE SIGNAL ;
    PORT
      LAYER M5 ;
        RECT  85.248 11.688 85.272 11.88 ;
    END
  END q[442]
  PIN q[443]
    DIRECTION OUTPUT ;
    USE SIGNAL ;
    PORT
      LAYER M5 ;
        RECT  85.44 11.688 85.464 11.88 ;
    END
  END q[443]
  PIN q[444]
    DIRECTION OUTPUT ;
    USE SIGNAL ;
    PORT
      LAYER M5 ;
        RECT  85.632 11.688 85.656 11.88 ;
    END
  END q[444]
  PIN q[445]
    DIRECTION OUTPUT ;
    USE SIGNAL ;
    PORT
      LAYER M5 ;
        RECT  85.824 11.688 85.848 11.88 ;
    END
  END q[445]
  PIN q[446]
    DIRECTION OUTPUT ;
    USE SIGNAL ;
    PORT
      LAYER M5 ;
        RECT  86.016 11.688 86.04 11.88 ;
    END
  END q[446]
  PIN q[447]
    DIRECTION OUTPUT ;
    USE SIGNAL ;
    PORT
      LAYER M5 ;
        RECT  86.208 11.688 86.232 11.88 ;
    END
  END q[447]
  PIN q[448]
    DIRECTION OUTPUT ;
    USE SIGNAL ;
    PORT
      LAYER M5 ;
        RECT  86.4 11.688 86.424 11.88 ;
    END
  END q[448]
  PIN q[449]
    DIRECTION OUTPUT ;
    USE SIGNAL ;
    PORT
      LAYER M5 ;
        RECT  86.592 11.688 86.616 11.88 ;
    END
  END q[449]
  PIN q[44]
    DIRECTION OUTPUT ;
    USE SIGNAL ;
    PORT
      LAYER M5 ;
        RECT  8.832 11.688 8.856 11.88 ;
    END
  END q[44]
  PIN q[450]
    DIRECTION OUTPUT ;
    USE SIGNAL ;
    PORT
      LAYER M5 ;
        RECT  86.784 11.688 86.808 11.88 ;
    END
  END q[450]
  PIN q[451]
    DIRECTION OUTPUT ;
    USE SIGNAL ;
    PORT
      LAYER M5 ;
        RECT  86.976 11.688 87 11.88 ;
    END
  END q[451]
  PIN q[452]
    DIRECTION OUTPUT ;
    USE SIGNAL ;
    PORT
      LAYER M5 ;
        RECT  87.168 11.688 87.192 11.88 ;
    END
  END q[452]
  PIN q[453]
    DIRECTION OUTPUT ;
    USE SIGNAL ;
    PORT
      LAYER M5 ;
        RECT  87.36 11.688 87.384 11.88 ;
    END
  END q[453]
  PIN q[454]
    DIRECTION OUTPUT ;
    USE SIGNAL ;
    PORT
      LAYER M5 ;
        RECT  87.552 11.688 87.576 11.88 ;
    END
  END q[454]
  PIN q[455]
    DIRECTION OUTPUT ;
    USE SIGNAL ;
    PORT
      LAYER M5 ;
        RECT  87.744 11.688 87.768 11.88 ;
    END
  END q[455]
  PIN q[456]
    DIRECTION OUTPUT ;
    USE SIGNAL ;
    PORT
      LAYER M5 ;
        RECT  87.936 11.688 87.96 11.88 ;
    END
  END q[456]
  PIN q[457]
    DIRECTION OUTPUT ;
    USE SIGNAL ;
    PORT
      LAYER M5 ;
        RECT  88.128 11.688 88.152 11.88 ;
    END
  END q[457]
  PIN q[458]
    DIRECTION OUTPUT ;
    USE SIGNAL ;
    PORT
      LAYER M5 ;
        RECT  88.32 11.688 88.344 11.88 ;
    END
  END q[458]
  PIN q[459]
    DIRECTION OUTPUT ;
    USE SIGNAL ;
    PORT
      LAYER M5 ;
        RECT  88.512 11.688 88.536 11.88 ;
    END
  END q[459]
  PIN q[45]
    DIRECTION OUTPUT ;
    USE SIGNAL ;
    PORT
      LAYER M5 ;
        RECT  9.024 11.688 9.048 11.88 ;
    END
  END q[45]
  PIN q[460]
    DIRECTION OUTPUT ;
    USE SIGNAL ;
    PORT
      LAYER M5 ;
        RECT  88.704 11.688 88.728 11.88 ;
    END
  END q[460]
  PIN q[461]
    DIRECTION OUTPUT ;
    USE SIGNAL ;
    PORT
      LAYER M5 ;
        RECT  88.896 11.688 88.92 11.88 ;
    END
  END q[461]
  PIN q[462]
    DIRECTION OUTPUT ;
    USE SIGNAL ;
    PORT
      LAYER M5 ;
        RECT  89.088 11.688 89.112 11.88 ;
    END
  END q[462]
  PIN q[463]
    DIRECTION OUTPUT ;
    USE SIGNAL ;
    PORT
      LAYER M5 ;
        RECT  89.28 11.688 89.304 11.88 ;
    END
  END q[463]
  PIN q[464]
    DIRECTION OUTPUT ;
    USE SIGNAL ;
    PORT
      LAYER M5 ;
        RECT  89.472 11.688 89.496 11.88 ;
    END
  END q[464]
  PIN q[465]
    DIRECTION OUTPUT ;
    USE SIGNAL ;
    PORT
      LAYER M5 ;
        RECT  89.664 11.688 89.688 11.88 ;
    END
  END q[465]
  PIN q[466]
    DIRECTION OUTPUT ;
    USE SIGNAL ;
    PORT
      LAYER M5 ;
        RECT  89.856 11.688 89.88 11.88 ;
    END
  END q[466]
  PIN q[467]
    DIRECTION OUTPUT ;
    USE SIGNAL ;
    PORT
      LAYER M5 ;
        RECT  90.048 11.688 90.072 11.88 ;
    END
  END q[467]
  PIN q[468]
    DIRECTION OUTPUT ;
    USE SIGNAL ;
    PORT
      LAYER M5 ;
        RECT  90.24 11.688 90.264 11.88 ;
    END
  END q[468]
  PIN q[469]
    DIRECTION OUTPUT ;
    USE SIGNAL ;
    PORT
      LAYER M5 ;
        RECT  90.432 11.688 90.456 11.88 ;
    END
  END q[469]
  PIN q[46]
    DIRECTION OUTPUT ;
    USE SIGNAL ;
    PORT
      LAYER M5 ;
        RECT  9.216 11.688 9.24 11.88 ;
    END
  END q[46]
  PIN q[470]
    DIRECTION OUTPUT ;
    USE SIGNAL ;
    PORT
      LAYER M5 ;
        RECT  90.624 11.688 90.648 11.88 ;
    END
  END q[470]
  PIN q[471]
    DIRECTION OUTPUT ;
    USE SIGNAL ;
    PORT
      LAYER M5 ;
        RECT  90.816 11.688 90.84 11.88 ;
    END
  END q[471]
  PIN q[472]
    DIRECTION OUTPUT ;
    USE SIGNAL ;
    PORT
      LAYER M5 ;
        RECT  91.008 11.688 91.032 11.88 ;
    END
  END q[472]
  PIN q[473]
    DIRECTION OUTPUT ;
    USE SIGNAL ;
    PORT
      LAYER M5 ;
        RECT  91.2 11.688 91.224 11.88 ;
    END
  END q[473]
  PIN q[474]
    DIRECTION OUTPUT ;
    USE SIGNAL ;
    PORT
      LAYER M5 ;
        RECT  91.392 11.688 91.416 11.88 ;
    END
  END q[474]
  PIN q[475]
    DIRECTION OUTPUT ;
    USE SIGNAL ;
    PORT
      LAYER M5 ;
        RECT  91.584 11.688 91.608 11.88 ;
    END
  END q[475]
  PIN q[476]
    DIRECTION OUTPUT ;
    USE SIGNAL ;
    PORT
      LAYER M5 ;
        RECT  91.776 11.688 91.8 11.88 ;
    END
  END q[476]
  PIN q[477]
    DIRECTION OUTPUT ;
    USE SIGNAL ;
    PORT
      LAYER M5 ;
        RECT  91.968 11.688 91.992 11.88 ;
    END
  END q[477]
  PIN q[478]
    DIRECTION OUTPUT ;
    USE SIGNAL ;
    PORT
      LAYER M5 ;
        RECT  92.16 11.688 92.184 11.88 ;
    END
  END q[478]
  PIN q[479]
    DIRECTION OUTPUT ;
    USE SIGNAL ;
    PORT
      LAYER M5 ;
        RECT  92.352 11.688 92.376 11.88 ;
    END
  END q[479]
  PIN q[47]
    DIRECTION OUTPUT ;
    USE SIGNAL ;
    PORT
      LAYER M5 ;
        RECT  9.408 11.688 9.432 11.88 ;
    END
  END q[47]
  PIN q[480]
    DIRECTION OUTPUT ;
    USE SIGNAL ;
    PORT
      LAYER M5 ;
        RECT  92.544 11.688 92.568 11.88 ;
    END
  END q[480]
  PIN q[481]
    DIRECTION OUTPUT ;
    USE SIGNAL ;
    PORT
      LAYER M5 ;
        RECT  92.736 11.688 92.76 11.88 ;
    END
  END q[481]
  PIN q[482]
    DIRECTION OUTPUT ;
    USE SIGNAL ;
    PORT
      LAYER M5 ;
        RECT  92.928 11.688 92.952 11.88 ;
    END
  END q[482]
  PIN q[483]
    DIRECTION OUTPUT ;
    USE SIGNAL ;
    PORT
      LAYER M5 ;
        RECT  93.12 11.688 93.144 11.88 ;
    END
  END q[483]
  PIN q[484]
    DIRECTION OUTPUT ;
    USE SIGNAL ;
    PORT
      LAYER M5 ;
        RECT  93.312 11.688 93.336 11.88 ;
    END
  END q[484]
  PIN q[485]
    DIRECTION OUTPUT ;
    USE SIGNAL ;
    PORT
      LAYER M5 ;
        RECT  93.504 11.688 93.528 11.88 ;
    END
  END q[485]
  PIN q[486]
    DIRECTION OUTPUT ;
    USE SIGNAL ;
    PORT
      LAYER M5 ;
        RECT  93.696 11.688 93.72 11.88 ;
    END
  END q[486]
  PIN q[487]
    DIRECTION OUTPUT ;
    USE SIGNAL ;
    PORT
      LAYER M5 ;
        RECT  93.888 11.688 93.912 11.88 ;
    END
  END q[487]
  PIN q[488]
    DIRECTION OUTPUT ;
    USE SIGNAL ;
    PORT
      LAYER M5 ;
        RECT  94.08 11.688 94.104 11.88 ;
    END
  END q[488]
  PIN q[489]
    DIRECTION OUTPUT ;
    USE SIGNAL ;
    PORT
      LAYER M5 ;
        RECT  94.272 11.688 94.296 11.88 ;
    END
  END q[489]
  PIN q[48]
    DIRECTION OUTPUT ;
    USE SIGNAL ;
    PORT
      LAYER M5 ;
        RECT  9.6 11.688 9.624 11.88 ;
    END
  END q[48]
  PIN q[490]
    DIRECTION OUTPUT ;
    USE SIGNAL ;
    PORT
      LAYER M5 ;
        RECT  94.464 11.688 94.488 11.88 ;
    END
  END q[490]
  PIN q[491]
    DIRECTION OUTPUT ;
    USE SIGNAL ;
    PORT
      LAYER M5 ;
        RECT  94.656 11.688 94.68 11.88 ;
    END
  END q[491]
  PIN q[492]
    DIRECTION OUTPUT ;
    USE SIGNAL ;
    PORT
      LAYER M5 ;
        RECT  94.848 11.688 94.872 11.88 ;
    END
  END q[492]
  PIN q[493]
    DIRECTION OUTPUT ;
    USE SIGNAL ;
    PORT
      LAYER M5 ;
        RECT  95.04 11.688 95.064 11.88 ;
    END
  END q[493]
  PIN q[494]
    DIRECTION OUTPUT ;
    USE SIGNAL ;
    PORT
      LAYER M5 ;
        RECT  95.232 11.688 95.256 11.88 ;
    END
  END q[494]
  PIN q[495]
    DIRECTION OUTPUT ;
    USE SIGNAL ;
    PORT
      LAYER M5 ;
        RECT  95.424 11.688 95.448 11.88 ;
    END
  END q[495]
  PIN q[496]
    DIRECTION OUTPUT ;
    USE SIGNAL ;
    PORT
      LAYER M5 ;
        RECT  95.616 11.688 95.64 11.88 ;
    END
  END q[496]
  PIN q[497]
    DIRECTION OUTPUT ;
    USE SIGNAL ;
    PORT
      LAYER M5 ;
        RECT  95.808 11.688 95.832 11.88 ;
    END
  END q[497]
  PIN q[498]
    DIRECTION OUTPUT ;
    USE SIGNAL ;
    PORT
      LAYER M5 ;
        RECT  96 11.688 96.024 11.88 ;
    END
  END q[498]
  PIN q[499]
    DIRECTION OUTPUT ;
    USE SIGNAL ;
    PORT
      LAYER M5 ;
        RECT  96.192 11.688 96.216 11.88 ;
    END
  END q[499]
  PIN q[49]
    DIRECTION OUTPUT ;
    USE SIGNAL ;
    PORT
      LAYER M5 ;
        RECT  9.792 11.688 9.816 11.88 ;
    END
  END q[49]
  PIN q[4]
    DIRECTION OUTPUT ;
    USE SIGNAL ;
    PORT
      LAYER M5 ;
        RECT  1.152 11.688 1.176 11.88 ;
    END
  END q[4]
  PIN q[500]
    DIRECTION OUTPUT ;
    USE SIGNAL ;
    PORT
      LAYER M5 ;
        RECT  96.384 11.688 96.408 11.88 ;
    END
  END q[500]
  PIN q[501]
    DIRECTION OUTPUT ;
    USE SIGNAL ;
    PORT
      LAYER M5 ;
        RECT  96.576 11.688 96.6 11.88 ;
    END
  END q[501]
  PIN q[502]
    DIRECTION OUTPUT ;
    USE SIGNAL ;
    PORT
      LAYER M5 ;
        RECT  96.768 11.688 96.792 11.88 ;
    END
  END q[502]
  PIN q[503]
    DIRECTION OUTPUT ;
    USE SIGNAL ;
    PORT
      LAYER M5 ;
        RECT  96.96 11.688 96.984 11.88 ;
    END
  END q[503]
  PIN q[504]
    DIRECTION OUTPUT ;
    USE SIGNAL ;
    PORT
      LAYER M5 ;
        RECT  97.152 11.688 97.176 11.88 ;
    END
  END q[504]
  PIN q[505]
    DIRECTION OUTPUT ;
    USE SIGNAL ;
    PORT
      LAYER M5 ;
        RECT  97.344 11.688 97.368 11.88 ;
    END
  END q[505]
  PIN q[506]
    DIRECTION OUTPUT ;
    USE SIGNAL ;
    PORT
      LAYER M5 ;
        RECT  97.536 11.688 97.56 11.88 ;
    END
  END q[506]
  PIN q[507]
    DIRECTION OUTPUT ;
    USE SIGNAL ;
    PORT
      LAYER M5 ;
        RECT  97.728 11.688 97.752 11.88 ;
    END
  END q[507]
  PIN q[508]
    DIRECTION OUTPUT ;
    USE SIGNAL ;
    PORT
      LAYER M5 ;
        RECT  97.92 11.688 97.944 11.88 ;
    END
  END q[508]
  PIN q[509]
    DIRECTION OUTPUT ;
    USE SIGNAL ;
    PORT
      LAYER M5 ;
        RECT  98.112 11.688 98.136 11.88 ;
    END
  END q[509]
  PIN q[50]
    DIRECTION OUTPUT ;
    USE SIGNAL ;
    PORT
      LAYER M5 ;
        RECT  9.984 11.688 10.008 11.88 ;
    END
  END q[50]
  PIN q[510]
    DIRECTION OUTPUT ;
    USE SIGNAL ;
    PORT
      LAYER M5 ;
        RECT  98.304 11.688 98.328 11.88 ;
    END
  END q[510]
  PIN q[511]
    DIRECTION OUTPUT ;
    USE SIGNAL ;
    PORT
      LAYER M5 ;
        RECT  98.496 11.688 98.52 11.88 ;
    END
  END q[511]
  PIN q[512]
    DIRECTION OUTPUT ;
    USE SIGNAL ;
    PORT
      LAYER M5 ;
        RECT  98.688 11.688 98.712 11.88 ;
    END
  END q[512]
  PIN q[513]
    DIRECTION OUTPUT ;
    USE SIGNAL ;
    PORT
      LAYER M5 ;
        RECT  98.88 11.688 98.904 11.88 ;
    END
  END q[513]
  PIN q[514]
    DIRECTION OUTPUT ;
    USE SIGNAL ;
    PORT
      LAYER M5 ;
        RECT  99.072 11.688 99.096 11.88 ;
    END
  END q[514]
  PIN q[515]
    DIRECTION OUTPUT ;
    USE SIGNAL ;
    PORT
      LAYER M5 ;
        RECT  99.264 11.688 99.288 11.88 ;
    END
  END q[515]
  PIN q[516]
    DIRECTION OUTPUT ;
    USE SIGNAL ;
    PORT
      LAYER M5 ;
        RECT  99.456 11.688 99.48 11.88 ;
    END
  END q[516]
  PIN q[517]
    DIRECTION OUTPUT ;
    USE SIGNAL ;
    PORT
      LAYER M5 ;
        RECT  99.648 11.688 99.672 11.88 ;
    END
  END q[517]
  PIN q[518]
    DIRECTION OUTPUT ;
    USE SIGNAL ;
    PORT
      LAYER M5 ;
        RECT  99.84 11.688 99.864 11.88 ;
    END
  END q[518]
  PIN q[519]
    DIRECTION OUTPUT ;
    USE SIGNAL ;
    PORT
      LAYER M5 ;
        RECT  100.032 11.688 100.056 11.88 ;
    END
  END q[519]
  PIN q[51]
    DIRECTION OUTPUT ;
    USE SIGNAL ;
    PORT
      LAYER M5 ;
        RECT  10.176 11.688 10.2 11.88 ;
    END
  END q[51]
  PIN q[520]
    DIRECTION OUTPUT ;
    USE SIGNAL ;
    PORT
      LAYER M5 ;
        RECT  100.224 11.688 100.248 11.88 ;
    END
  END q[520]
  PIN q[521]
    DIRECTION OUTPUT ;
    USE SIGNAL ;
    PORT
      LAYER M5 ;
        RECT  100.416 11.688 100.44 11.88 ;
    END
  END q[521]
  PIN q[522]
    DIRECTION OUTPUT ;
    USE SIGNAL ;
    PORT
      LAYER M5 ;
        RECT  100.608 11.688 100.632 11.88 ;
    END
  END q[522]
  PIN q[523]
    DIRECTION OUTPUT ;
    USE SIGNAL ;
    PORT
      LAYER M5 ;
        RECT  100.8 11.688 100.824 11.88 ;
    END
  END q[523]
  PIN q[524]
    DIRECTION OUTPUT ;
    USE SIGNAL ;
    PORT
      LAYER M5 ;
        RECT  100.992 11.688 101.016 11.88 ;
    END
  END q[524]
  PIN q[525]
    DIRECTION OUTPUT ;
    USE SIGNAL ;
    PORT
      LAYER M5 ;
        RECT  101.184 11.688 101.208 11.88 ;
    END
  END q[525]
  PIN q[526]
    DIRECTION OUTPUT ;
    USE SIGNAL ;
    PORT
      LAYER M5 ;
        RECT  101.376 11.688 101.4 11.88 ;
    END
  END q[526]
  PIN q[527]
    DIRECTION OUTPUT ;
    USE SIGNAL ;
    PORT
      LAYER M5 ;
        RECT  101.568 11.688 101.592 11.88 ;
    END
  END q[527]
  PIN q[528]
    DIRECTION OUTPUT ;
    USE SIGNAL ;
    PORT
      LAYER M5 ;
        RECT  101.76 11.688 101.784 11.88 ;
    END
  END q[528]
  PIN q[529]
    DIRECTION OUTPUT ;
    USE SIGNAL ;
    PORT
      LAYER M5 ;
        RECT  101.952 11.688 101.976 11.88 ;
    END
  END q[529]
  PIN q[52]
    DIRECTION OUTPUT ;
    USE SIGNAL ;
    PORT
      LAYER M5 ;
        RECT  10.368 11.688 10.392 11.88 ;
    END
  END q[52]
  PIN q[530]
    DIRECTION OUTPUT ;
    USE SIGNAL ;
    PORT
      LAYER M5 ;
        RECT  102.144 11.688 102.168 11.88 ;
    END
  END q[530]
  PIN q[531]
    DIRECTION OUTPUT ;
    USE SIGNAL ;
    PORT
      LAYER M5 ;
        RECT  102.336 11.688 102.36 11.88 ;
    END
  END q[531]
  PIN q[532]
    DIRECTION OUTPUT ;
    USE SIGNAL ;
    PORT
      LAYER M5 ;
        RECT  102.528 11.688 102.552 11.88 ;
    END
  END q[532]
  PIN q[533]
    DIRECTION OUTPUT ;
    USE SIGNAL ;
    PORT
      LAYER M5 ;
        RECT  102.72 11.688 102.744 11.88 ;
    END
  END q[533]
  PIN q[534]
    DIRECTION OUTPUT ;
    USE SIGNAL ;
    PORT
      LAYER M5 ;
        RECT  102.912 11.688 102.936 11.88 ;
    END
  END q[534]
  PIN q[535]
    DIRECTION OUTPUT ;
    USE SIGNAL ;
    PORT
      LAYER M5 ;
        RECT  103.104 11.688 103.128 11.88 ;
    END
  END q[535]
  PIN q[536]
    DIRECTION OUTPUT ;
    USE SIGNAL ;
    PORT
      LAYER M5 ;
        RECT  103.296 11.688 103.32 11.88 ;
    END
  END q[536]
  PIN q[537]
    DIRECTION OUTPUT ;
    USE SIGNAL ;
    PORT
      LAYER M5 ;
        RECT  103.488 11.688 103.512 11.88 ;
    END
  END q[537]
  PIN q[538]
    DIRECTION OUTPUT ;
    USE SIGNAL ;
    PORT
      LAYER M5 ;
        RECT  103.68 11.688 103.704 11.88 ;
    END
  END q[538]
  PIN q[539]
    DIRECTION OUTPUT ;
    USE SIGNAL ;
    PORT
      LAYER M5 ;
        RECT  103.872 11.688 103.896 11.88 ;
    END
  END q[539]
  PIN q[53]
    DIRECTION OUTPUT ;
    USE SIGNAL ;
    PORT
      LAYER M5 ;
        RECT  10.56 11.688 10.584 11.88 ;
    END
  END q[53]
  PIN q[540]
    DIRECTION OUTPUT ;
    USE SIGNAL ;
    PORT
      LAYER M5 ;
        RECT  104.064 11.688 104.088 11.88 ;
    END
  END q[540]
  PIN q[541]
    DIRECTION OUTPUT ;
    USE SIGNAL ;
    PORT
      LAYER M5 ;
        RECT  104.256 11.688 104.28 11.88 ;
    END
  END q[541]
  PIN q[542]
    DIRECTION OUTPUT ;
    USE SIGNAL ;
    PORT
      LAYER M5 ;
        RECT  104.448 11.688 104.472 11.88 ;
    END
  END q[542]
  PIN q[543]
    DIRECTION OUTPUT ;
    USE SIGNAL ;
    PORT
      LAYER M5 ;
        RECT  104.64 11.688 104.664 11.88 ;
    END
  END q[543]
  PIN q[54]
    DIRECTION OUTPUT ;
    USE SIGNAL ;
    PORT
      LAYER M5 ;
        RECT  10.752 11.688 10.776 11.88 ;
    END
  END q[54]
  PIN q[55]
    DIRECTION OUTPUT ;
    USE SIGNAL ;
    PORT
      LAYER M5 ;
        RECT  10.944 11.688 10.968 11.88 ;
    END
  END q[55]
  PIN q[56]
    DIRECTION OUTPUT ;
    USE SIGNAL ;
    PORT
      LAYER M5 ;
        RECT  11.136 11.688 11.16 11.88 ;
    END
  END q[56]
  PIN q[57]
    DIRECTION OUTPUT ;
    USE SIGNAL ;
    PORT
      LAYER M5 ;
        RECT  11.328 11.688 11.352 11.88 ;
    END
  END q[57]
  PIN q[58]
    DIRECTION OUTPUT ;
    USE SIGNAL ;
    PORT
      LAYER M5 ;
        RECT  11.52 11.688 11.544 11.88 ;
    END
  END q[58]
  PIN q[59]
    DIRECTION OUTPUT ;
    USE SIGNAL ;
    PORT
      LAYER M5 ;
        RECT  11.712 11.688 11.736 11.88 ;
    END
  END q[59]
  PIN q[5]
    DIRECTION OUTPUT ;
    USE SIGNAL ;
    PORT
      LAYER M5 ;
        RECT  1.344 11.688 1.368 11.88 ;
    END
  END q[5]
  PIN q[60]
    DIRECTION OUTPUT ;
    USE SIGNAL ;
    PORT
      LAYER M5 ;
        RECT  11.904 11.688 11.928 11.88 ;
    END
  END q[60]
  PIN q[61]
    DIRECTION OUTPUT ;
    USE SIGNAL ;
    PORT
      LAYER M5 ;
        RECT  12.096 11.688 12.12 11.88 ;
    END
  END q[61]
  PIN q[62]
    DIRECTION OUTPUT ;
    USE SIGNAL ;
    PORT
      LAYER M5 ;
        RECT  12.288 11.688 12.312 11.88 ;
    END
  END q[62]
  PIN q[63]
    DIRECTION OUTPUT ;
    USE SIGNAL ;
    PORT
      LAYER M5 ;
        RECT  12.48 11.688 12.504 11.88 ;
    END
  END q[63]
  PIN q[64]
    DIRECTION OUTPUT ;
    USE SIGNAL ;
    PORT
      LAYER M5 ;
        RECT  12.672 11.688 12.696 11.88 ;
    END
  END q[64]
  PIN q[65]
    DIRECTION OUTPUT ;
    USE SIGNAL ;
    PORT
      LAYER M5 ;
        RECT  12.864 11.688 12.888 11.88 ;
    END
  END q[65]
  PIN q[66]
    DIRECTION OUTPUT ;
    USE SIGNAL ;
    PORT
      LAYER M5 ;
        RECT  13.056 11.688 13.08 11.88 ;
    END
  END q[66]
  PIN q[67]
    DIRECTION OUTPUT ;
    USE SIGNAL ;
    PORT
      LAYER M5 ;
        RECT  13.248 11.688 13.272 11.88 ;
    END
  END q[67]
  PIN q[68]
    DIRECTION OUTPUT ;
    USE SIGNAL ;
    PORT
      LAYER M5 ;
        RECT  13.44 11.688 13.464 11.88 ;
    END
  END q[68]
  PIN q[69]
    DIRECTION OUTPUT ;
    USE SIGNAL ;
    PORT
      LAYER M5 ;
        RECT  13.632 11.688 13.656 11.88 ;
    END
  END q[69]
  PIN q[6]
    DIRECTION OUTPUT ;
    USE SIGNAL ;
    PORT
      LAYER M5 ;
        RECT  1.536 11.688 1.56 11.88 ;
    END
  END q[6]
  PIN q[70]
    DIRECTION OUTPUT ;
    USE SIGNAL ;
    PORT
      LAYER M5 ;
        RECT  13.824 11.688 13.848 11.88 ;
    END
  END q[70]
  PIN q[71]
    DIRECTION OUTPUT ;
    USE SIGNAL ;
    PORT
      LAYER M5 ;
        RECT  14.016 11.688 14.04 11.88 ;
    END
  END q[71]
  PIN q[72]
    DIRECTION OUTPUT ;
    USE SIGNAL ;
    PORT
      LAYER M5 ;
        RECT  14.208 11.688 14.232 11.88 ;
    END
  END q[72]
  PIN q[73]
    DIRECTION OUTPUT ;
    USE SIGNAL ;
    PORT
      LAYER M5 ;
        RECT  14.4 11.688 14.424 11.88 ;
    END
  END q[73]
  PIN q[74]
    DIRECTION OUTPUT ;
    USE SIGNAL ;
    PORT
      LAYER M5 ;
        RECT  14.592 11.688 14.616 11.88 ;
    END
  END q[74]
  PIN q[75]
    DIRECTION OUTPUT ;
    USE SIGNAL ;
    PORT
      LAYER M5 ;
        RECT  14.784 11.688 14.808 11.88 ;
    END
  END q[75]
  PIN q[76]
    DIRECTION OUTPUT ;
    USE SIGNAL ;
    PORT
      LAYER M5 ;
        RECT  14.976 11.688 15 11.88 ;
    END
  END q[76]
  PIN q[77]
    DIRECTION OUTPUT ;
    USE SIGNAL ;
    PORT
      LAYER M5 ;
        RECT  15.168 11.688 15.192 11.88 ;
    END
  END q[77]
  PIN q[78]
    DIRECTION OUTPUT ;
    USE SIGNAL ;
    PORT
      LAYER M5 ;
        RECT  15.36 11.688 15.384 11.88 ;
    END
  END q[78]
  PIN q[79]
    DIRECTION OUTPUT ;
    USE SIGNAL ;
    PORT
      LAYER M5 ;
        RECT  15.552 11.688 15.576 11.88 ;
    END
  END q[79]
  PIN q[7]
    DIRECTION OUTPUT ;
    USE SIGNAL ;
    PORT
      LAYER M5 ;
        RECT  1.728 11.688 1.752 11.88 ;
    END
  END q[7]
  PIN q[80]
    DIRECTION OUTPUT ;
    USE SIGNAL ;
    PORT
      LAYER M5 ;
        RECT  15.744 11.688 15.768 11.88 ;
    END
  END q[80]
  PIN q[81]
    DIRECTION OUTPUT ;
    USE SIGNAL ;
    PORT
      LAYER M5 ;
        RECT  15.936 11.688 15.96 11.88 ;
    END
  END q[81]
  PIN q[82]
    DIRECTION OUTPUT ;
    USE SIGNAL ;
    PORT
      LAYER M5 ;
        RECT  16.128 11.688 16.152 11.88 ;
    END
  END q[82]
  PIN q[83]
    DIRECTION OUTPUT ;
    USE SIGNAL ;
    PORT
      LAYER M5 ;
        RECT  16.32 11.688 16.344 11.88 ;
    END
  END q[83]
  PIN q[84]
    DIRECTION OUTPUT ;
    USE SIGNAL ;
    PORT
      LAYER M5 ;
        RECT  16.512 11.688 16.536 11.88 ;
    END
  END q[84]
  PIN q[85]
    DIRECTION OUTPUT ;
    USE SIGNAL ;
    PORT
      LAYER M5 ;
        RECT  16.704 11.688 16.728 11.88 ;
    END
  END q[85]
  PIN q[86]
    DIRECTION OUTPUT ;
    USE SIGNAL ;
    PORT
      LAYER M5 ;
        RECT  16.896 11.688 16.92 11.88 ;
    END
  END q[86]
  PIN q[87]
    DIRECTION OUTPUT ;
    USE SIGNAL ;
    PORT
      LAYER M5 ;
        RECT  17.088 11.688 17.112 11.88 ;
    END
  END q[87]
  PIN q[88]
    DIRECTION OUTPUT ;
    USE SIGNAL ;
    PORT
      LAYER M5 ;
        RECT  17.28 11.688 17.304 11.88 ;
    END
  END q[88]
  PIN q[89]
    DIRECTION OUTPUT ;
    USE SIGNAL ;
    PORT
      LAYER M5 ;
        RECT  17.472 11.688 17.496 11.88 ;
    END
  END q[89]
  PIN q[8]
    DIRECTION OUTPUT ;
    USE SIGNAL ;
    PORT
      LAYER M5 ;
        RECT  1.92 11.688 1.944 11.88 ;
    END
  END q[8]
  PIN q[90]
    DIRECTION OUTPUT ;
    USE SIGNAL ;
    PORT
      LAYER M5 ;
        RECT  17.664 11.688 17.688 11.88 ;
    END
  END q[90]
  PIN q[91]
    DIRECTION OUTPUT ;
    USE SIGNAL ;
    PORT
      LAYER M5 ;
        RECT  17.856 11.688 17.88 11.88 ;
    END
  END q[91]
  PIN q[92]
    DIRECTION OUTPUT ;
    USE SIGNAL ;
    PORT
      LAYER M5 ;
        RECT  18.048 11.688 18.072 11.88 ;
    END
  END q[92]
  PIN q[93]
    DIRECTION OUTPUT ;
    USE SIGNAL ;
    PORT
      LAYER M5 ;
        RECT  18.24 11.688 18.264 11.88 ;
    END
  END q[93]
  PIN q[94]
    DIRECTION OUTPUT ;
    USE SIGNAL ;
    PORT
      LAYER M5 ;
        RECT  18.432 11.688 18.456 11.88 ;
    END
  END q[94]
  PIN q[95]
    DIRECTION OUTPUT ;
    USE SIGNAL ;
    PORT
      LAYER M5 ;
        RECT  18.624 11.688 18.648 11.88 ;
    END
  END q[95]
  PIN q[96]
    DIRECTION OUTPUT ;
    USE SIGNAL ;
    PORT
      LAYER M5 ;
        RECT  18.816 11.688 18.84 11.88 ;
    END
  END q[96]
  PIN q[97]
    DIRECTION OUTPUT ;
    USE SIGNAL ;
    PORT
      LAYER M5 ;
        RECT  19.008 11.688 19.032 11.88 ;
    END
  END q[97]
  PIN q[98]
    DIRECTION OUTPUT ;
    USE SIGNAL ;
    PORT
      LAYER M5 ;
        RECT  19.2 11.688 19.224 11.88 ;
    END
  END q[98]
  PIN q[99]
    DIRECTION OUTPUT ;
    USE SIGNAL ;
    PORT
      LAYER M5 ;
        RECT  19.392 11.688 19.416 11.88 ;
    END
  END q[99]
  PIN q[9]
    DIRECTION OUTPUT ;
    USE SIGNAL ;
    PORT
      LAYER M5 ;
        RECT  2.112 11.688 2.136 11.88 ;
    END
  END q[9]
  PIN VDD
    DIRECTION INOUT ;
    USE POWER ;
    PORT
      LAYER M5 ;
        RECT  103.032 0.531 103.152 11.349 ;
        RECT  97.632 0.531 97.752 11.349 ;
        RECT  92.232 0.531 92.352 11.349 ;
        RECT  86.832 0.531 86.952 11.349 ;
        RECT  81.432 0.531 81.552 11.349 ;
        RECT  76.032 0.531 76.152 11.349 ;
        RECT  70.632 0.531 70.752 11.349 ;
        RECT  65.232 0.531 65.352 11.349 ;
        RECT  59.832 0.531 59.952 11.349 ;
        RECT  54.432 0.531 54.552 11.349 ;
        RECT  49.032 0.531 49.152 11.349 ;
        RECT  43.632 0.531 43.752 11.349 ;
        RECT  38.232 0.531 38.352 11.349 ;
        RECT  32.832 0.531 32.952 11.349 ;
        RECT  27.432 0.531 27.552 11.349 ;
        RECT  22.032 0.531 22.152 11.349 ;
        RECT  16.632 0.531 16.752 11.349 ;
        RECT  11.232 0.531 11.352 11.349 ;
        RECT  5.832 0.531 5.952 11.349 ;
        RECT  0.432 0.531 0.552 11.349 ;
      LAYER M2 ;
        RECT  105.822 11.061 105.84 11.079 ;
        RECT  0 11.061 0.018 11.079 ;
        RECT  105.822 10.521 105.84 10.539 ;
        RECT  0 10.521 0.018 10.539 ;
        RECT  105.822 9.981 105.84 9.999 ;
        RECT  0 9.981 0.018 9.999 ;
        RECT  105.822 9.441 105.84 9.459 ;
        RECT  0 9.441 0.018 9.459 ;
        RECT  105.822 8.901 105.84 8.919 ;
        RECT  0 8.901 0.018 8.919 ;
        RECT  105.822 8.361 105.84 8.379 ;
        RECT  0 8.361 0.018 8.379 ;
        RECT  105.822 7.821 105.84 7.839 ;
        RECT  0 7.821 0.018 7.839 ;
        RECT  105.822 7.281 105.84 7.299 ;
        RECT  0 7.281 0.018 7.299 ;
        RECT  105.822 6.741 105.84 6.759 ;
        RECT  0 6.741 0.018 6.759 ;
        RECT  105.822 6.201 105.84 6.219 ;
        RECT  0 6.201 0.018 6.219 ;
        RECT  105.822 5.661 105.84 5.679 ;
        RECT  0 5.661 0.018 5.679 ;
        RECT  105.822 5.121 105.84 5.139 ;
        RECT  0 5.121 0.018 5.139 ;
        RECT  105.822 4.581 105.84 4.599 ;
        RECT  0 4.581 0.018 4.599 ;
        RECT  105.822 4.041 105.84 4.059 ;
        RECT  0 4.041 0.018 4.059 ;
        RECT  105.822 3.501 105.84 3.519 ;
        RECT  0 3.501 0.018 3.519 ;
        RECT  105.822 2.961 105.84 2.979 ;
        RECT  0 2.961 0.018 2.979 ;
        RECT  105.822 2.421 105.84 2.439 ;
        RECT  0 2.421 0.018 2.439 ;
        RECT  105.822 1.881 105.84 1.899 ;
        RECT  0 1.881 0.018 1.899 ;
        RECT  105.822 1.341 105.84 1.359 ;
        RECT  0 1.341 0.018 1.359 ;
        RECT  105.822 0.801 105.84 0.819 ;
        RECT  0 0.801 0.018 0.819 ;
      LAYER M1 ;
        RECT  105.822 11.061 105.84 11.079 ;
        RECT  0 11.061 0.018 11.079 ;
        RECT  105.822 10.521 105.84 10.539 ;
        RECT  0 10.521 0.018 10.539 ;
        RECT  105.822 9.981 105.84 9.999 ;
        RECT  0 9.981 0.018 9.999 ;
        RECT  105.822 9.441 105.84 9.459 ;
        RECT  0 9.441 0.018 9.459 ;
        RECT  105.822 8.901 105.84 8.919 ;
        RECT  0 8.901 0.018 8.919 ;
        RECT  105.822 8.361 105.84 8.379 ;
        RECT  0 8.361 0.018 8.379 ;
        RECT  105.822 7.821 105.84 7.839 ;
        RECT  0 7.821 0.018 7.839 ;
        RECT  105.822 7.281 105.84 7.299 ;
        RECT  0 7.281 0.018 7.299 ;
        RECT  105.822 6.741 105.84 6.759 ;
        RECT  0 6.741 0.018 6.759 ;
        RECT  105.822 6.201 105.84 6.219 ;
        RECT  0 6.201 0.018 6.219 ;
        RECT  105.822 5.661 105.84 5.679 ;
        RECT  0 5.661 0.018 5.679 ;
        RECT  105.822 5.121 105.84 5.139 ;
        RECT  0 5.121 0.018 5.139 ;
        RECT  105.822 4.581 105.84 4.599 ;
        RECT  0 4.581 0.018 4.599 ;
        RECT  105.822 4.041 105.84 4.059 ;
        RECT  0 4.041 0.018 4.059 ;
        RECT  105.822 3.501 105.84 3.519 ;
        RECT  0 3.501 0.018 3.519 ;
        RECT  105.822 2.961 105.84 2.979 ;
        RECT  0 2.961 0.018 2.979 ;
        RECT  105.822 2.421 105.84 2.439 ;
        RECT  0 2.421 0.018 2.439 ;
        RECT  105.822 1.881 105.84 1.899 ;
        RECT  0 1.881 0.018 1.899 ;
        RECT  105.822 1.341 105.84 1.359 ;
        RECT  0 1.341 0.018 1.359 ;
        RECT  105.822 0.801 105.84 0.819 ;
        RECT  0 0.801 0.018 0.819 ;
    END
  END VDD
  PIN VSS
    DIRECTION INOUT ;
    USE GROUND ;
    PORT
      LAYER M5 ;
        RECT  102.84 0.517 102.96 11.363 ;
        RECT  97.44 0.517 97.56 11.363 ;
        RECT  92.04 0.517 92.16 11.363 ;
        RECT  86.64 0.517 86.76 11.363 ;
        RECT  81.24 0.517 81.36 11.363 ;
        RECT  75.84 0.517 75.96 11.363 ;
        RECT  70.44 0.517 70.56 11.363 ;
        RECT  65.04 0.517 65.16 11.363 ;
        RECT  59.64 0.517 59.76 11.363 ;
        RECT  54.24 0.517 54.36 11.363 ;
        RECT  48.84 0.517 48.96 11.363 ;
        RECT  43.44 0.517 43.56 11.363 ;
        RECT  38.04 0.517 38.16 11.363 ;
        RECT  32.64 0.517 32.76 11.363 ;
        RECT  27.24 0.517 27.36 11.363 ;
        RECT  21.84 0.517 21.96 11.363 ;
        RECT  16.44 0.517 16.56 11.363 ;
        RECT  11.04 0.517 11.16 11.363 ;
        RECT  5.64 0.517 5.76 11.363 ;
        RECT  0.24 0.517 0.36 11.363 ;
      LAYER M2 ;
        RECT  105.822 11.331 105.84 11.349 ;
        RECT  0 11.331 0.018 11.349 ;
        RECT  105.822 10.791 105.84 10.809 ;
        RECT  0 10.791 0.018 10.809 ;
        RECT  105.822 10.251 105.84 10.269 ;
        RECT  0 10.251 0.018 10.269 ;
        RECT  105.822 9.711 105.84 9.729 ;
        RECT  0 9.711 0.018 9.729 ;
        RECT  105.822 9.171 105.84 9.189 ;
        RECT  0 9.171 0.018 9.189 ;
        RECT  105.822 8.631 105.84 8.649 ;
        RECT  0 8.631 0.018 8.649 ;
        RECT  105.822 8.091 105.84 8.109 ;
        RECT  0 8.091 0.018 8.109 ;
        RECT  105.822 7.551 105.84 7.569 ;
        RECT  0 7.551 0.018 7.569 ;
        RECT  105.822 7.011 105.84 7.029 ;
        RECT  0 7.011 0.018 7.029 ;
        RECT  105.822 6.471 105.84 6.489 ;
        RECT  0 6.471 0.018 6.489 ;
        RECT  105.822 5.931 105.84 5.949 ;
        RECT  0 5.931 0.018 5.949 ;
        RECT  105.822 5.391 105.84 5.409 ;
        RECT  0 5.391 0.018 5.409 ;
        RECT  105.822 4.851 105.84 4.869 ;
        RECT  0 4.851 0.018 4.869 ;
        RECT  105.822 4.311 105.84 4.329 ;
        RECT  0 4.311 0.018 4.329 ;
        RECT  105.822 3.771 105.84 3.789 ;
        RECT  0 3.771 0.018 3.789 ;
        RECT  105.822 3.231 105.84 3.249 ;
        RECT  0 3.231 0.018 3.249 ;
        RECT  105.822 2.691 105.84 2.709 ;
        RECT  0 2.691 0.018 2.709 ;
        RECT  105.822 2.151 105.84 2.169 ;
        RECT  0 2.151 0.018 2.169 ;
        RECT  105.822 1.611 105.84 1.629 ;
        RECT  0 1.611 0.018 1.629 ;
        RECT  105.822 1.071 105.84 1.089 ;
        RECT  0 1.071 0.018 1.089 ;
        RECT  105.822 0.531 105.84 0.549 ;
        RECT  0 0.531 0.018 0.549 ;
      LAYER M1 ;
        RECT  105.822 11.331 105.84 11.349 ;
        RECT  0 11.331 0.018 11.349 ;
        RECT  105.822 10.791 105.84 10.809 ;
        RECT  0 10.791 0.018 10.809 ;
        RECT  105.822 10.251 105.84 10.269 ;
        RECT  0 10.251 0.018 10.269 ;
        RECT  105.822 9.711 105.84 9.729 ;
        RECT  0 9.711 0.018 9.729 ;
        RECT  105.822 9.171 105.84 9.189 ;
        RECT  0 9.171 0.018 9.189 ;
        RECT  105.822 8.631 105.84 8.649 ;
        RECT  0 8.631 0.018 8.649 ;
        RECT  105.822 8.091 105.84 8.109 ;
        RECT  0 8.091 0.018 8.109 ;
        RECT  105.822 7.551 105.84 7.569 ;
        RECT  0 7.551 0.018 7.569 ;
        RECT  105.822 7.011 105.84 7.029 ;
        RECT  0 7.011 0.018 7.029 ;
        RECT  105.822 6.471 105.84 6.489 ;
        RECT  0 6.471 0.018 6.489 ;
        RECT  105.822 5.931 105.84 5.949 ;
        RECT  0 5.931 0.018 5.949 ;
        RECT  105.822 5.391 105.84 5.409 ;
        RECT  0 5.391 0.018 5.409 ;
        RECT  105.822 4.851 105.84 4.869 ;
        RECT  0 4.851 0.018 4.869 ;
        RECT  105.822 4.311 105.84 4.329 ;
        RECT  0 4.311 0.018 4.329 ;
        RECT  105.822 3.771 105.84 3.789 ;
        RECT  0 3.771 0.018 3.789 ;
        RECT  105.822 3.231 105.84 3.249 ;
        RECT  0 3.231 0.018 3.249 ;
        RECT  105.822 2.691 105.84 2.709 ;
        RECT  0 2.691 0.018 2.709 ;
        RECT  105.822 2.151 105.84 2.169 ;
        RECT  0 2.151 0.018 2.169 ;
        RECT  105.822 1.611 105.84 1.629 ;
        RECT  0 1.611 0.018 1.629 ;
        RECT  105.822 1.071 105.84 1.089 ;
        RECT  0 1.071 0.018 1.089 ;
        RECT  105.822 0.531 105.84 0.549 ;
        RECT  0 0.531 0.018 0.549 ;
    END
  END VSS
  OBS
    LAYER RVTN ;
     RECT  0 0.54 105.84 0.675 ;
     RECT  0 0.945 105.84 1.215 ;
     RECT  0 1.485 105.84 1.755 ;
     RECT  0 2.025 105.84 2.295 ;
     RECT  0 2.565 105.84 2.835 ;
     RECT  0 3.105 105.84 3.375 ;
     RECT  0 3.645 105.84 3.915 ;
     RECT  0 4.185 105.84 4.455 ;
     RECT  0 4.725 105.84 4.995 ;
     RECT  0 5.265 105.84 5.535 ;
     RECT  0 5.805 105.84 6.075 ;
     RECT  0 6.345 105.84 6.615 ;
     RECT  0 6.885 105.84 7.155 ;
     RECT  0 7.425 105.84 7.695 ;
     RECT  0 7.965 105.84 8.235 ;
     RECT  0 8.505 105.84 8.775 ;
     RECT  0 9.045 105.84 9.315 ;
     RECT  0 9.585 105.84 9.855 ;
     RECT  0 10.125 105.84 10.395 ;
     RECT  0 10.665 105.84 10.935 ;
     RECT  0 11.205 105.84 11.34 ;
    LAYER RVTP ;
     RECT  0 0.675 105.84 0.945 ;
     RECT  0 1.215 105.84 1.485 ;
     RECT  0 1.755 105.84 2.025 ;
     RECT  0 2.295 105.84 2.565 ;
     RECT  0 2.835 105.84 3.105 ;
     RECT  0 3.375 105.84 3.645 ;
     RECT  0 3.915 105.84 4.185 ;
     RECT  0 4.455 105.84 4.725 ;
     RECT  0 4.995 105.84 5.265 ;
     RECT  0 5.535 105.84 5.805 ;
     RECT  0 6.075 105.84 6.345 ;
     RECT  0 6.615 105.84 6.885 ;
     RECT  0 7.155 105.84 7.425 ;
     RECT  0 7.695 105.84 7.965 ;
     RECT  0 8.235 105.84 8.505 ;
     RECT  0 8.775 105.84 9.045 ;
     RECT  0 9.315 105.84 9.585 ;
     RECT  0 9.855 105.84 10.125 ;
     RECT  0 10.395 105.84 10.665 ;
     RECT  0 10.935 105.84 11.205 ;
    LAYER M1 ;
     RECT  0 0.531 105.84 11.349 ;
    LAYER M2 ;
     RECT  0 0.531 105.84 11.349 ;
    LAYER M3 ;
     RECT  21.672 0.187 21.69 0.235 ;
     RECT  26.856 0.187 26.874 0.235 ;
     RECT  15.408 0.187 16.002 0.283 ;
     RECT  87.012 0.187 87.354 0.283 ;
     RECT  5.364 0.187 5.382 0.379 ;
     RECT  6.192 0.187 6.894 0.379 ;
     RECT  21.672 0.235 21.798 0.379 ;
     RECT  22.86 0.187 23.202 0.379 ;
     RECT  26.856 0.235 26.982 0.379 ;
     RECT  28.116 0.187 28.134 0.379 ;
     RECT  37.836 0.187 37.854 0.379 ;
     RECT  47.628 0.187 48.366 0.379 ;
     RECT  49.644 0.187 49.662 0.379 ;
     RECT  65.52 0.187 65.826 0.379 ;
     RECT  71.316 0.187 71.334 0.379 ;
     RECT  91.008 0.187 91.422 0.379 ;
     RECT  97.164 0.187 97.29 0.379 ;
     RECT  103.104 0.187 103.122 0.379 ;
     RECT  0.396 0.379 0.414 0.523 ;
     RECT  15.408 0.283 16.434 0.523 ;
     RECT  54.18 0.187 54.198 0.523 ;
     RECT  59.796 0.379 59.814 0.523 ;
     RECT  70.596 0.379 71.334 0.523 ;
     RECT  86.796 0.283 87.354 0.523 ;
     RECT  91.008 0.379 91.998 0.523 ;
     RECT  0.255 0.523 0.414 0.571 ;
     RECT  2.124 0.187 2.538 0.571 ;
     RECT  4.068 0.187 4.086 0.571 ;
     RECT  5.364 0.379 6.894 0.571 ;
     RECT  9.252 0.187 9.918 0.571 ;
     RECT  11.016 0.187 14.634 0.571 ;
     RECT  15.408 0.523 16.545 0.571 ;
     RECT  19.404 0.187 19.422 0.571 ;
     RECT  20.376 0.187 20.394 0.571 ;
     RECT  21.672 0.379 23.202 0.571 ;
     RECT  24.12 0.187 25.002 0.571 ;
     RECT  26.856 0.379 28.134 0.571 ;
     RECT  29.844 0.187 29.862 0.571 ;
     RECT  31.5 0.187 35.154 0.571 ;
     RECT  35.928 0.187 35.946 0.571 ;
     RECT  36.756 0.187 36.774 0.571 ;
     RECT  37.836 0.379 38.214 0.571 ;
     RECT  39.6 0.187 39.618 0.571 ;
     RECT  40.5 0.187 40.518 0.571 ;
     RECT  43.056 0.187 43.686 0.571 ;
     RECT  46.296 0.187 46.314 0.571 ;
     RECT  47.628 0.379 49.662 0.571 ;
     RECT  50.796 0.187 50.814 0.571 ;
     RECT  52.452 0.187 53.406 0.571 ;
     RECT  54.18 0.523 54.345 0.571 ;
     RECT  55.872 0.187 55.89 0.571 ;
     RECT  58.284 0.187 58.302 0.571 ;
     RECT  59.655 0.523 59.814 0.571 ;
     RECT  61.452 0.187 62.046 0.571 ;
     RECT  63.432 0.187 63.45 0.571 ;
     RECT  65.016 0.379 65.826 0.571 ;
     RECT  67.86 0.187 69.534 0.571 ;
     RECT  70.455 0.523 71.334 0.571 ;
     RECT  72.432 0.187 73.062 0.571 ;
     RECT  75.672 0.187 76.77 0.571 ;
     RECT  77.58 0.187 77.598 0.571 ;
     RECT  79.74 0.187 79.758 0.571 ;
     RECT  80.892 0.187 82.566 0.571 ;
     RECT  85.248 0.187 85.698 0.571 ;
     RECT  86.655 0.523 87.354 0.571 ;
     RECT  88.164 0.187 88.542 0.571 ;
     RECT  89.28 0.187 90.162 0.571 ;
     RECT  91.008 0.523 92.145 0.571 ;
     RECT  94.104 0.187 94.122 0.571 ;
     RECT  96.192 0.187 96.21 0.571 ;
     RECT  97.164 0.379 97.614 0.571 ;
     RECT  98.64 0.187 98.658 0.571 ;
     RECT  99.54 0.187 99.558 0.571 ;
     RECT  101.124 0.187 101.934 0.571 ;
     RECT  102.816 0.379 103.122 0.571 ;
     RECT  0.255 0.571 44.046 0.607 ;
     RECT  44.856 0.571 45.414 0.607 ;
     RECT  46.152 0.571 74.61 0.607 ;
     RECT  75.672 0.571 94.482 0.607 ;
     RECT  75.456 0.607 94.482 0.679 ;
     RECT  95.22 0.571 104.814 0.679 ;
     RECT  0.255 0.607 74.61 0.751 ;
     RECT  75.456 0.679 104.814 0.751 ;
     RECT  0.255 0.751 104.994 0.905 ;
     RECT  0.255 0.905 104.706 1.445 ;
     RECT  0.255 1.445 104.67 2.371 ;
     RECT  0.255 2.371 105.066 2.669 ;
     RECT  0.255 2.669 104.886 2.795 ;
     RECT  0.255 2.795 104.742 4.559 ;
     RECT  0.255 4.559 98.586 5.459 ;
     RECT  55.872 5.459 98.586 5.539 ;
     RECT  99.324 4.559 104.742 5.539 ;
     RECT  55.872 5.539 104.742 5.611 ;
     RECT  55.872 5.611 104.994 5.909 ;
     RECT  75.672 5.909 104.994 6.179 ;
     RECT  0.255 5.459 55.098 6.421 ;
     RECT  55.872 5.909 74.862 6.421 ;
     RECT  0.255 6.421 74.862 6.691 ;
     RECT  75.672 6.179 104.742 6.691 ;
     RECT  0.255 6.691 104.742 7.079 ;
     RECT  0.255 7.079 33.102 7.115 ;
     RECT  34.056 7.079 104.742 7.421 ;
     RECT  34.056 7.421 82.566 8.311 ;
     RECT  83.34 7.421 104.742 8.311 ;
     RECT  34.056 8.311 104.742 8.437 ;
     RECT  33.948 8.437 104.742 8.573 ;
     RECT  0.255 7.115 33.03 8.941 ;
     RECT  34.056 8.573 104.742 9.101 ;
     RECT  0.255 8.941 33.066 9.149 ;
     RECT  34.056 9.101 100.278 9.149 ;
     RECT  46.944 9.149 73.494 9.245 ;
     RECT  34.056 9.149 46.206 9.275 ;
     RECT  0.255 9.149 29.79 9.677 ;
     RECT  30.708 9.149 33.066 9.677 ;
     RECT  34.056 9.275 44.226 9.677 ;
     RECT  53.568 9.245 73.494 9.677 ;
     RECT  31.824 9.677 33.066 9.851 ;
     RECT  74.376 9.149 100.278 9.923 ;
     RECT  34.056 9.677 43.794 9.931 ;
     RECT  27.144 9.677 29.79 10.201 ;
     RECT  74.376 9.923 79.542 10.201 ;
     RECT  0.255 9.677 25.974 10.205 ;
     RECT  19.728 10.205 25.974 10.253 ;
     RECT  34.02 9.931 43.794 10.253 ;
     RECT  53.568 9.677 63.81 10.253 ;
     RECT  80.28 9.923 100.278 10.253 ;
     RECT  0.255 10.205 7.686 10.315 ;
     RECT  44.964 9.275 46.206 10.315 ;
     RECT  46.944 9.245 52.686 10.315 ;
     RECT  31.824 9.851 32.937 10.319 ;
     RECT  0.252 10.315 7.686 10.355 ;
     RECT  56.34 10.253 63.81 10.355 ;
     RECT  67.68 9.677 73.494 10.363 ;
     RECT  74.304 10.201 79.542 10.363 ;
     RECT  67.68 10.363 79.542 10.397 ;
     RECT  42.12 10.253 43.794 10.435 ;
     RECT  44.964 10.315 52.686 10.435 ;
     RECT  59.364 10.355 63.81 10.471 ;
     RECT  64.836 9.677 66.726 10.471 ;
     RECT  80.532 10.253 100.278 10.471 ;
     RECT  34.02 10.253 41.202 10.499 ;
     RECT  42.12 10.435 52.686 10.541 ;
     RECT  53.568 10.253 55.458 10.561 ;
     RECT  19.728 10.253 24.894 10.589 ;
     RECT  27.144 10.201 29.97 10.589 ;
     RECT  53.46 10.561 55.458 10.589 ;
     RECT  42.12 10.541 45.882 10.625 ;
     RECT  46.62 10.541 52.686 10.625 ;
     RECT  59.364 10.471 66.798 10.625 ;
     RECT  53.46 10.589 55.242 10.685 ;
     RECT  30.708 9.677 30.942 10.741 ;
     RECT  47.268 10.625 52.686 10.741 ;
     RECT  53.46 10.685 55.206 10.741 ;
     RECT  80.532 10.471 100.386 10.741 ;
     RECT  27.144 10.589 29.862 10.769 ;
     RECT  30.708 10.741 31.05 10.781 ;
     RECT  47.268 10.741 55.206 10.781 ;
     RECT  61.488 10.625 66.798 10.781 ;
     RECT  47.268 10.781 54.99 10.829 ;
     RECT  61.524 10.781 66.798 10.829 ;
     RECT  74.556 10.397 79.542 10.829 ;
     RECT  80.532 10.741 100.458 10.829 ;
     RECT  101.268 9.101 104.742 10.829 ;
     RECT  101.268 10.829 103.23 10.859 ;
     RECT  0.255 10.355 7.686 10.877 ;
     RECT  8.568 10.205 18.954 10.877 ;
     RECT  19.728 10.589 24.858 10.877 ;
     RECT  30.708 10.781 30.726 10.877 ;
     RECT  34.02 10.499 34.506 10.877 ;
     RECT  35.604 10.499 41.202 10.877 ;
     RECT  42.192 10.625 45.882 10.877 ;
     RECT  56.34 10.355 58.374 10.877 ;
     RECT  61.524 10.829 65.43 10.877 ;
     RECT  67.68 10.397 73.602 10.877 ;
     RECT  74.556 10.829 79.434 10.877 ;
     RECT  80.964 10.829 100.458 10.877 ;
     RECT  104.436 10.829 104.742 10.877 ;
     RECT  35.748 10.877 40.734 10.895 ;
     RECT  42.192 10.877 44.946 10.895 ;
     RECT  56.34 10.877 58.23 10.895 ;
     RECT  66.384 10.829 66.798 10.895 ;
     RECT  85.608 10.877 85.698 10.895 ;
     RECT  0.255 10.877 2.25 10.925 ;
     RECT  27.216 10.769 29.862 10.925 ;
     RECT  35.748 10.895 38.826 10.925 ;
     RECT  80.964 10.877 84.618 10.925 ;
     RECT  99.288 10.877 99.63 10.925 ;
     RECT  101.268 10.859 103.194 10.925 ;
     RECT  77.544 10.877 79.434 10.931 ;
     RECT  19.728 10.877 22.302 10.973 ;
     RECT  34.056 10.877 34.506 10.973 ;
     RECT  86.544 10.877 98.01 10.973 ;
     RECT  36.792 10.925 38.826 11.003 ;
     RECT  13.32 10.877 18.954 11.011 ;
     RECT  31.932 10.319 32.937 11.011 ;
     RECT  66.456 10.895 66.798 11.011 ;
     RECT  67.68 10.877 68.742 11.011 ;
     RECT  13.32 11.011 19.458 11.021 ;
     RECT  99.288 10.925 99.594 11.021 ;
     RECT  3.06 10.877 7.686 11.069 ;
     RECT  8.568 10.877 12.582 11.069 ;
     RECT  18.036 11.021 19.458 11.069 ;
     RECT  36.792 11.003 38.79 11.069 ;
     RECT  42.408 10.895 44.946 11.069 ;
     RECT  63.792 10.877 65.43 11.069 ;
     RECT  66.456 11.011 68.742 11.069 ;
     RECT  80.964 10.925 84.294 11.069 ;
     RECT  85.68 10.895 85.698 11.069 ;
     RECT  100.44 10.877 100.458 11.069 ;
     RECT  8.568 11.069 11.337 11.087 ;
     RECT  36.792 11.069 38.337 11.087 ;
     RECT  74.556 10.877 76.137 11.087 ;
     RECT  8.568 11.087 11.214 11.129 ;
     RECT  18.036 11.069 18.198 11.129 ;
     RECT  18.936 11.069 19.458 11.129 ;
     RECT  23.4 10.877 24.858 11.129 ;
     RECT  42.48 11.069 44.946 11.129 ;
     RECT  66.492 11.069 66.69 11.129 ;
     RECT  67.428 11.069 68.742 11.129 ;
     RECT  13.32 11.021 17.226 11.165 ;
     RECT  19.044 11.129 19.458 11.165 ;
     RECT  20.376 10.973 22.302 11.165 ;
     RECT  25.848 10.253 25.974 11.165 ;
     RECT  34.488 10.973 34.506 11.165 ;
     RECT  36.792 11.087 38.145 11.165 ;
     RECT  39.888 10.895 40.734 11.165 ;
     RECT  42.624 11.129 44.946 11.165 ;
     RECT  47.268 10.829 47.898 11.165 ;
     RECT  48.708 10.829 54.99 11.165 ;
     RECT  59.364 10.625 60.714 11.165 ;
     RECT  62.388 10.877 62.982 11.165 ;
     RECT  63.792 11.069 63.954 11.165 ;
     RECT  66.492 11.129 66.51 11.165 ;
     RECT  69.912 10.877 72.198 11.165 ;
     RECT  74.556 11.087 75.945 11.165 ;
     RECT  77.544 10.931 78.462 11.165 ;
     RECT  79.308 10.931 79.434 11.165 ;
     RECT  80.964 11.069 84.258 11.165 ;
     RECT  86.544 10.973 90.162 11.165 ;
     RECT  91.332 10.973 98.01 11.165 ;
     RECT  99.288 11.021 99.414 11.165 ;
     RECT  101.664 10.925 103.194 11.165 ;
     RECT  45.684 10.877 45.882 11.201 ;
     RECT  48.816 11.165 52.614 11.201 ;
     RECT  59.436 11.165 60.714 11.201 ;
     RECT  89.28 11.165 90.162 11.201 ;
     RECT  101.772 11.165 103.194 11.201 ;
     RECT  10.836 11.129 11.145 11.213 ;
     RECT  42.624 11.165 42.642 11.237 ;
     RECT  3.78 11.069 7.686 11.273 ;
     RECT  8.568 11.129 9.918 11.273 ;
     RECT  27.255 10.925 29.862 11.273 ;
     RECT  56.448 10.895 58.23 11.273 ;
     RECT  104.436 10.877 104.526 11.273 ;
     RECT  8.568 11.273 9.126 11.281 ;
     RECT  31.932 11.011 33.21 11.281 ;
     RECT  35.748 10.925 36.054 11.309 ;
     RECT  0.255 10.925 1.854 11.357 ;
     RECT  3.78 11.273 5.958 11.357 ;
     RECT  6.696 11.273 7.686 11.357 ;
     RECT  8.46 11.281 9.126 11.357 ;
     RECT  9.9 11.273 9.918 11.357 ;
     RECT  10.98 11.213 11.145 11.357 ;
     RECT  13.428 11.165 15.498 11.357 ;
     RECT  16.308 11.165 17.226 11.357 ;
     RECT  19.152 11.165 19.458 11.357 ;
     RECT  20.556 11.165 22.302 11.357 ;
     RECT  23.76 11.129 24.858 11.357 ;
     RECT  25.956 11.165 25.974 11.357 ;
     RECT  27.255 11.273 27.702 11.357 ;
     RECT  28.44 11.273 29.862 11.357 ;
     RECT  31.5 11.281 33.318 11.357 ;
     RECT  34.596 11.281 34.614 11.357 ;
     RECT  35.748 11.309 35.766 11.357 ;
     RECT  36.936 11.165 38.145 11.357 ;
     RECT  39.888 11.165 39.906 11.357 ;
     RECT  40.716 11.165 40.734 11.357 ;
     RECT  44.64 11.165 44.946 11.357 ;
     RECT  45.684 11.201 45.702 11.357 ;
     RECT  47.34 11.165 47.898 11.357 ;
     RECT  48.816 11.201 52.47 11.357 ;
     RECT  53.388 11.165 54.99 11.357 ;
     RECT  56.448 11.273 58.158 11.357 ;
     RECT  59.436 11.201 60.462 11.357 ;
     RECT  62.532 11.165 62.982 11.357 ;
     RECT  63.936 11.165 63.954 11.357 ;
     RECT  65.055 11.069 65.43 11.357 ;
     RECT  67.644 11.129 68.742 11.357 ;
     RECT  70.455 11.165 72.198 11.357 ;
     RECT  74.664 11.165 75.945 11.357 ;
     RECT  77.76 11.165 78.462 11.357 ;
     RECT  79.416 11.165 79.434 11.357 ;
     RECT  80.964 11.165 81.954 11.357 ;
     RECT  82.764 11.165 84.258 11.357 ;
     RECT  86.544 11.165 88.47 11.357 ;
     RECT  89.28 11.201 89.55 11.357 ;
     RECT  91.476 11.165 92.394 11.357 ;
     RECT  93.132 11.165 95.742 11.357 ;
     RECT  96.552 11.165 98.01 11.357 ;
     RECT  99.396 11.165 99.414 11.357 ;
     RECT  101.772 11.201 102.078 11.357 ;
     RECT  102.855 11.201 103.194 11.357 ;
     RECT  104.508 11.273 104.526 11.357 ;
     RECT  1.836 11.357 1.854 11.405 ;
     RECT  7.128 11.357 7.146 11.405 ;
     RECT  19.44 11.357 19.458 11.405 ;
     RECT  28.8 11.357 28.818 11.405 ;
     RECT  29.664 11.357 29.682 11.405 ;
     RECT  47.628 11.357 47.646 11.405 ;
     RECT  51.804 11.357 52.47 11.405 ;
     RECT  77.76 11.357 77.778 11.405 ;
     RECT  83.7 11.357 83.718 11.405 ;
     RECT  88.452 11.357 88.47 11.405 ;
     RECT  97.236 11.357 97.83 11.405 ;
     RECT  102.06 11.357 102.078 11.405 ;
     RECT  21.816 11.357 22.302 11.453 ;
     RECT  54.216 11.357 54.234 11.453 ;
     RECT  59.436 11.357 59.814 11.453 ;
     RECT  81.612 11.357 81.63 11.453 ;
     RECT  0.54 11.357 0.99 11.501 ;
     RECT  5.796 11.357 5.958 11.501 ;
     RECT  17.208 11.357 17.226 11.501 ;
     RECT  22.284 11.453 22.302 11.501 ;
     RECT  27.648 11.357 27.666 11.501 ;
     RECT  32.508 11.357 33.318 11.501 ;
     RECT  43.416 11.165 43.794 11.501 ;
     RECT  48.816 11.357 49.266 11.501 ;
     RECT  59.436 11.453 59.454 11.501 ;
     RECT  86.544 11.357 86.562 11.501 ;
     RECT  97.74 11.405 97.83 11.501 ;
     RECT  103.176 11.357 103.194 11.501 ;
     RECT  0.972 11.501 0.99 11.549 ;
     RECT  10.98 11.357 10.998 11.549 ;
     RECT  65.412 11.357 65.43 11.549 ;
     RECT  91.944 11.357 92.394 11.549 ;
     RECT  97.74 11.501 97.758 11.549 ;
     RECT  30.564 11.659 30.582 11.789 ;
     RECT  33.588 11.659 33.606 11.789 ;
     RECT  51.804 11.405 51.822 11.789 ;
    LAYER M4 ;
     RECT  0.133 5.928 0.248 6.072 ;
     RECT  0.133 9.072 0.248 9.096 ;
     RECT  0.133 10.32 0.248 10.344 ;
     RECT  0.248 0.528 0.373 11.352 ;
     RECT  0.373 0.384 0.544 11.496 ;
     RECT  0.544 0.384 0.565 1.176 ;
     RECT  0.544 10.752 0.565 11.496 ;
     RECT  0.565 0.192 0.707 1.176 ;
     RECT  0.544 7.728 0.851 7.896 ;
     RECT  0.544 5.952 0.857 6.696 ;
     RECT  0.565 10.752 1.001 11.544 ;
     RECT  0.707 0.576 1.187 1.176 ;
     RECT  1.001 10.752 1.187 11.4 ;
     RECT  0.544 3.84 1.475 4.584 ;
     RECT  0.544 2.352 1.523 2.856 ;
     RECT  1.523 2.352 1.715 2.712 ;
     RECT  1.187 10.848 1.865 11.4 ;
     RECT  1.187 0.576 2.101 0.648 ;
     RECT  0.857 5.952 2.101 6.072 ;
     RECT  1.715 2.688 2.195 2.712 ;
     RECT  2.101 0.192 2.293 0.648 ;
     RECT  1.865 10.848 2.293 10.92 ;
     RECT  0.544 9.072 2.389 9.096 ;
     RECT  2.293 10.224 2.389 10.92 ;
     RECT  2.389 9.072 2.441 10.92 ;
     RECT  2.293 0.192 2.549 1.176 ;
     RECT  1.753 7.44 2.677 7.464 ;
     RECT  1.475 3.84 2.689 3.864 ;
     RECT  2.441 9.072 2.693 9.816 ;
     RECT  2.689 3.408 2.729 3.864 ;
     RECT  2.677 7.392 2.773 7.464 ;
     RECT  2.441 10.848 3.049 10.92 ;
     RECT  2.729 3.408 3.193 3.432 ;
     RECT  2.101 5.616 3.205 6.072 ;
     RECT  3.205 5.088 3.269 6.072 ;
     RECT  2.773 7.392 3.373 7.752 ;
     RECT  3.373 7.2 3.377 7.752 ;
     RECT  3.377 7.2 3.443 7.224 ;
     RECT  2.549 0.576 3.541 1.176 ;
     RECT  3.193 2.928 3.541 3.432 ;
     RECT  3.049 10.848 3.629 11.064 ;
     RECT  3.629 11.04 3.637 11.064 ;
     RECT  3.269 5.712 3.683 6.072 ;
     RECT  2.693 9.648 3.829 9.816 ;
     RECT  3.829 9.12 3.989 9.816 ;
     RECT  3.541 0.576 4.021 3.432 ;
     RECT  4.021 0.192 4.025 3.432 ;
     RECT  4.025 0.192 4.097 1.176 ;
     RECT  4.097 0.576 4.385 1.176 ;
     RECT  4.025 2.208 4.673 3.432 ;
     RECT  3.683 6.048 4.693 6.072 ;
     RECT  4.405 8.544 4.849 8.568 ;
     RECT  4.673 2.304 4.885 3.432 ;
     RECT  4.693 5.856 4.885 6.072 ;
     RECT  3.989 9.792 5.173 9.816 ;
     RECT  4.385 0.576 5.353 1.08 ;
     RECT  4.849 8.4 5.365 8.568 ;
     RECT  5.173 9.696 5.365 9.816 ;
     RECT  5.353 0.192 5.461 1.08 ;
     RECT  3.637 11.04 5.461 11.352 ;
     RECT  5.365 8.4 5.569 9.816 ;
     RECT  5.461 11.04 5.569 11.496 ;
     RECT  5.461 0.192 5.648 1.176 ;
     RECT  4.885 2.304 5.648 3.528 ;
     RECT  4.885 5.856 5.648 6.84 ;
     RECT  5.569 8.4 5.648 11.496 ;
     RECT  5.648 0.192 5.944 11.496 ;
     RECT  5.944 10.176 5.987 11.496 ;
     RECT  5.944 0.192 6.083 1.704 ;
     RECT  5.944 5.856 6.227 6.312 ;
     RECT  5.944 3.216 6.689 4.152 ;
     RECT  5.944 9.12 6.833 9.144 ;
     RECT  6.227 5.856 6.869 6.072 ;
     RECT  6.689 4.128 6.899 4.152 ;
     RECT  6.083 0.192 6.947 1.176 ;
     RECT  6.869 5.904 6.947 6.072 ;
     RECT  5.987 10.176 7.049 11.4 ;
     RECT  7.049 10.176 7.093 10.2 ;
     RECT  7.049 11.328 7.157 11.4 ;
     RECT  7.261 2.352 7.379 2.376 ;
     RECT  7.405 8.208 7.573 8.232 ;
     RECT  7.573 8.016 7.625 8.232 ;
     RECT  7.093 9.552 7.913 10.2 ;
     RECT  7.913 9.648 7.949 10.2 ;
     RECT  6.947 6.048 7.957 6.072 ;
     RECT  7.957 6.048 7.981 6.744 ;
     RECT  7.949 9.696 8.201 10.2 ;
     RECT  7.981 6.048 8.449 6.84 ;
     RECT  8.449 6.048 8.531 6.888 ;
     RECT  8.201 10.176 8.593 10.2 ;
     RECT  8.725 4.128 8.813 4.152 ;
     RECT  6.947 0.576 9.059 1.176 ;
     RECT  8.485 2.784 9.133 2.808 ;
     RECT  9.059 0.576 9.205 0.792 ;
     RECT  8.531 6.048 9.277 6.84 ;
     RECT  9.133 2.352 9.347 2.808 ;
     RECT  9.277 5.616 9.347 6.84 ;
     RECT  8.593 10.176 9.397 10.296 ;
     RECT  8.245 8.544 9.421 8.568 ;
     RECT  9.421 8.16 9.491 8.568 ;
     RECT  9.347 6.048 9.565 6.84 ;
     RECT  9.565 6.048 9.587 7.464 ;
     RECT  9.397 9.648 9.589 10.296 ;
     RECT  9.587 7.44 9.635 7.464 ;
     RECT  9.589 9.12 9.677 10.296 ;
     RECT  9.457 2.928 9.683 2.952 ;
     RECT  9.685 3.936 9.817 3.96 ;
     RECT  9.817 3.936 9.875 4.248 ;
     RECT  9.205 0.192 10.019 0.792 ;
     RECT  10.019 0.576 10.069 0.792 ;
     RECT  9.677 9.648 10.105 10.296 ;
     RECT  9.587 6.048 10.357 6.072 ;
     RECT  10.105 9.648 10.357 10.344 ;
     RECT  7.157 11.328 10.357 11.352 ;
     RECT  10.069 0.576 10.645 1.176 ;
     RECT  10.645 0.576 10.885 1.8 ;
     RECT  9.875 3.936 10.885 4.152 ;
     RECT  10.357 9.648 10.885 11.352 ;
     RECT  10.837 8.16 10.933 8.184 ;
     RECT  10.885 9.6 10.969 11.496 ;
     RECT  10.885 0.576 11.005 2.712 ;
     RECT  11.005 0.192 11.048 2.712 ;
     RECT  10.885 3.936 11.048 4.536 ;
     RECT  10.357 5.616 11.048 6.072 ;
     RECT  10.933 7.872 11.048 8.184 ;
     RECT  10.969 9.6 11.048 11.544 ;
     RECT  11.048 0.192 11.344 11.544 ;
     RECT  11.344 9.12 11.363 11.544 ;
     RECT  11.344 4.08 11.477 4.536 ;
     RECT  11.344 0.192 11.657 1.176 ;
     RECT  11.657 0.192 11.909 0.792 ;
     RECT  11.363 9.12 11.909 11.064 ;
     RECT  11.909 9.12 11.939 9.864 ;
     RECT  12.337 2.496 12.419 2.52 ;
     RECT  11.939 9.504 12.485 9.864 ;
     RECT  11.344 6.048 12.709 6.072 ;
     RECT  12.709 5.952 12.853 6.072 ;
     RECT  12.337 3.984 12.877 4.008 ;
     RECT  12.877 3.984 12.947 4.536 ;
     RECT  11.909 0.192 13.021 0.6 ;
     RECT  12.485 9.504 13.045 9.528 ;
     RECT  13.021 0.192 13.091 1.176 ;
     RECT  13.045 9.12 13.097 9.528 ;
     RECT  11.909 10.848 13.283 11.064 ;
     RECT  13.309 8.4 13.379 8.424 ;
     RECT  12.853 5.664 13.429 6.072 ;
     RECT  13.429 5.328 13.493 6.072 ;
     RECT  12.947 3.984 13.667 4.008 ;
     RECT  13.097 9.504 13.813 9.528 ;
     RECT  13.813 9.504 13.997 10.248 ;
     RECT  13.493 6.048 14.137 6.072 ;
     RECT  14.137 6.048 14.195 6.792 ;
     RECT  13.091 0.192 14.317 0.6 ;
     RECT  13.417 11.328 14.353 11.352 ;
     RECT  14.341 8.4 14.429 8.424 ;
     RECT  14.569 4.512 14.629 4.536 ;
     RECT  14.629 4.512 14.641 4.68 ;
     RECT  14.629 2.784 14.681 2.808 ;
     RECT  14.641 4.08 14.681 4.68 ;
     RECT  14.681 4.08 14.723 4.536 ;
     RECT  14.723 4.512 14.819 4.536 ;
     RECT  14.317 0.192 14.917 1.176 ;
     RECT  13.997 9.504 14.965 9.528 ;
     RECT  14.917 0.192 15.005 2.136 ;
     RECT  15.181 3.36 15.251 3.384 ;
     RECT  14.195 6.048 15.301 6.072 ;
     RECT  15.301 6.048 15.365 6.264 ;
     RECT  15.685 8.448 15.733 8.472 ;
     RECT  14.965 9.504 15.733 9.672 ;
     RECT  15.365 6.048 15.829 6.072 ;
     RECT  15.685 4.56 15.973 4.584 ;
     RECT  15.005 0.192 16.013 1.176 ;
     RECT  15.829 2.832 16.069 2.856 ;
     RECT  16.069 2.208 16.213 2.856 ;
     RECT  15.973 3.984 16.213 4.584 ;
     RECT  16.013 0.288 16.448 1.176 ;
     RECT  16.213 2.208 16.448 4.584 ;
     RECT  15.829 5.904 16.448 6.072 ;
     RECT  15.973 7.44 16.448 7.464 ;
     RECT  15.733 8.448 16.448 9.672 ;
     RECT  14.353 10.848 16.448 11.352 ;
     RECT  16.448 0.288 16.501 11.352 ;
     RECT  16.501 0.288 16.693 11.496 ;
     RECT  16.693 0.288 16.744 11.544 ;
     RECT  16.744 0.288 16.883 1.176 ;
     RECT  16.744 4.08 16.883 6.744 ;
     RECT  16.744 8.448 16.883 11.544 ;
     RECT  16.883 9.504 17.165 11.496 ;
     RECT  16.744 2.304 17.219 2.328 ;
     RECT  17.165 10.224 17.237 11.496 ;
     RECT  16.883 5.616 17.315 6.744 ;
     RECT  17.237 10.224 17.381 11.016 ;
     RECT  17.381 10.512 17.525 11.016 ;
     RECT  16.883 0.576 17.845 1.08 ;
     RECT  17.845 0.576 17.891 1.752 ;
     RECT  17.917 2.736 17.987 2.76 ;
     RECT  18.061 8.976 18.131 9 ;
     RECT  17.315 5.616 18.493 6.072 ;
     RECT  18.493 5.616 18.517 6.312 ;
     RECT  18.517 5.424 18.569 6.312 ;
     RECT  18.229 8.544 18.569 8.568 ;
     RECT  17.525 10.8 18.613 11.016 ;
     RECT  16.883 4.08 18.709 4.104 ;
     RECT  18.709 3.504 18.755 4.104 ;
     RECT  18.569 6.048 18.755 6.312 ;
     RECT  18.613 10.8 18.781 11.064 ;
     RECT  18.755 3.792 18.805 4.104 ;
     RECT  18.781 10.224 18.805 11.064 ;
     RECT  17.891 0.576 18.857 1.608 ;
     RECT  18.805 3.792 18.893 4.296 ;
     RECT  18.805 10.224 18.997 11.352 ;
     RECT  18.893 3.792 19.187 3.816 ;
     RECT  18.857 0.576 19.381 1.176 ;
     RECT  18.997 10.224 19.381 11.4 ;
     RECT  19.189 9.12 19.397 9.144 ;
     RECT  19.381 10.176 19.469 11.4 ;
     RECT  19.469 10.176 19.897 10.968 ;
     RECT  19.681 7.44 19.907 7.464 ;
     RECT  18.755 6.048 19.957 6.072 ;
     RECT  19.957 6.048 20.117 6.264 ;
     RECT  19.969 4.8 20.185 4.824 ;
     RECT  19.957 8.544 20.225 8.568 ;
     RECT  20.185 4.32 20.243 4.824 ;
     RECT  19.381 0.192 20.405 1.176 ;
     RECT  19.897 9.648 20.513 10.968 ;
     RECT  20.513 9.888 20.533 10.968 ;
     RECT  20.533 8.448 20.585 8.472 ;
     RECT  20.117 6.048 20.653 6.072 ;
     RECT  20.533 9.888 21.301 11.352 ;
     RECT  20.653 5.088 21.625 6.072 ;
     RECT  21.085 2.256 21.637 2.28 ;
     RECT  21.337 3.648 21.637 3.672 ;
     RECT  21.301 9.888 21.637 11.448 ;
     RECT  20.405 0.576 21.661 1.176 ;
     RECT  21.661 0.192 21.731 1.176 ;
     RECT  21.637 8.304 21.733 8.328 ;
     RECT  21.731 0.24 21.848 1.176 ;
     RECT  21.637 2.256 21.848 3.672 ;
     RECT  21.625 5.088 21.848 6.936 ;
     RECT  21.733 8.304 21.848 8.472 ;
     RECT  21.637 9.888 21.848 11.544 ;
     RECT  21.848 0.24 22.115 11.544 ;
     RECT  22.115 0.24 22.144 11.496 ;
     RECT  22.144 2.256 22.169 4.536 ;
     RECT  22.144 5.76 22.259 6.264 ;
     RECT  22.144 9.12 22.313 11.496 ;
     RECT  22.169 2.256 22.529 2.376 ;
     RECT  22.144 7.44 22.529 7.464 ;
     RECT  22.529 2.352 22.787 2.376 ;
     RECT  22.144 0.24 22.837 1.176 ;
     RECT  22.169 3.648 22.889 4.536 ;
     RECT  23.269 8.016 23.321 8.04 ;
     RECT  22.313 9.12 23.357 10.872 ;
     RECT  22.259 6.048 23.389 6.264 ;
     RECT  23.389 6.048 23.573 6.84 ;
     RECT  23.357 10.176 23.609 10.872 ;
     RECT  23.609 10.8 23.749 10.872 ;
     RECT  23.797 7.344 23.861 7.368 ;
     RECT  23.749 10.8 23.933 11.352 ;
     RECT  23.573 6.048 23.941 6.072 ;
     RECT  23.941 5.424 24.005 6.072 ;
     RECT  22.889 3.936 24.517 3.96 ;
     RECT  22.837 0.192 24.649 1.176 ;
     RECT  24.613 2.88 24.649 2.904 ;
     RECT  24.517 3.936 24.649 4.68 ;
     RECT  24.649 2.88 24.689 4.68 ;
     RECT  24.689 3.744 24.707 4.68 ;
     RECT  23.933 11.04 24.797 11.352 ;
     RECT  24.649 0.192 24.803 1.224 ;
     RECT  24.707 4.656 24.833 4.68 ;
     RECT  23.357 9.12 24.949 9.144 ;
     RECT  24.803 0.192 25.013 1.176 ;
     RECT  24.949 9.12 25.189 9.672 ;
     RECT  25.189 8.16 25.265 9.672 ;
     RECT  25.265 9.12 25.333 9.672 ;
     RECT  25.333 9.12 25.337 10.248 ;
     RECT  25.337 9.552 25.589 10.248 ;
     RECT  24.005 6.048 25.693 6.072 ;
     RECT  25.013 0.576 25.805 1.176 ;
     RECT  24.797 11.328 25.985 11.352 ;
     RECT  26.233 4.656 26.593 4.68 ;
     RECT  26.557 3.312 26.629 3.336 ;
     RECT  26.593 4.56 26.629 4.68 ;
     RECT  26.629 3.312 26.677 4.68 ;
     RECT  25.805 0.576 26.845 0.6 ;
     RECT  25.589 9.552 26.869 9.672 ;
     RECT  26.845 0.192 26.915 0.6 ;
     RECT  26.677 3.312 26.917 4.824 ;
     RECT  25.693 6.048 26.917 6.84 ;
     RECT  26.915 0.24 27.061 0.6 ;
     RECT  26.773 1.824 27.061 1.848 ;
     RECT  27.061 0.24 27.097 1.848 ;
     RECT  26.917 3.312 27.097 6.84 ;
     RECT  27.061 10.896 27.109 10.92 ;
     RECT  27.097 0.24 27.248 6.84 ;
     RECT  26.869 9.264 27.248 9.672 ;
     RECT  27.109 10.896 27.248 11.496 ;
     RECT  27.248 0.24 27.544 11.496 ;
     RECT  27.544 8.16 27.677 11.496 ;
     RECT  27.677 8.16 27.683 11.352 ;
     RECT  27.544 2.304 27.713 3.336 ;
     RECT  27.713 2.832 27.821 3.336 ;
     RECT  27.544 5.664 27.929 6.84 ;
     RECT  27.683 9.072 27.929 11.352 ;
     RECT  27.544 0.24 28.021 1.176 ;
     RECT  27.544 4.656 28.037 4.68 ;
     RECT  28.021 0.192 28.145 1.176 ;
     RECT  27.821 2.832 28.361 2.856 ;
     RECT  27.929 9.072 28.505 9.192 ;
     RECT  27.929 5.664 28.541 6.072 ;
     RECT  28.145 0.576 28.685 1.176 ;
     RECT  27.929 10.176 28.789 11.352 ;
     RECT  28.789 10.176 28.981 11.4 ;
     RECT  28.981 9.696 29.081 11.4 ;
     RECT  29.173 2.304 29.261 2.328 ;
     RECT  29.365 2.832 29.401 2.856 ;
     RECT  29.401 2.832 29.513 3.528 ;
     RECT  29.513 2.88 29.603 3.528 ;
     RECT  28.541 6.048 29.605 6.072 ;
     RECT  28.685 0.576 29.653 0.6 ;
     RECT  29.653 0.576 29.749 1.128 ;
     RECT  29.749 0.192 29.833 1.128 ;
     RECT  29.833 0.192 29.873 1.656 ;
     RECT  29.041 8.4 29.941 8.424 ;
     RECT  29.941 7.344 30.017 7.368 ;
     RECT  29.797 4.272 30.133 4.296 ;
     RECT  29.605 5.424 30.133 6.072 ;
     RECT  29.873 0.576 30.179 1.656 ;
     RECT  29.941 8.4 30.197 9.144 ;
     RECT  30.133 4.272 30.413 6.072 ;
     RECT  29.081 10.176 30.517 11.4 ;
     RECT  30.517 10.176 30.553 11.688 ;
     RECT  29.603 2.88 30.565 2.904 ;
     RECT  30.553 10.176 30.611 11.784 ;
     RECT  30.197 8.4 30.755 9.048 ;
     RECT  30.179 1.632 30.757 1.656 ;
     RECT  30.413 4.272 30.851 4.536 ;
     RECT  30.757 1.632 30.913 1.704 ;
     RECT  30.565 2.88 30.913 2.952 ;
     RECT  30.413 5.664 30.913 6.072 ;
     RECT  30.913 1.632 30.953 2.952 ;
     RECT  30.851 4.272 30.953 4.296 ;
     RECT  30.611 10.176 31.061 11.352 ;
     RECT  30.913 5.664 31.093 6.264 ;
     RECT  30.953 1.68 31.139 2.952 ;
     RECT  31.093 5.664 31.235 6.84 ;
     RECT  30.755 9.024 31.333 9.048 ;
     RECT  31.061 10.176 31.333 10.344 ;
     RECT  31.139 1.68 31.457 2.856 ;
     RECT  30.179 0.576 31.477 0.6 ;
     RECT  31.561 4.128 31.619 4.152 ;
     RECT  31.333 9.024 32.101 10.344 ;
     RECT  32.101 8.544 32.173 10.344 ;
     RECT  31.061 11.328 32.173 11.352 ;
     RECT  32.281 4.608 32.341 4.632 ;
     RECT  31.235 5.664 32.341 6.261 ;
     RECT  32.173 8.544 32.437 11.352 ;
     RECT  32.341 4.608 32.461 6.261 ;
     RECT  31.669 7.344 32.461 7.368 ;
     RECT  31.457 1.68 32.497 1.704 ;
     RECT  31.457 2.832 32.497 2.856 ;
     RECT  32.437 8.544 32.497 11.448 ;
     RECT  31.477 0.192 32.648 0.6 ;
     RECT  32.497 1.68 32.648 2.856 ;
     RECT  32.461 4.608 32.648 7.368 ;
     RECT  32.497 8.544 32.648 11.496 ;
     RECT  32.648 0.192 32.944 11.496 ;
     RECT  32.944 4.56 33.059 6.36 ;
     RECT  32.944 8.544 33.059 9.144 ;
     RECT  32.944 0.192 33.155 3.384 ;
     RECT  33.059 4.56 33.329 6.261 ;
     RECT  32.944 10.368 33.541 11.496 ;
     RECT  33.541 10.368 33.617 11.784 ;
     RECT  33.617 10.368 33.635 11.688 ;
     RECT  33.329 4.848 33.653 6.261 ;
     RECT  33.059 8.544 34.153 8.568 ;
     RECT  33.155 2.64 34.189 3.384 ;
     RECT  34.153 8.544 34.211 9.144 ;
     RECT  34.189 2.256 34.259 3.384 ;
     RECT  33.653 5.664 34.261 6.261 ;
     RECT  34.211 8.544 34.369 8.568 ;
     RECT  34.369 8.448 34.409 8.568 ;
     RECT  34.259 2.928 34.453 3.384 ;
     RECT  33.635 10.368 34.625 11.352 ;
     RECT  34.453 2.928 34.645 3.528 ;
     RECT  34.261 5.664 34.645 6.408 ;
     RECT  34.645 5.664 34.693 6.84 ;
     RECT  34.645 2.928 34.765 4.296 ;
     RECT  34.693 5.616 34.787 6.84 ;
     RECT  33.155 0.192 34.789 1.176 ;
     RECT  34.765 2.928 34.835 4.344 ;
     RECT  34.789 0.192 34.877 1.752 ;
     RECT  34.835 2.928 34.913 4.296 ;
     RECT  34.625 10.368 34.933 10.92 ;
     RECT  34.933 10.224 35.125 10.92 ;
     RECT  34.913 2.928 35.413 3.768 ;
     RECT  35.413 2.832 35.459 3.768 ;
     RECT  34.787 6.048 35.701 6.84 ;
     RECT  34.409 8.448 35.701 8.472 ;
     RECT  35.125 9.648 35.701 10.92 ;
     RECT  35.701 8.448 35.737 10.92 ;
     RECT  35.701 6.048 35.747 6.888 ;
     RECT  35.737 8.448 35.921 11.352 ;
     RECT  35.921 9.744 36.035 11.352 ;
     RECT  35.747 6.048 36.085 6.792 ;
     RECT  36.085 5.76 36.173 6.792 ;
     RECT  35.459 2.832 36.421 2.952 ;
     RECT  36.421 2.832 36.461 3.24 ;
     RECT  36.461 3.216 36.497 3.24 ;
     RECT  36.173 6.048 36.641 6.792 ;
     RECT  34.877 0.192 36.785 1.176 ;
     RECT  36.757 3.312 36.821 3.336 ;
     RECT  36.641 6.048 37.237 6.261 ;
     RECT  36.785 0.576 37.813 1.176 ;
     RECT  37.357 4.272 37.813 4.296 ;
     RECT  37.237 5.376 37.813 6.261 ;
     RECT  37.609 2.736 37.909 2.76 ;
     RECT  37.813 4.272 37.909 6.261 ;
     RECT  36.035 10.176 37.909 11.352 ;
     RECT  37.813 0.192 38.048 1.176 ;
     RECT  37.909 2.736 38.048 6.261 ;
     RECT  35.921 8.448 38.048 8.472 ;
     RECT  37.909 10.176 38.048 11.496 ;
     RECT  38.048 0.192 38.344 11.496 ;
     RECT  38.344 7.92 38.389 11.496 ;
     RECT  38.344 5.664 38.441 6.264 ;
     RECT  38.344 0.192 38.531 1.8 ;
     RECT  38.389 7.92 38.531 11.592 ;
     RECT  38.531 10.32 38.579 11.064 ;
     RECT  38.531 7.92 38.765 9.144 ;
     RECT  38.531 0.576 38.771 1.8 ;
     RECT  38.344 4.32 38.819 4.344 ;
     RECT  38.579 10.848 38.819 11.064 ;
     RECT  38.765 7.92 39.125 8.568 ;
     RECT  38.771 0.576 39.305 1.176 ;
     RECT  38.441 5.664 39.485 6.261 ;
     RECT  39.305 0.576 39.541 0.6 ;
     RECT  39.541 9.648 39.733 9.672 ;
     RECT  38.819 10.848 39.733 10.872 ;
     RECT  39.733 9.648 39.809 10.872 ;
     RECT  39.809 10.176 39.877 10.872 ;
     RECT  39.485 5.76 40.259 6.261 ;
     RECT  39.541 0.192 40.309 0.6 ;
     RECT  40.309 0.192 40.355 1.176 ;
     RECT  39.733 2.304 40.385 2.328 ;
     RECT  40.355 0.192 40.547 0.648 ;
     RECT  39.877 10.176 40.745 11.352 ;
     RECT  41.209 3.504 41.269 3.96 ;
     RECT  41.269 3.504 41.315 4.104 ;
     RECT  41.269 1.68 41.413 1.704 ;
     RECT  40.745 10.176 41.461 10.872 ;
     RECT  41.413 1.68 41.465 2.328 ;
     RECT  41.315 3.744 41.497 4.104 ;
     RECT  41.461 9.648 41.573 10.872 ;
     RECT  41.497 3.744 41.603 4.968 ;
     RECT  41.603 3.744 41.717 4.104 ;
     RECT  40.547 0.576 41.821 0.648 ;
     RECT  41.573 9.696 41.891 10.872 ;
     RECT  40.259 6.048 42.073 6.261 ;
     RECT  41.891 9.744 42.083 10.872 ;
     RECT  42.083 10.176 42.185 10.872 ;
     RECT  42.185 10.224 42.397 10.872 ;
     RECT  41.821 0.576 42.437 1.416 ;
     RECT  41.717 4.08 42.709 4.104 ;
     RECT  42.709 3.792 42.757 4.104 ;
     RECT  42.073 5.616 42.757 6.261 ;
     RECT  42.437 0.576 42.997 1.176 ;
     RECT  39.125 7.92 43.045 7.944 ;
     RECT  42.973 9.12 43.045 9.144 ;
     RECT  42.757 3.792 43.333 6.261 ;
     RECT  42.397 10.224 43.381 11.064 ;
     RECT  42.997 0.192 43.448 1.176 ;
     RECT  43.333 3.792 43.448 6.84 ;
     RECT  43.045 7.92 43.448 9.144 ;
     RECT  43.381 10.224 43.448 11.496 ;
     RECT  43.448 0.192 43.744 11.496 ;
     RECT  43.744 9.12 43.765 11.496 ;
     RECT  43.744 7.92 43.841 8.088 ;
     RECT  43.744 0.192 43.907 1.176 ;
     RECT  43.765 9.12 43.907 11.544 ;
     RECT  43.907 9.12 44.237 11.352 ;
     RECT  43.744 6.048 44.387 6.792 ;
     RECT  43.744 2.304 44.435 2.76 ;
     RECT  43.744 4.56 44.435 4.968 ;
     RECT  44.237 9.12 44.453 9.24 ;
     RECT  44.435 2.304 44.771 2.328 ;
     RECT  44.737 5.04 45.011 5.064 ;
     RECT  43.841 7.968 45.029 8.088 ;
     RECT  45.029 7.968 45.065 7.992 ;
     RECT  44.387 6.048 45.109 6.261 ;
     RECT  43.907 0.576 45.169 1.176 ;
     RECT  45.109 3.504 45.173 3.528 ;
     RECT  44.237 10.464 45.301 11.352 ;
     RECT  45.109 5.616 45.493 6.261 ;
     RECT  45.301 9.648 45.731 11.352 ;
     RECT  45.731 9.648 46.021 10.536 ;
     RECT  46.021 9.36 46.115 10.536 ;
     RECT  45.169 0.576 46.181 1.944 ;
     RECT  46.117 3.12 46.181 3.144 ;
     RECT  46.181 0.576 46.261 1.176 ;
     RECT  45.493 5.616 46.309 6.888 ;
     RECT  46.261 0.192 46.325 1.176 ;
     RECT  46.309 4.512 46.397 6.888 ;
     RECT  46.115 10.224 46.649 10.536 ;
     RECT  46.397 4.56 46.739 6.888 ;
     RECT  46.453 3.36 46.829 3.432 ;
     RECT  46.829 3.408 47.261 3.432 ;
     RECT  46.645 9.12 47.297 9.144 ;
     RECT  46.739 5.04 47.411 6.888 ;
     RECT  47.221 11.328 47.413 11.352 ;
     RECT  46.325 0.576 47.557 1.176 ;
     RECT  47.557 0.576 47.605 1.704 ;
     RECT  46.649 10.224 47.605 10.344 ;
     RECT  47.413 11.328 47.657 11.4 ;
     RECT  47.605 9.648 47.989 10.344 ;
     RECT  47.657 11.328 47.989 11.352 ;
     RECT  47.605 0.192 48.419 1.704 ;
     RECT  47.411 5.76 48.697 6.888 ;
     RECT  48.697 5.616 48.709 6.888 ;
     RECT  48.517 8.16 48.709 8.184 ;
     RECT  47.989 9.648 48.709 11.352 ;
     RECT  48.419 0.384 48.848 1.704 ;
     RECT  48.157 3.504 48.848 3.528 ;
     RECT  48.409 4.512 48.848 4.536 ;
     RECT  48.709 5.616 48.848 8.184 ;
     RECT  48.709 9.6 48.848 11.592 ;
     RECT  48.848 0.384 48.995 11.592 ;
     RECT  48.995 0.384 49.144 11.496 ;
     RECT  49.144 4.656 49.241 4.68 ;
     RECT  49.144 5.856 49.241 7.464 ;
     RECT  49.144 8.448 49.277 11.496 ;
     RECT  49.144 0.384 49.283 2.232 ;
     RECT  49.277 8.448 49.385 11.352 ;
     RECT  49.283 0.384 49.633 1.176 ;
     RECT  49.283 2.208 49.673 2.232 ;
     RECT  49.385 8.448 50.177 10.344 ;
     RECT  50.177 8.448 50.321 8.616 ;
     RECT  49.241 6.048 50.533 7.464 ;
     RECT  50.533 4.512 50.725 4.536 ;
     RECT  50.533 6.048 50.725 7.56 ;
     RECT  50.725 4.512 50.789 7.56 ;
     RECT  49.633 0.192 50.825 1.176 ;
     RECT  50.177 10.272 51.253 10.344 ;
     RECT  49.385 11.328 51.253 11.352 ;
     RECT  50.789 5.712 51.299 7.56 ;
     RECT  50.321 8.544 51.299 8.616 ;
     RECT  51.299 6.048 51.361 7.56 ;
     RECT  51.217 2.352 51.445 2.376 ;
     RECT  50.789 4.512 51.445 4.536 ;
     RECT  51.445 2.208 51.509 2.376 ;
     RECT  51.445 3.84 51.509 4.536 ;
     RECT  51.253 10.272 51.509 11.352 ;
     RECT  51.361 6.048 51.539 8.04 ;
     RECT  51.613 2.736 51.685 2.76 ;
     RECT  51.509 10.848 51.781 11.352 ;
     RECT  51.781 10.848 51.833 11.784 ;
     RECT  51.833 10.848 51.875 11.688 ;
     RECT  51.685 2.736 51.905 3.432 ;
     RECT  51.539 6.048 51.923 7.368 ;
     RECT  50.825 0.576 51.925 1.176 ;
     RECT  51.925 0.576 51.977 1.32 ;
     RECT  51.905 2.736 52.049 2.952 ;
     RECT  52.049 2.832 52.193 2.952 ;
     RECT  52.193 2.928 52.265 2.952 ;
     RECT  51.875 10.848 52.373 11.4 ;
     RECT  51.977 0.576 52.405 1.176 ;
     RECT  51.509 4.512 52.405 4.536 ;
     RECT  51.923 6.048 52.405 6.264 ;
     RECT  52.373 11.376 52.481 11.4 ;
     RECT  52.405 4.512 52.589 6.264 ;
     RECT  52.597 10.224 52.697 10.248 ;
     RECT  52.589 6.096 52.805 6.264 ;
     RECT  52.789 9.12 52.945 9.144 ;
     RECT  52.945 9.12 53.027 9.24 ;
     RECT  53.365 11.328 53.449 11.352 ;
     RECT  51.923 7.344 53.509 7.368 ;
     RECT  52.805 6.099 53.701 6.264 ;
     RECT  53.509 7.344 53.701 7.464 ;
     RECT  53.017 3.408 53.941 3.432 ;
     RECT  52.589 4.512 53.941 4.536 ;
     RECT  53.449 10.608 53.941 11.352 ;
     RECT  52.405 0.192 54.248 1.176 ;
     RECT  53.941 3.408 54.248 4.536 ;
     RECT  53.701 6.099 54.248 7.464 ;
     RECT  53.027 9.12 54.248 9.144 ;
     RECT  53.941 10.608 54.248 11.448 ;
     RECT  54.248 0.192 54.325 11.448 ;
     RECT  54.325 0.192 54.517 11.496 ;
     RECT  54.517 0.192 54.544 11.592 ;
     RECT  54.544 0.192 54.659 1.176 ;
     RECT  54.544 9.072 54.659 11.592 ;
     RECT  54.659 9.648 54.707 11.592 ;
     RECT  54.544 5.616 54.713 6.264 ;
     RECT  54.713 5.616 54.965 6.261 ;
     RECT  54.707 9.648 55.001 11.352 ;
     RECT  54.544 2.448 55.139 2.472 ;
     RECT  54.544 3.936 55.253 3.96 ;
     RECT  55.001 9.648 55.669 10.776 ;
     RECT  54.659 0.576 55.861 1.176 ;
     RECT  55.861 0.192 55.907 1.176 ;
     RECT  55.669 9.6 56.053 10.776 ;
     RECT  56.053 9.6 56.099 10.824 ;
     RECT  54.544 7.344 56.117 7.368 ;
     RECT  56.099 10.608 56.245 10.824 ;
     RECT  56.149 4.512 56.401 4.536 ;
     RECT  54.965 6.243 56.905 6.261 ;
     RECT  55.907 0.576 57.013 1.176 ;
     RECT  57.013 0.576 57.059 1.992 ;
     RECT  56.389 9.024 57.205 9.048 ;
     RECT  56.245 10.608 57.205 11.352 ;
     RECT  56.401 4.512 57.397 5.208 ;
     RECT  56.905 6.243 57.397 6.36 ;
     RECT  57.481 3.504 57.539 3.528 ;
     RECT  57.205 9.024 57.593 11.352 ;
     RECT  57.397 4.512 57.637 6.36 ;
     RECT  57.637 3.744 57.701 6.36 ;
     RECT  57.059 0.576 58.061 1.176 ;
     RECT  57.593 9.12 58.133 11.352 ;
     RECT  57.701 4.656 58.163 6.36 ;
     RECT  58.061 0.576 58.273 0.6 ;
     RECT  58.273 0.192 58.403 0.6 ;
     RECT  58.163 5.184 58.417 6.36 ;
     RECT  58.133 9.408 58.421 11.352 ;
     RECT  58.645 1.68 58.741 1.704 ;
     RECT  58.741 1.68 58.933 2.28 ;
     RECT  58.417 5.184 59.269 6.408 ;
     RECT  58.421 10.608 59.317 11.352 ;
     RECT  59.101 3.408 59.425 3.432 ;
     RECT  59.317 10.608 59.425 11.448 ;
     RECT  58.403 0.576 59.461 0.6 ;
     RECT  58.933 1.68 59.461 2.376 ;
     RECT  59.461 0.576 59.648 2.376 ;
     RECT  59.425 3.408 59.648 4.104 ;
     RECT  59.269 5.136 59.648 6.408 ;
     RECT  58.421 9.408 59.648 9.528 ;
     RECT  59.425 10.608 59.648 11.496 ;
     RECT  59.648 0.528 59.701 11.496 ;
     RECT  59.701 0.384 59.893 11.496 ;
     RECT  59.893 0.288 59.944 11.496 ;
     RECT  59.944 0.288 60.083 1.176 ;
     RECT  59.944 10.224 60.083 11.496 ;
     RECT  59.944 2.688 60.227 4.104 ;
     RECT  60.227 2.688 60.473 3.432 ;
     RECT  60.083 10.224 60.473 11.352 ;
     RECT  60.473 3.408 60.545 3.432 ;
     RECT  59.944 5.136 60.803 6.408 ;
     RECT  60.083 0.576 60.899 1.176 ;
     RECT  61.045 7.968 61.091 7.992 ;
     RECT  60.973 1.968 61.193 1.992 ;
     RECT  60.473 10.224 61.229 10.872 ;
     RECT  60.803 5.184 61.261 6.408 ;
     RECT  60.899 0.576 61.429 0.6 ;
     RECT  61.229 10.272 61.805 10.872 ;
     RECT  61.261 5.184 61.909 6.552 ;
     RECT  61.429 0.192 62.057 0.6 ;
     RECT  61.805 10.608 62.197 10.872 ;
     RECT  61.585 2.208 62.341 2.376 ;
     RECT  62.057 0.576 62.389 0.6 ;
     RECT  61.909 4.512 62.557 6.552 ;
     RECT  62.557 4.512 62.627 6.888 ;
     RECT  62.627 4.512 62.629 6.552 ;
     RECT  62.629 4.08 62.705 6.552 ;
     RECT  62.389 0.576 62.819 1.176 ;
     RECT  62.341 2.208 62.869 2.52 ;
     RECT  62.705 4.56 62.885 6.552 ;
     RECT  62.581 9.12 62.953 9.144 ;
     RECT  62.869 2.208 62.965 2.856 ;
     RECT  62.197 10.608 63.025 11.352 ;
     RECT  62.965 2.208 63.097 2.952 ;
     RECT  63.097 1.536 63.109 2.952 ;
     RECT  63.109 1.536 63.155 3.432 ;
     RECT  62.953 8.928 63.157 9.144 ;
     RECT  63.025 10.368 63.157 11.352 ;
     RECT  63.155 1.632 63.173 3.432 ;
     RECT  63.173 1.632 63.203 2.856 ;
     RECT  63.203 2.304 63.317 2.856 ;
     RECT  63.253 7.92 63.353 7.944 ;
     RECT  63.349 0.192 63.461 0.216 ;
     RECT  63.157 8.928 63.781 11.352 ;
     RECT  63.781 8.448 63.857 11.352 ;
     RECT  63.857 8.928 63.971 11.352 ;
     RECT  62.885 4.56 64.069 6.264 ;
     RECT  63.925 0.576 64.117 0.6 ;
     RECT  63.317 2.304 64.309 2.472 ;
     RECT  64.309 2.208 64.681 2.472 ;
     RECT  63.971 8.928 64.969 11.064 ;
     RECT  64.117 0.576 65.005 1.176 ;
     RECT  64.681 2.208 65.041 2.76 ;
     RECT  64.069 4.08 65.041 6.264 ;
     RECT  65.005 0.384 65.048 1.176 ;
     RECT  65.041 2.208 65.048 6.264 ;
     RECT  64.969 8.448 65.048 11.064 ;
     RECT  65.048 0.384 65.077 11.352 ;
     RECT  65.077 0.384 65.269 11.496 ;
     RECT  65.269 0.384 65.344 11.544 ;
     RECT  65.344 9.456 65.441 11.544 ;
     RECT  65.344 3.6 65.459 3.624 ;
     RECT  65.344 8.448 65.459 8.472 ;
     RECT  65.441 9.456 65.459 11.496 ;
     RECT  65.344 0.384 65.461 1.176 ;
     RECT  65.461 0.192 65.891 1.176 ;
     RECT  65.459 9.456 65.987 11.16 ;
     RECT  66.325 8.016 66.377 8.04 ;
     RECT  66.421 4.368 66.563 4.392 ;
     RECT  65.987 9.456 66.589 9.72 ;
     RECT  66.589 9.12 66.665 9.72 ;
     RECT  65.891 0.576 66.709 1.176 ;
     RECT  65.344 2.256 66.709 2.28 ;
     RECT  65.344 5.472 66.805 6.84 ;
     RECT  66.709 0.576 66.809 2.28 ;
     RECT  66.665 9.12 66.985 9.672 ;
     RECT  66.985 8.784 67.043 9.672 ;
     RECT  66.805 5.472 67.235 6.888 ;
     RECT  67.043 9.648 67.241 9.672 ;
     RECT  67.235 5.472 67.333 6.264 ;
     RECT  67.309 7.44 67.379 7.464 ;
     RECT  65.987 11.04 67.381 11.16 ;
     RECT  66.809 0.576 67.427 1.176 ;
     RECT  66.809 2.208 67.453 2.28 ;
     RECT  67.381 10.848 67.573 11.16 ;
     RECT  67.453 2.208 67.673 2.856 ;
     RECT  67.427 0.576 67.765 0.6 ;
     RECT  67.333 5.088 67.813 6.264 ;
     RECT  67.813 4.272 67.889 6.264 ;
     RECT  67.573 10.848 68.149 11.352 ;
     RECT  68.209 8.496 68.291 8.52 ;
     RECT  68.149 10.8 68.321 11.352 ;
     RECT  67.889 4.704 68.497 6.264 ;
     RECT  68.497 4.704 68.537 6.312 ;
     RECT  68.321 10.848 68.753 11.352 ;
     RECT  68.389 2.928 68.773 2.952 ;
     RECT  68.773 2.784 69.289 2.952 ;
     RECT  69.289 2.352 69.301 2.952 ;
     RECT  69.253 3.936 69.301 3.96 ;
     RECT  69.301 2.352 69.329 3.96 ;
     RECT  69.329 2.352 69.395 3.24 ;
     RECT  69.361 8.784 69.443 8.808 ;
     RECT  67.765 0.192 69.541 0.6 ;
     RECT  69.541 0.192 69.545 1.08 ;
     RECT  68.537 5.472 69.637 6.312 ;
     RECT  68.753 10.848 69.685 11.16 ;
     RECT  69.545 0.288 69.829 1.08 ;
     RECT  69.685 10.8 70.213 11.16 ;
     RECT  69.493 9.12 70.309 9.672 ;
     RECT  70.213 10.8 70.309 11.544 ;
     RECT  69.829 0.288 70.448 1.176 ;
     RECT  69.395 2.928 70.448 3.24 ;
     RECT  69.637 4.512 70.448 6.312 ;
     RECT  70.309 9.12 70.448 11.544 ;
     RECT  70.448 0.288 70.691 11.544 ;
     RECT  70.691 0.288 70.744 11.352 ;
     RECT  70.744 4.128 70.805 6.84 ;
     RECT  70.805 4.128 70.883 4.152 ;
     RECT  70.744 10.224 70.949 10.248 ;
     RECT  70.744 8.496 71.129 8.52 ;
     RECT  70.744 0.288 71.221 1.656 ;
     RECT  70.744 2.688 71.237 2.712 ;
     RECT  71.221 0.192 71.345 1.656 ;
     RECT  71.345 0.576 71.417 1.656 ;
     RECT  70.744 11.328 71.737 11.352 ;
     RECT  71.417 0.576 72.035 1.176 ;
     RECT  71.989 8.544 72.085 8.568 ;
     RECT  72.085 8.544 72.173 8.76 ;
     RECT  71.737 10.368 72.227 11.352 ;
     RECT  72.035 0.576 72.373 0.6 ;
     RECT  71.797 2.784 72.529 2.808 ;
     RECT  72.529 1.728 72.611 2.808 ;
     RECT  72.611 2.208 72.745 2.808 ;
     RECT  72.745 2.208 72.853 2.952 ;
     RECT  72.493 4.56 72.853 4.584 ;
     RECT  70.805 5.712 72.899 6.84 ;
     RECT  72.373 0.192 73.073 0.6 ;
     RECT  72.853 2.208 73.141 4.584 ;
     RECT  72.899 5.712 73.141 6.117 ;
     RECT  73.141 2.208 73.475 6.117 ;
     RECT  72.757 9.12 73.525 9.144 ;
     RECT  73.475 2.208 73.613 4.968 ;
     RECT  73.525 9.072 73.813 9.144 ;
     RECT  73.813 8.736 73.865 9.144 ;
     RECT  73.475 6 73.897 6.117 ;
     RECT  73.865 9.072 73.937 9.144 ;
     RECT  73.073 0.576 74.041 0.6 ;
     RECT  74.041 0.576 74.053 0.648 ;
     RECT  73.897 6 74.149 6.12 ;
     RECT  74.149 6 74.333 6.792 ;
     RECT  72.227 10.368 74.485 10.872 ;
     RECT  73.613 2.208 74.617 3.336 ;
     RECT  74.053 0.576 74.621 1.08 ;
     RECT  74.333 6 74.657 6.264 ;
     RECT  73.937 9.12 74.657 9.144 ;
     RECT  74.485 10.368 74.677 11.352 ;
     RECT  74.657 6.144 74.723 6.264 ;
     RECT  73.613 4.416 74.765 4.968 ;
     RECT  74.677 10.272 74.765 11.352 ;
     RECT  74.677 1.152 74.797 1.176 ;
     RECT  74.617 2.208 75.109 3.432 ;
     RECT  74.797 1.152 75.637 1.224 ;
     RECT  74.723 6.144 75.769 6.168 ;
     RECT  75.109 2.208 75.805 3.768 ;
     RECT  74.765 4.944 75.805 4.968 ;
     RECT  74.765 10.368 75.829 11.352 ;
     RECT  75.637 0.192 75.848 1.224 ;
     RECT  75.805 2.208 75.848 4.968 ;
     RECT  75.769 6.048 75.848 6.168 ;
     RECT  75.829 10.368 75.848 11.496 ;
     RECT  75.848 0.192 76.021 11.496 ;
     RECT  76.021 0.192 76.144 11.592 ;
     RECT  76.144 10.272 76.213 11.592 ;
     RECT  76.144 2.256 76.259 3.048 ;
     RECT  76.213 10.272 76.355 11.688 ;
     RECT  76.144 4.704 76.709 7.752 ;
     RECT  76.259 2.256 76.745 2.952 ;
     RECT  76.709 6.24 76.889 7.752 ;
     RECT  76.745 2.256 76.997 2.472 ;
     RECT  76.144 9.12 77.173 9.288 ;
     RECT  76.355 10.272 77.173 10.872 ;
     RECT  76.889 7.728 77.209 7.752 ;
     RECT  76.889 6.24 77.249 6.552 ;
     RECT  77.209 7.728 77.249 7.992 ;
     RECT  77.173 9.12 77.501 10.872 ;
     RECT  77.501 9.12 77.537 9.24 ;
     RECT  77.501 10.272 77.557 10.872 ;
     RECT  76.144 0.192 77.609 1.176 ;
     RECT  77.557 10.272 77.749 11.352 ;
     RECT  77.249 7.968 77.785 7.992 ;
     RECT  77.537 9.12 77.785 9.144 ;
     RECT  77.609 0.576 77.825 1.176 ;
     RECT  77.785 7.968 77.843 9.144 ;
     RECT  77.749 10.272 77.987 11.4 ;
     RECT  76.997 2.304 78.037 2.472 ;
     RECT  77.843 9.12 78.077 9.144 ;
     RECT  78.037 1.776 78.083 2.472 ;
     RECT  78.083 2.208 78.217 2.472 ;
     RECT  78.217 2.208 78.277 2.952 ;
     RECT  78.277 2.208 78.329 3.528 ;
     RECT  77.987 10.272 78.517 11.352 ;
     RECT  76.709 4.704 78.541 4.728 ;
     RECT  78.541 4.56 78.611 4.728 ;
     RECT  78.517 10.224 78.613 11.352 ;
     RECT  78.613 9.168 78.659 11.352 ;
     RECT  77.825 0.576 79.093 0.792 ;
     RECT  78.611 4.704 79.141 4.728 ;
     RECT  78.329 2.208 79.235 3.336 ;
     RECT  77.249 6.528 79.297 6.552 ;
     RECT  79.285 7.872 79.373 7.896 ;
     RECT  79.297 6.528 79.379 6.6 ;
     RECT  78.659 10.224 79.445 11.352 ;
     RECT  79.093 0.576 79.669 1.176 ;
     RECT  79.141 4.704 79.669 5.112 ;
     RECT  79.669 4.704 79.693 5.4 ;
     RECT  79.379 6.528 79.693 6.552 ;
     RECT  79.693 4.704 79.763 6.552 ;
     RECT  79.669 0.192 79.769 1.176 ;
     RECT  78.659 9.168 79.837 9.192 ;
     RECT  79.763 4.704 79.877 5.4 ;
     RECT  79.837 9.072 79.907 9.192 ;
     RECT  79.877 5.376 79.913 5.4 ;
     RECT  79.445 10.224 80.053 10.824 ;
     RECT  79.235 2.352 80.161 3.336 ;
     RECT  79.769 0.576 80.293 1.176 ;
     RECT  80.161 2.352 80.293 4.248 ;
     RECT  80.293 0.576 80.821 4.248 ;
     RECT  80.053 9.648 80.821 10.824 ;
     RECT  80.821 0.192 81.013 4.248 ;
     RECT  79.763 6.528 81.013 6.552 ;
     RECT  81.013 6.528 81.025 6.888 ;
     RECT  81.013 0.192 81.061 4.536 ;
     RECT  81.025 6 81.061 6.888 ;
     RECT  80.821 9.648 81.061 11.352 ;
     RECT  81.061 0.192 81.248 6.888 ;
     RECT  81.061 9.648 81.248 11.592 ;
     RECT  81.248 0.192 81.443 11.592 ;
     RECT  81.443 0.192 81.544 11.448 ;
     RECT  81.544 10.32 81.641 11.448 ;
     RECT  81.544 2.736 81.683 5.16 ;
     RECT  81.683 4.224 81.731 5.16 ;
     RECT  81.683 2.736 82.115 2.76 ;
     RECT  81.641 10.32 82.145 11.352 ;
     RECT  81.544 9.072 82.433 9.096 ;
     RECT  81.731 4.224 82.577 4.248 ;
     RECT  81.544 0.192 82.595 1.176 ;
     RECT  81.544 6.528 82.837 6.6 ;
     RECT  82.837 6.528 82.861 6.84 ;
     RECT  83.077 2.208 83.219 2.232 ;
     RECT  83.125 9.12 83.225 9.144 ;
     RECT  82.145 10.368 83.317 11.352 ;
     RECT  82.861 6.528 83.509 6.936 ;
     RECT  83.509 6.528 83.651 7.464 ;
     RECT  83.317 10.368 83.729 11.4 ;
     RECT  83.653 5.04 83.765 5.064 ;
     RECT  83.725 3.504 83.795 3.528 ;
     RECT  84.085 4.08 84.131 4.104 ;
     RECT  83.977 8.016 84.157 8.04 ;
     RECT  84.157 8.016 84.227 8.568 ;
     RECT  83.651 6.528 84.229 6.648 ;
     RECT  84.085 2.304 84.233 2.328 ;
     RECT  83.729 10.368 84.269 11.352 ;
     RECT  84.227 8.544 84.277 8.568 ;
     RECT  84.373 2.352 84.449 2.856 ;
     RECT  84.229 6.24 84.469 6.648 ;
     RECT  82.595 0.576 84.515 1.176 ;
     RECT  84.469 5.856 84.521 6.648 ;
     RECT  84.277 8.544 84.661 9.192 ;
     RECT  84.269 10.368 84.661 11.064 ;
     RECT  84.521 6.192 84.665 6.648 ;
     RECT  84.449 2.352 84.899 2.376 ;
     RECT  84.665 6.624 84.913 6.648 ;
     RECT  84.661 8.544 84.917 11.064 ;
     RECT  84.515 0.576 85.237 0.6 ;
     RECT  85.429 2.928 85.493 2.952 ;
     RECT  84.917 8.544 85.493 9.048 ;
     RECT  85.237 0.192 85.573 0.6 ;
     RECT  85.573 0.192 85.705 0.792 ;
     RECT  85.705 0.192 85.709 1.176 ;
     RECT  84.913 6.624 85.717 6.84 ;
     RECT  85.717 5.04 85.777 5.064 ;
     RECT  85.777 4.56 85.813 5.064 ;
     RECT  85.493 9.024 86.005 9.048 ;
     RECT  84.917 10.368 86.005 11.064 ;
     RECT  85.813 4.56 86.485 5.112 ;
     RECT  86.485 4.272 86.533 5.112 ;
     RECT  86.005 9.024 86.533 11.064 ;
     RECT  85.709 0.288 86.648 1.176 ;
     RECT  86.533 2.832 86.648 2.856 ;
     RECT  86.533 4.272 86.648 5.592 ;
     RECT  85.717 6.624 86.648 7.56 ;
     RECT  86.533 9.024 86.648 11.496 ;
     RECT  86.648 0.288 86.944 11.496 ;
     RECT  86.944 0.288 86.965 1.8 ;
     RECT  86.944 8.304 86.965 11.496 ;
     RECT  86.965 8.304 87.077 11.592 ;
     RECT  87.077 10.368 87.155 11.592 ;
     RECT  86.944 5.568 87.257 7.224 ;
     RECT  87.077 8.304 87.347 9.048 ;
     RECT  86.965 0.192 87.875 1.8 ;
     RECT  87.925 4.272 87.977 4.296 ;
     RECT  87.257 6.528 88.225 7.224 ;
     RECT  87.347 9.024 88.297 9.048 ;
     RECT  88.225 5.712 88.309 7.224 ;
     RECT  88.261 2.928 88.355 2.952 ;
     RECT  88.309 4.896 88.355 7.224 ;
     RECT  88.355 4.896 88.481 4.92 ;
     RECT  87.155 10.368 88.481 11.4 ;
     RECT  88.355 6.528 88.657 7.224 ;
     RECT  88.297 9.024 88.733 9.144 ;
     RECT  88.657 6.528 88.739 7.608 ;
     RECT  88.733 9.12 88.877 9.144 ;
     RECT  88.481 10.368 88.909 11.352 ;
     RECT  87.875 0.192 88.931 1.176 ;
     RECT  89.017 2.352 89.507 2.52 ;
     RECT  88.909 9.504 89.561 11.352 ;
     RECT  88.739 6.528 89.699 6.792 ;
     RECT  89.797 2.928 89.849 2.952 ;
     RECT  88.931 0.192 90.085 0.6 ;
     RECT  89.737 1.68 90.085 1.704 ;
     RECT  90.085 4.512 90.137 4.536 ;
     RECT  90.349 4.08 90.563 4.104 ;
     RECT  90.085 0.192 90.565 1.704 ;
     RECT  90.565 0.192 90.641 2.136 ;
     RECT  89.699 6.528 90.677 6.648 ;
     RECT  90.709 5.088 90.755 5.112 ;
     RECT  89.561 9.504 90.805 10.968 ;
     RECT  90.805 9.072 91.073 10.968 ;
     RECT  90.205 7.92 91.381 7.944 ;
     RECT  91.073 9.072 91.381 9.192 ;
     RECT  91.073 10.368 91.381 10.968 ;
     RECT  90.641 0.192 91.433 1.176 ;
     RECT  91.381 10.368 91.573 11.352 ;
     RECT  90.677 6.624 91.765 6.648 ;
     RECT  91.433 0.384 91.909 1.176 ;
     RECT  91.813 2.928 91.909 2.952 ;
     RECT  91.825 3.936 91.909 3.96 ;
     RECT  91.573 10.368 91.933 11.448 ;
     RECT  91.909 0.384 92.009 1.704 ;
     RECT  92.009 0.528 92.048 1.704 ;
     RECT  91.909 2.928 92.048 3.96 ;
     RECT  91.765 6.432 92.048 6.648 ;
     RECT  91.381 7.92 92.048 9.192 ;
     RECT  91.933 10.368 92.048 11.544 ;
     RECT  92.048 0.528 92.152 11.544 ;
     RECT  92.152 0.576 92.344 11.544 ;
     RECT  92.344 10.272 92.405 11.544 ;
     RECT  92.344 3.936 92.483 6.648 ;
     RECT  92.483 4.512 92.627 6.648 ;
     RECT  92.344 2.304 92.771 2.856 ;
     RECT  92.627 4.512 92.771 5.688 ;
     RECT  92.771 2.304 92.981 2.712 ;
     RECT  92.771 4.512 93.053 4.536 ;
     RECT  92.405 10.272 93.125 11.352 ;
     RECT  93.125 10.368 93.521 11.352 ;
     RECT  92.981 2.688 93.539 2.712 ;
     RECT  92.344 8.016 93.589 8.472 ;
     RECT  93.589 8.016 93.635 9.192 ;
     RECT  92.771 5.664 93.737 5.688 ;
     RECT  92.344 0.576 94.069 1.176 ;
     RECT  94.069 0.192 94.133 1.176 ;
     RECT  93.521 10.8 94.133 11.352 ;
     RECT  94.069 6.192 94.205 6.216 ;
     RECT  94.525 6.576 94.595 6.6 ;
     RECT  94.261 9.408 94.597 9.432 ;
     RECT  94.597 9.408 94.637 9.816 ;
     RECT  94.237 2.304 94.705 2.328 ;
     RECT  94.645 3.504 94.705 3.528 ;
     RECT  94.705 2.304 94.709 3.528 ;
     RECT  94.133 0.576 94.741 1.176 ;
     RECT  94.709 2.304 94.741 3.432 ;
     RECT  94.637 9.6 94.745 9.816 ;
     RECT  94.741 0.576 95.075 3.432 ;
     RECT  94.745 9.648 95.105 9.816 ;
     RECT  93.635 8.016 95.141 8.328 ;
     RECT  95.075 1.68 95.171 3.432 ;
     RECT  95.105 9.792 95.221 9.816 ;
     RECT  94.133 10.848 95.221 11.352 ;
     RECT  95.221 9.792 95.573 11.352 ;
     RECT  95.171 1.68 95.843 1.704 ;
     RECT  96.085 6.144 96.109 6.168 ;
     RECT  96.109 6.144 96.149 6.264 ;
     RECT  96.149 6.24 96.179 6.264 ;
     RECT  95.075 0.576 96.181 0.6 ;
     RECT  95.573 9.792 96.181 9.816 ;
     RECT  95.171 3.12 96.275 3.144 ;
     RECT  96.181 9.648 96.293 9.816 ;
     RECT  96.181 0.192 96.373 0.6 ;
     RECT  95.141 8.304 96.401 8.328 ;
     RECT  96.373 0.192 96.437 1.08 ;
     RECT  95.573 10.848 96.565 11.352 ;
     RECT  96.757 2.736 96.901 2.76 ;
     RECT  96.793 8.496 96.949 8.52 ;
     RECT  96.293 9.792 97.141 9.816 ;
     RECT  96.565 10.848 97.141 11.4 ;
     RECT  96.437 0.192 97.448 0.6 ;
     RECT  96.901 2.304 97.448 2.76 ;
     RECT  96.949 8.496 97.448 8.568 ;
     RECT  97.141 9.792 97.448 11.4 ;
     RECT  97.448 0.192 97.525 11.4 ;
     RECT  97.525 0.192 97.717 11.496 ;
     RECT  97.717 0.192 97.744 11.544 ;
     RECT  97.744 9.792 97.769 11.544 ;
     RECT  97.769 9.792 97.841 11.496 ;
     RECT  97.744 2.256 97.859 3.768 ;
     RECT  97.744 7.968 97.913 8.52 ;
     RECT  97.841 9.792 98.021 11.352 ;
     RECT  97.744 6 98.051 6.024 ;
     RECT  97.913 7.968 98.129 8.424 ;
     RECT  98.021 9.792 98.453 10.872 ;
     RECT  98.129 8.4 99.029 8.424 ;
     RECT  98.453 10.848 99.061 10.872 ;
     RECT  99.061 10.848 99.253 10.92 ;
     RECT  97.859 2.832 99.301 3.768 ;
     RECT  99.157 6 99.317 6.024 ;
     RECT  99.301 2.832 99.385 4.104 ;
     RECT  99.253 10.848 99.425 11.352 ;
     RECT  97.744 0.192 99.529 1.176 ;
     RECT  98.453 9.792 99.565 9.816 ;
     RECT  99.425 10.848 99.565 11.016 ;
     RECT  99.529 0.192 99.587 1.56 ;
     RECT  99.385 5.136 99.587 5.16 ;
     RECT  99.385 2.736 99.589 4.104 ;
     RECT  99.565 9.792 99.605 11.016 ;
     RECT  99.587 0.192 99.683 1.128 ;
     RECT  99.589 2.688 99.733 4.104 ;
     RECT  99.733 2.688 99.749 4.536 ;
     RECT  99.749 2.688 99.925 2.76 ;
     RECT  99.877 6.864 99.929 6.888 ;
     RECT  99.749 3.744 100.217 4.536 ;
     RECT  99.605 10.224 100.405 11.016 ;
     RECT  100.405 10.224 100.469 11.064 ;
     RECT  99.925 2.304 100.573 2.76 ;
     RECT  99.683 0.576 100.597 1.128 ;
     RECT  100.573 2.256 100.613 2.76 ;
     RECT  100.597 0.576 100.649 1.176 ;
     RECT  100.217 4.512 100.937 4.536 ;
     RECT  100.649 0.576 100.981 0.6 ;
     RECT  100.613 2.256 101.261 2.328 ;
     RECT  100.789 9.072 101.365 9.096 ;
     RECT  100.469 10.224 101.365 10.92 ;
     RECT  101.365 9.072 101.477 10.92 ;
     RECT  101.477 10.224 101.549 10.92 ;
     RECT  101.549 10.848 101.557 10.92 ;
     RECT  100.981 0.192 101.701 0.6 ;
     RECT  101.689 3.504 101.747 3.528 ;
     RECT  101.557 10.848 101.749 11.352 ;
     RECT  101.749 6.816 101.801 6.84 ;
     RECT  101.701 0.192 101.987 1.08 ;
     RECT  101.617 8.64 102.037 8.664 ;
     RECT  101.987 0.384 102.325 1.08 ;
     RECT  102.037 8.448 102.517 8.664 ;
     RECT  102.517 8.448 102.661 9.144 ;
     RECT  101.749 10.848 102.661 11.4 ;
     RECT  102.661 8.448 102.697 9.384 ;
     RECT  102.661 10.848 102.697 11.544 ;
     RECT  101.401 5.136 102.709 5.16 ;
     RECT  102.325 0.384 102.848 1.176 ;
     RECT  101.261 2.256 102.848 2.28 ;
     RECT  102.613 3.408 102.848 3.432 ;
     RECT  102.709 4.416 102.848 5.256 ;
     RECT  102.697 8.448 102.848 11.544 ;
     RECT  102.848 0.384 103.093 11.544 ;
     RECT  103.093 0.192 103.139 11.544 ;
     RECT  103.139 0.576 103.144 11.496 ;
     RECT  103.144 8.448 103.169 11.496 ;
     RECT  103.169 9.744 103.205 11.496 ;
     RECT  103.144 4.272 103.385 5.256 ;
     RECT  103.205 9.744 103.421 11.352 ;
     RECT  103.169 8.448 103.601 8.472 ;
     RECT  103.421 9.744 103.667 9.768 ;
     RECT  103.144 2.256 103.997 2.28 ;
     RECT  103.144 0.576 104.291 1.176 ;
     RECT  104.245 7.872 104.321 7.896 ;
     RECT  103.385 4.272 104.465 4.296 ;
     RECT  103.421 10.8 104.537 11.352 ;
     RECT  104.537 10.8 104.681 10.872 ;
     RECT  104.681 10.848 104.753 10.872 ;
     RECT  104.291 0.576 104.825 0.6 ;
    LAYER M5 ;
     RECT  0.384 0.144 104.664 0.517 ;
     RECT  0.24 0.517 104.664 0.611 ;
     RECT  0.24 0.611 11.544 0.659 ;
     RECT  40.32 0.611 58.008 0.659 ;
     RECT  2.304 0.659 11.544 0.811 ;
     RECT  78.768 0.611 84.504 0.811 ;
     RECT  85.584 0.611 88.92 0.811 ;
     RECT  2.304 0.811 9.048 1.131 ;
     RECT  14.4 0.611 25.752 1.131 ;
     RECT  41.856 0.659 58.008 1.131 ;
     RECT  69.552 0.611 72.6 1.131 ;
     RECT  74.064 0.611 77.784 1.131 ;
     RECT  96.384 0.611 96.408 1.131 ;
     RECT  101.712 0.611 104.28 1.131 ;
     RECT  29.664 0.611 30.168 1.139 ;
     RECT  97.44 0.611 100.632 1.139 ;
     RECT  0.24 0.659 1.176 1.187 ;
     RECT  2.304 1.131 4.248 1.187 ;
     RECT  5.472 1.131 9.048 1.187 ;
     RECT  10.176 0.811 11.544 1.187 ;
     RECT  13.056 0.611 13.08 1.187 ;
     RECT  14.4 1.131 16.872 1.187 ;
     RECT  17.856 1.131 25.752 1.187 ;
     RECT  27.072 0.611 28.632 1.187 ;
     RECT  29.952 1.139 30.168 1.187 ;
     RECT  32.64 0.611 39.192 1.187 ;
     RECT  40.32 0.659 40.344 1.187 ;
     RECT  41.856 1.131 44.568 1.187 ;
     RECT  45.696 1.131 58.008 1.187 ;
     RECT  59.52 0.611 60.888 1.187 ;
     RECT  62.4 0.611 67.416 1.187 ;
     RECT  69.888 1.131 72.6 1.187 ;
     RECT  74.688 1.131 76.632 1.187 ;
     RECT  77.76 1.131 77.784 1.187 ;
     RECT  79.104 0.811 84.504 1.187 ;
     RECT  85.824 0.811 88.92 1.187 ;
     RECT  91.584 0.611 95.064 1.187 ;
     RECT  97.44 1.139 99.576 1.187 ;
     RECT  100.608 1.139 100.632 1.187 ;
     RECT  102.336 1.131 104.28 1.187 ;
     RECT  24.768 1.187 24.792 1.235 ;
     RECT  30.144 1.187 30.168 1.235 ;
     RECT  45.888 1.187 46.152 1.235 ;
     RECT  74.88 1.187 76.152 1.235 ;
     RECT  3.552 1.187 4.008 1.387 ;
     RECT  51.456 1.187 51.96 1.387 ;
     RECT  41.856 1.187 42.216 1.451 ;
     RECT  99.552 1.187 99.576 1.579 ;
     RECT  17.856 1.187 18.84 1.643 ;
     RECT  32.64 1.187 33.144 1.653 ;
     RECT  90.096 0.611 90.456 1.653 ;
     RECT  94.848 1.187 95.064 1.653 ;
     RECT  30.768 1.653 30.792 1.669 ;
     RECT  59.52 1.187 59.952 1.669 ;
     RECT  30.768 1.669 31.32 1.715 ;
     RECT  32.496 1.653 33.144 1.715 ;
     RECT  41.28 1.653 41.448 1.715 ;
     RECT  47.568 1.187 49.656 1.715 ;
     RECT  89.76 1.653 90.456 1.715 ;
     RECT  91.92 1.187 92.352 1.715 ;
     RECT  94.848 1.653 95.832 1.715 ;
     RECT  27.072 1.187 27.672 1.717 ;
     RECT  17.856 1.643 17.88 1.763 ;
     RECT  72.576 1.187 72.6 1.763 ;
     RECT  34.8 1.187 34.824 1.771 ;
     RECT  10.752 1.187 11.352 1.811 ;
     RECT  32.544 1.715 33.144 1.811 ;
     RECT  38.04 1.187 38.76 1.811 ;
     RECT  65.04 1.187 66.744 1.811 ;
     RECT  78.048 1.717 78.072 1.811 ;
     RECT  86.64 1.187 87.864 1.811 ;
     RECT  26.784 1.717 27.672 1.859 ;
     RECT  46.128 1.235 46.152 1.955 ;
     RECT  57.024 1.187 57.048 2.027 ;
     RECT  58.656 1.669 59.952 2.027 ;
     RECT  61.152 1.957 61.176 2.027 ;
     RECT  14.928 1.187 14.952 2.155 ;
     RECT  90.576 2.101 90.6 2.155 ;
     RECT  16.44 1.187 16.752 2.197 ;
     RECT  65.04 1.811 66.168 2.197 ;
     RECT  84.096 1.187 84.12 2.197 ;
     RECT  47.568 1.715 47.592 2.219 ;
     RECT  21.84 1.187 22.872 2.229 ;
     RECT  75.84 1.235 76.152 2.229 ;
     RECT  102.84 1.187 103.152 2.229 ;
     RECT  48.84 1.715 49.656 2.243 ;
     RECT  97.44 1.187 97.752 2.245 ;
     RECT  102.84 2.229 103.944 2.245 ;
     RECT  4.56 2.197 4.584 2.283 ;
     RECT  67.2 2.197 67.656 2.283 ;
     RECT  83.184 2.197 84.12 2.283 ;
     RECT  21.12 2.229 22.872 2.291 ;
     RECT  64.32 2.197 66.168 2.291 ;
     RECT  102.624 2.245 103.944 2.291 ;
     RECT  5.64 1.187 6.072 2.293 ;
     RECT  16.08 2.197 16.752 2.293 ;
     RECT  51.456 1.387 51.48 2.293 ;
     RECT  63.12 1.187 63.192 2.293 ;
     RECT  64.32 2.291 65.352 2.293 ;
     RECT  75.84 2.229 76.968 2.293 ;
     RECT  79.2 2.197 79.224 2.293 ;
     RECT  80.304 1.187 81.552 2.293 ;
     RECT  84.096 2.283 84.12 2.293 ;
     RECT  92.04 1.715 92.352 2.293 ;
     RECT  94.848 1.715 95.16 2.293 ;
     RECT  97.44 2.245 97.848 2.293 ;
     RECT  84.096 2.293 84.888 2.339 ;
     RECT  5.136 2.293 6.072 2.347 ;
     RECT  16.08 2.293 17.208 2.347 ;
     RECT  21.648 2.291 22.872 2.347 ;
     RECT  29.184 2.293 29.208 2.347 ;
     RECT  39.744 2.293 40.248 2.347 ;
     RECT  41.424 1.715 41.448 2.347 ;
     RECT  44.736 2.293 44.76 2.347 ;
     RECT  94.272 2.293 95.16 2.347 ;
     RECT  99.936 2.293 101.208 2.347 ;
     RECT  7.344 2.293 7.368 2.387 ;
     RECT  9.312 2.293 9.336 2.387 ;
     RECT  21.648 2.347 22.776 2.387 ;
     RECT  51.264 2.293 51.48 2.387 ;
     RECT  61.632 2.197 62.04 2.387 ;
     RECT  84.384 2.339 84.888 2.387 ;
     RECT  99.936 2.347 100.248 2.387 ;
     RECT  79.2 2.293 81.552 2.389 ;
     RECT  32.544 1.811 33.048 2.411 ;
     RECT  54.24 1.187 54.552 2.421 ;
     RECT  89.472 2.293 89.496 2.421 ;
     RECT  54.24 2.421 55.128 2.483 ;
     RECT  63.12 2.293 65.352 2.483 ;
     RECT  75.84 2.293 77.544 2.483 ;
     RECT  86.64 1.811 86.952 2.485 ;
     RECT  89.184 2.421 89.496 2.485 ;
     RECT  89.088 2.485 89.496 2.539 ;
     RECT  5.64 2.347 6.072 2.613 ;
     RECT  12.384 2.229 12.408 2.667 ;
     RECT  1.68 2.293 1.704 2.677 ;
     RECT  38.04 1.811 38.352 2.677 ;
     RECT  58.752 2.027 59.952 2.677 ;
     RECT  10.896 1.811 11.352 2.723 ;
     RECT  93.504 2.421 93.528 2.723 ;
     RECT  43.44 1.187 43.752 2.725 ;
     RECT  78.672 2.389 81.552 2.725 ;
     RECT  96.912 2.293 97.848 2.725 ;
     RECT  1.68 2.677 2.184 2.731 ;
     RECT  31.2 1.715 31.32 2.731 ;
     RECT  58.752 2.677 60.456 2.731 ;
     RECT  96.768 2.725 97.848 2.741 ;
     RECT  99.6 2.677 99.72 2.741 ;
     RECT  37.632 2.677 38.352 2.771 ;
     RECT  69.36 2.293 69.384 2.773 ;
     RECT  72.672 2.197 74.76 2.773 ;
     RECT  5.64 2.613 6.888 2.795 ;
     RECT  17.952 2.725 17.976 2.795 ;
     RECT  43.44 2.725 44.424 2.795 ;
     RECT  64.704 2.483 65.352 2.795 ;
     RECT  96.768 2.741 99.72 2.795 ;
     RECT  0.24 1.187 0.552 2.805 ;
     RECT  16.08 2.347 16.752 2.805 ;
     RECT  62.016 2.387 62.04 2.805 ;
     RECT  63.12 2.483 63.144 2.805 ;
     RECT  71.808 2.773 74.76 2.805 ;
     RECT  75.84 2.483 76.728 2.805 ;
     RECT  27.24 1.859 27.672 2.821 ;
     RECT  92.04 2.293 92.472 2.821 ;
     RECT  8.496 2.773 8.52 2.859 ;
     RECT  14.64 2.773 14.664 2.859 ;
     RECT  71.808 2.805 76.728 2.859 ;
     RECT  78.672 2.725 82.104 2.859 ;
     RECT  0.24 2.805 1.512 2.867 ;
     RECT  84.384 2.387 84.408 2.867 ;
     RECT  86.544 2.485 86.952 2.867 ;
     RECT  3.552 1.387 3.576 2.869 ;
     RECT  31.2 2.731 31.224 2.869 ;
     RECT  32.64 2.411 33.048 2.869 ;
     RECT  34.224 2.245 34.248 2.869 ;
     RECT  67.488 2.283 67.656 2.869 ;
     RECT  68.784 2.773 69.384 2.869 ;
     RECT  70.44 1.187 70.752 2.869 ;
     RECT  78.672 2.859 81.672 2.869 ;
     RECT  92.04 2.821 92.76 2.869 ;
     RECT  72.768 2.859 76.728 2.915 ;
     RECT  3.36 2.869 3.96 2.963 ;
     RECT  9.648 2.869 9.672 2.963 ;
     RECT  30.576 2.869 31.224 2.963 ;
     RECT  32.64 2.869 35.544 2.963 ;
     RECT  51.888 2.869 51.912 2.963 ;
     RECT  62.016 2.805 63.144 2.963 ;
     RECT  67.488 2.869 70.752 2.963 ;
     RECT  72.768 2.915 73.56 2.963 ;
     RECT  74.688 2.915 76.728 2.963 ;
     RECT  85.44 2.869 85.464 2.963 ;
     RECT  88.32 2.869 88.344 2.963 ;
     RECT  89.808 2.869 89.832 2.963 ;
     RECT  91.824 2.869 92.76 2.963 ;
     RECT  97.44 2.795 99.72 2.963 ;
     RECT  99.696 2.963 99.72 3.011 ;
     RECT  24.624 2.869 24.648 3.051 ;
     RECT  69.264 2.963 70.752 3.059 ;
     RECT  74.688 2.963 76.248 3.059 ;
     RECT  91.92 2.963 92.76 3.059 ;
     RECT  46.128 2.933 46.152 3.155 ;
     RECT  96.24 2.869 96.264 3.155 ;
     RECT  27.24 2.821 28.344 3.301 ;
     RECT  36.432 3.205 36.456 3.301 ;
     RECT  36.432 3.301 36.792 3.307 ;
     RECT  74.688 3.059 76.152 3.307 ;
     RECT  78.288 2.869 81.672 3.307 ;
     RECT  78.288 3.307 81.552 3.347 ;
     RECT  15.84 2.805 16.752 3.349 ;
     RECT  26.688 3.301 28.344 3.371 ;
     RECT  29.472 3.301 29.496 3.371 ;
     RECT  78.288 3.347 79.272 3.371 ;
     RECT  32.64 2.963 35.448 3.435 ;
     RECT  36.768 3.307 36.792 3.435 ;
     RECT  46.464 3.349 46.776 3.435 ;
     RECT  63.12 2.963 63.144 3.443 ;
     RECT  80.4 3.347 81.552 3.443 ;
     RECT  95.136 2.347 95.16 3.443 ;
     RECT  102.624 2.291 103.152 3.443 ;
     RECT  5.64 2.795 6.648 3.445 ;
     RECT  48.84 2.243 49.152 3.445 ;
     RECT  65.04 2.795 65.352 3.445 ;
     RECT  4.896 3.445 6.648 3.539 ;
     RECT  29.568 3.445 29.592 3.539 ;
     RECT  34.464 3.435 35.448 3.539 ;
     RECT  45.12 3.445 45.144 3.539 ;
     RECT  48.192 3.445 49.152 3.539 ;
     RECT  57.504 3.445 57.528 3.539 ;
     RECT  78.288 3.371 78.312 3.539 ;
     RECT  83.76 3.445 83.784 3.539 ;
     RECT  94.656 3.445 94.68 3.539 ;
     RECT  101.712 3.445 101.736 3.539 ;
     RECT  15.216 3.349 16.752 3.627 ;
     RECT  65.04 3.445 65.448 3.635 ;
     RECT  18.72 3.445 18.744 3.637 ;
     RECT  21.648 2.387 22.152 3.637 ;
     RECT  21.36 3.637 22.824 3.691 ;
     RECT  54.24 2.483 54.552 3.733 ;
     RECT  97.44 2.963 98.664 3.779 ;
     RECT  41.28 3.445 42.264 3.781 ;
     RECT  43.44 2.795 43.752 3.781 ;
     RECT  24.672 3.733 24.696 3.819 ;
     RECT  53.952 3.733 54.552 3.819 ;
     RECT  57.648 3.733 57.672 3.819 ;
     RECT  75.12 3.307 76.152 3.819 ;
     RECT  51.696 3.397 51.72 3.829 ;
     RECT  51.456 3.829 51.72 3.883 ;
     RECT  21.744 3.691 22.824 3.925 ;
     RECT  26.688 3.371 27.552 3.925 ;
     RECT  54.096 3.819 54.552 3.925 ;
     RECT  18.72 3.637 19.176 3.957 ;
     RECT  67.488 2.963 67.512 3.957 ;
     RECT  9.696 3.925 9.72 4.011 ;
     RECT  17.952 3.957 19.176 4.011 ;
     RECT  21.744 3.925 23.496 4.011 ;
     RECT  54.096 3.925 55.224 4.011 ;
     RECT  80.88 3.443 81.552 4.011 ;
     RECT  13.632 3.573 13.656 4.019 ;
     RECT  58.752 2.731 59.952 4.021 ;
     RECT  62.016 2.963 62.04 4.021 ;
     RECT  65.04 3.635 65.352 4.021 ;
     RECT  70.44 3.059 70.752 4.021 ;
     RECT  11.04 2.723 11.352 4.069 ;
     RECT  5.64 3.539 6.648 4.085 ;
     RECT  11.04 4.069 11.448 4.085 ;
     RECT  17.952 4.011 18.84 4.115 ;
     RECT  41.28 3.781 43.752 4.115 ;
     RECT  64.32 4.021 65.352 4.115 ;
     RECT  84.096 4.021 84.12 4.115 ;
     RECT  90.528 4.021 90.552 4.115 ;
     RECT  99.312 4.021 99.672 4.115 ;
     RECT  31.2 2.963 31.224 4.117 ;
     RECT  9.84 4.085 11.448 4.139 ;
     RECT  31.2 4.117 31.608 4.149 ;
     RECT  32.64 3.435 32.952 4.149 ;
     RECT  5.64 4.085 6.888 4.163 ;
     RECT  8.736 4.085 8.76 4.163 ;
     RECT  9.84 4.139 11.352 4.163 ;
     RECT  70.44 4.021 70.872 4.163 ;
     RECT  31.2 4.149 32.952 4.203 ;
     RECT  31.2 4.203 31.224 4.261 ;
     RECT  37.92 2.771 38.352 4.261 ;
     RECT  86.64 2.867 86.952 4.261 ;
     RECT  102.84 3.443 103.152 4.261 ;
     RECT  37.392 4.261 38.352 4.277 ;
     RECT  18.816 4.115 18.84 4.331 ;
     RECT  34.656 3.539 35.448 4.331 ;
     RECT  37.392 4.277 38.808 4.331 ;
     RECT  34.656 4.331 34.824 4.355 ;
     RECT  37.824 4.331 38.808 4.355 ;
     RECT  66.432 4.341 66.456 4.357 ;
     RECT  67.488 3.957 67.848 4.357 ;
     RECT  66.432 4.357 67.848 4.403 ;
     RECT  72.864 2.963 73.56 4.405 ;
     RECT  102.84 4.261 104.088 4.405 ;
     RECT  66.528 4.403 67.848 4.459 ;
     RECT  46.464 3.435 46.488 4.501 ;
     RECT  48.84 3.539 49.152 4.501 ;
     RECT  51.696 3.883 51.72 4.501 ;
     RECT  62.016 4.021 62.664 4.501 ;
     RECT  69.264 3.059 69.336 4.501 ;
     RECT  70.44 4.163 70.752 4.501 ;
     RECT  0.24 2.867 0.552 4.533 ;
     RECT  26.64 3.925 27.552 4.533 ;
     RECT  32.304 4.203 32.952 4.533 ;
     RECT  42.768 4.115 43.752 4.533 ;
     RECT  46.32 4.501 46.488 4.533 ;
     RECT  72.864 4.405 74.616 4.533 ;
     RECT  86.496 4.261 86.952 4.533 ;
     RECT  87.936 4.261 87.96 4.533 ;
     RECT  54.096 4.011 54.552 4.547 ;
     RECT  9.84 4.163 9.864 4.587 ;
     RECT  12.912 4.501 12.936 4.587 ;
     RECT  14.688 4.021 14.808 4.587 ;
     RECT  87.936 4.533 88.44 4.587 ;
     RECT  90.096 4.501 90.12 4.587 ;
     RECT  99.744 4.501 99.768 4.587 ;
     RECT  100.896 4.501 100.92 4.587 ;
     RECT  0.24 4.533 1.464 4.595 ;
     RECT  15.84 3.627 16.752 4.595 ;
     RECT  42.768 4.533 44.424 4.595 ;
     RECT  72.576 4.533 74.616 4.595 ;
     RECT  78.576 4.533 78.6 4.595 ;
     RECT  56.16 4.501 56.184 4.597 ;
     RECT  32.304 4.533 33.096 4.643 ;
     RECT  58.752 4.021 60.216 4.645 ;
     RECT  14.64 4.597 14.664 4.691 ;
     RECT  56.16 4.597 57.144 4.691 ;
     RECT  64.704 4.115 65.352 4.691 ;
     RECT  67.344 4.459 67.848 4.693 ;
     RECT  69.264 4.501 70.752 4.693 ;
     RECT  75.84 3.819 76.152 4.693 ;
     RECT  26.64 4.533 28.008 4.715 ;
     RECT  20.208 3.637 20.232 4.789 ;
     RECT  24.528 4.261 24.552 4.789 ;
     RECT  61.92 4.501 62.664 4.789 ;
     RECT  32.352 4.643 33.096 4.837 ;
     RECT  21.744 4.011 22.872 4.843 ;
     RECT  23.952 4.789 24.552 4.843 ;
     RECT  16.32 4.595 16.752 4.917 ;
     RECT  46.32 4.533 46.728 4.917 ;
     RECT  58.128 4.645 60.216 4.917 ;
     RECT  88.32 4.587 88.44 4.931 ;
     RECT  20.016 4.789 20.712 4.971 ;
     RECT  61.92 4.789 62.76 4.971 ;
     RECT  42.768 4.595 43.752 4.979 ;
     RECT  86.016 4.533 86.952 5.029 ;
     RECT  20.688 4.971 20.712 5.077 ;
     RECT  44.976 5.029 45 5.099 ;
     RECT  46.32 4.917 47.4 5.099 ;
     RECT  58.128 4.917 60.792 5.099 ;
     RECT  83.664 5.029 83.688 5.099 ;
     RECT  81.024 4.011 81.552 5.109 ;
     RECT  3.216 5.045 3.24 5.123 ;
     RECT  79.152 5.045 79.176 5.123 ;
     RECT  90.72 5.077 90.744 5.163 ;
     RECT  81.024 5.109 81.72 5.171 ;
     RECT  99.552 5.109 99.576 5.171 ;
     RECT  58.56 5.099 60.792 5.173 ;
     RECT  61.92 4.971 62.04 5.173 ;
     RECT  20.688 5.077 20.76 5.219 ;
     RECT  46.32 5.099 46.68 5.219 ;
     RECT  102.72 4.405 104.088 5.267 ;
     RECT  29.808 4.261 31.224 5.365 ;
     RECT  37.824 4.355 38.352 5.365 ;
     RECT  50.544 4.501 50.568 5.365 ;
     RECT  51.696 4.501 51.816 5.365 ;
     RECT  23.952 4.843 23.976 5.459 ;
     RECT  29.616 5.365 31.224 5.459 ;
     RECT  18.528 5.413 18.552 5.483 ;
     RECT  10.896 4.163 11.352 5.605 ;
     RECT  16.32 4.917 16.872 5.605 ;
     RECT  34.656 4.355 34.68 5.605 ;
     RECT  41.28 4.115 41.592 5.605 ;
     RECT  54.24 4.547 54.552 5.605 ;
     RECT  13.44 5.109 13.464 5.621 ;
     RECT  26.688 4.715 28.008 5.653 ;
     RECT  30.144 5.459 31.224 5.653 ;
     RECT  32.352 4.837 33.432 5.653 ;
     RECT  37.248 5.365 38.352 5.653 ;
     RECT  85.728 5.029 86.952 5.653 ;
     RECT  92.04 3.059 92.76 5.653 ;
     RECT  9.312 5.605 9.336 5.675 ;
     RECT  10.368 5.605 11.352 5.675 ;
     RECT  12.72 5.621 13.464 5.675 ;
     RECT  41.28 5.605 42.216 5.675 ;
     RECT  54.24 5.605 54.936 5.675 ;
     RECT  3.648 5.685 3.672 5.747 ;
     RECT  57.408 5.605 57.528 5.747 ;
     RECT  88.32 4.931 88.344 5.747 ;
     RECT  45.12 5.605 45.144 5.749 ;
     RECT  48.432 4.501 49.152 5.749 ;
     RECT  36.096 5.749 36.12 5.803 ;
     RECT  40.224 5.749 40.248 5.803 ;
     RECT  41.28 5.675 42.12 5.803 ;
     RECT  46.464 5.219 46.68 5.803 ;
     RECT  47.904 5.749 49.152 5.803 ;
     RECT  5.64 4.163 5.952 5.845 ;
     RECT  4.704 5.845 5.952 5.877 ;
     RECT  16.32 5.605 17.4 5.893 ;
     RECT  67.344 4.693 70.752 5.893 ;
     RECT  0.24 4.595 0.552 5.917 ;
     RECT  4.704 5.877 6.936 5.939 ;
     RECT  2.112 5.605 2.136 5.941 ;
     RECT  97.44 3.779 97.752 5.941 ;
     RECT  12.72 5.675 12.888 5.987 ;
     RECT  45.12 5.749 45.192 5.987 ;
     RECT  79.68 5.365 79.704 5.989 ;
     RECT  15.84 5.893 17.4 5.995 ;
     RECT  66.72 5.893 70.752 5.995 ;
     RECT  97.44 5.941 98.04 6.035 ;
     RECT  99.168 5.941 99.192 6.035 ;
     RECT  2.112 5.941 2.472 6.059 ;
     RECT  4.704 5.939 6.216 6.059 ;
     RECT  79.68 5.989 79.752 6.059 ;
     RECT  0.144 5.917 0.552 6.083 ;
     RECT  43.344 4.979 43.752 6.133 ;
     RECT  84.48 5.845 84.504 6.181 ;
     RECT  92.04 5.653 93.336 6.181 ;
     RECT  20.736 5.219 20.76 6.197 ;
     RECT  73.104 4.595 74.136 6.197 ;
     RECT  75.84 4.693 76.68 6.197 ;
     RECT  21.744 4.843 22.248 6.229 ;
     RECT  84.48 6.181 84.648 6.229 ;
     RECT  96.096 6.133 96.12 6.229 ;
     RECT  84.24 6.229 84.648 6.251 ;
     RECT  92.04 6.181 94.104 6.251 ;
     RECT  37.248 5.653 39.192 6.261 ;
     RECT  15.312 6.197 15.336 6.275 ;
     RECT  19.968 6.197 20.76 6.275 ;
     RECT  66.912 5.995 70.752 6.275 ;
     RECT  73.104 6.197 74.712 6.275 ;
     RECT  75.84 6.197 77.208 6.275 ;
     RECT  4.896 6.059 6.216 6.323 ;
     RECT  18.72 6.261 18.744 6.323 ;
     RECT  48.144 5.803 49.152 6.323 ;
     RECT  54.24 5.675 54.696 6.325 ;
     RECT  84.24 6.251 84.264 6.379 ;
     RECT  92.04 6.251 93.336 6.421 ;
     RECT  79.68 6.059 79.704 6.565 ;
     RECT  81.024 5.171 81.552 6.565 ;
     RECT  96.096 6.229 96.168 6.571 ;
     RECT  79.344 6.565 79.704 6.635 ;
     RECT  81.024 6.565 82.92 6.635 ;
     RECT  94.56 6.565 94.584 6.635 ;
     RECT  96.096 6.571 96.12 6.635 ;
     RECT  0.24 6.083 0.552 6.661 ;
     RECT  8.352 6.453 8.376 6.709 ;
     RECT  21.744 6.229 22.488 6.709 ;
     RECT  21.744 6.709 23.448 6.757 ;
     RECT  43.344 6.133 43.848 6.757 ;
     RECT  45.12 5.987 45.144 6.757 ;
     RECT  73.104 6.275 74.184 6.773 ;
     RECT  89.664 6.757 89.688 6.773 ;
     RECT  20.736 6.275 20.76 6.805 ;
     RECT  21.744 6.757 23.544 6.805 ;
     RECT  26.688 5.653 28.056 6.805 ;
     RECT  7.968 6.709 8.376 6.827 ;
     RECT  14.16 6.757 14.184 6.827 ;
     RECT  36.432 6.261 39.192 6.827 ;
     RECT  43.344 6.757 45.144 6.827 ;
     RECT  72.864 6.773 74.184 6.827 ;
     RECT  88.704 6.773 89.688 6.827 ;
     RECT  91.776 6.421 93.336 6.827 ;
     RECT  34.656 5.605 34.776 6.837 ;
     RECT  58.56 5.173 62.04 6.837 ;
     RECT  4.896 6.323 5.952 6.851 ;
     RECT  9.552 6.773 9.576 6.851 ;
     RECT  20.736 6.805 23.544 6.851 ;
     RECT  34.656 6.837 35.736 6.851 ;
     RECT  43.344 6.827 43.752 6.851 ;
     RECT  66.912 6.275 67.224 6.851 ;
     RECT  72.864 6.827 74.136 6.851 ;
     RECT  82.848 6.635 82.92 6.851 ;
     RECT  101.76 6.517 101.784 6.851 ;
     RECT  85.728 5.653 87.048 6.853 ;
     RECT  8.496 6.837 8.52 6.899 ;
     RECT  34.752 6.851 35.736 6.899 ;
     RECT  58.56 6.837 62.616 6.899 ;
     RECT  67.2 6.851 67.224 6.899 ;
     RECT  81.024 6.635 81.552 6.899 ;
     RECT  99.888 6.517 99.912 6.899 ;
     RECT  20.736 6.851 22.488 6.947 ;
     RECT  82.896 6.851 82.92 6.947 ;
     RECT  48.72 6.323 49.152 7.189 ;
     RECT  50.544 5.365 52.44 7.189 ;
     RECT  30.144 5.653 33.576 7.333 ;
     RECT  2.112 6.059 2.136 7.381 ;
     RECT  3.408 7.189 3.432 7.381 ;
     RECT  23.808 7.333 23.832 7.403 ;
     RECT  25.824 6.805 28.056 7.403 ;
     RECT  29.952 7.333 33.576 7.403 ;
     RECT  16.32 5.995 17.4 7.413 ;
     RECT  20.736 6.947 20.76 7.413 ;
     RECT  53.712 6.325 54.696 7.413 ;
     RECT  75.84 6.275 76.872 7.413 ;
     RECT  2.112 7.381 3.432 7.467 ;
     RECT  2.112 7.467 3.192 7.475 ;
     RECT  9.6 7.413 9.624 7.475 ;
     RECT  15.984 7.413 17.4 7.475 ;
     RECT  19.872 7.413 20.76 7.475 ;
     RECT  21.744 6.947 22.488 7.475 ;
     RECT  53.52 7.413 54.696 7.475 ;
     RECT  67.344 7.413 67.368 7.475 ;
     RECT  83.616 7.413 83.64 7.475 ;
     RECT  48.72 7.189 52.44 7.571 ;
     RECT  85.728 6.853 87.144 7.571 ;
     RECT  88.704 6.827 88.728 7.619 ;
     RECT  75.84 7.413 77.016 7.763 ;
     RECT  2.112 7.475 2.808 7.851 ;
     RECT  79.68 6.635 79.704 7.861 ;
     RECT  102.84 5.267 104.088 7.861 ;
     RECT  0.24 6.661 0.84 7.907 ;
     RECT  92.04 6.827 93.336 7.909 ;
     RECT  79.296 7.861 79.704 7.915 ;
     RECT  43.44 6.851 43.752 7.957 ;
     RECT  45.12 6.827 45.144 7.957 ;
     RECT  63.264 7.909 63.288 7.979 ;
     RECT  5.64 6.851 5.952 7.989 ;
     RECT  58.56 6.899 62.04 8.003 ;
     RECT  23.28 7.989 23.304 8.051 ;
     RECT  66.336 7.989 66.36 8.051 ;
     RECT  84.192 7.989 84.216 8.051 ;
     RECT  10.896 5.675 11.352 8.149 ;
     RECT  25.2 8.117 25.224 8.195 ;
     RECT  48.72 7.571 49.704 8.195 ;
     RECT  77.808 7.861 77.832 8.195 ;
     RECT  10.848 8.149 11.352 8.235 ;
     RECT  7.44 7.989 7.608 8.243 ;
     RECT  20.736 7.475 20.76 8.293 ;
     RECT  21.744 7.475 22.152 8.293 ;
     RECT  85.824 7.571 87.144 8.293 ;
     RECT  12.864 5.987 12.888 8.373 ;
     RECT  12.864 8.373 13.368 8.435 ;
     RECT  14.352 8.373 14.376 8.435 ;
     RECT  16.32 7.475 17.4 8.437 ;
     RECT  20.736 8.293 22.152 8.437 ;
     RECT  65.04 4.691 65.352 8.437 ;
     RECT  102.84 7.861 104.28 8.437 ;
     RECT  68.352 6.275 70.752 8.485 ;
     RECT  63.792 8.437 63.816 8.491 ;
     RECT  4.896 7.989 5.952 8.533 ;
     RECT  9.456 8.149 9.48 8.533 ;
     RECT  16.32 8.437 18.12 8.533 ;
     RECT  20.544 8.437 22.152 8.533 ;
     RECT  48.84 8.195 49.704 8.533 ;
     RECT  50.688 7.571 52.44 8.533 ;
     RECT  68.256 8.485 71.112 8.533 ;
     RECT  97.44 6.035 97.752 8.533 ;
     RECT  68.256 8.533 72.024 8.555 ;
     RECT  43.44 7.957 45.144 8.565 ;
     RECT  48.84 8.533 52.44 8.627 ;
     RECT  102.048 8.437 104.28 8.675 ;
     RECT  72 8.555 72.024 8.725 ;
     RECT  65.04 8.437 65.832 8.757 ;
     RECT  68.256 8.555 70.752 8.811 ;
     RECT  56.16 4.691 56.184 9.013 ;
     RECT  85.824 8.293 87.336 9.059 ;
     RECT  0.24 7.907 0.552 9.061 ;
     RECT  34.752 6.899 34.776 9.061 ;
     RECT  79.68 7.915 79.704 9.061 ;
     RECT  81.12 6.899 81.552 9.061 ;
     RECT  91.392 7.909 93.336 9.061 ;
     RECT  56.064 9.013 56.424 9.067 ;
     RECT  4.416 8.533 5.952 9.109 ;
     RECT  8.256 8.533 9.48 9.109 ;
     RECT  10.896 8.235 11.352 9.109 ;
     RECT  12.864 8.435 13.08 9.109 ;
     RECT  16.32 8.533 18.264 9.109 ;
     RECT  19.968 8.533 22.152 9.109 ;
     RECT  30.144 7.403 33.576 9.109 ;
     RECT  34.752 9.061 35.736 9.109 ;
     RECT  43.2 8.565 45.144 9.109 ;
     RECT  46.464 5.803 46.488 9.109 ;
     RECT  51.792 8.627 52.44 9.109 ;
     RECT  57.408 5.747 57.432 9.109 ;
     RECT  58.56 8.003 60.696 9.109 ;
     RECT  62.016 8.003 62.04 9.109 ;
     RECT  64.08 8.757 65.832 9.109 ;
     RECT  67.008 8.757 67.032 9.109 ;
     RECT  72 8.725 72.12 9.109 ;
     RECT  73.104 6.851 74.136 9.109 ;
     RECT  75.84 7.763 76.536 9.109 ;
     RECT  81.12 9.061 82.392 9.109 ;
     RECT  85.824 9.059 87.144 9.109 ;
     RECT  79.68 9.061 79.896 9.141 ;
     RECT  84.864 9.109 87.144 9.141 ;
     RECT  90.816 9.061 93.336 9.141 ;
     RECT  26.688 7.403 28.056 9.157 ;
     RECT  79.152 9.141 79.896 9.203 ;
     RECT  84.288 9.141 87.144 9.203 ;
     RECT  90.816 9.141 93.624 9.203 ;
     RECT  75.84 9.109 76.632 9.205 ;
     RECT  77.76 9.109 77.784 9.205 ;
     RECT  43.008 9.109 45.144 9.349 ;
     RECT  46.464 9.109 47.064 9.349 ;
     RECT  75.84 9.205 77.784 9.397 ;
     RECT  92.04 9.203 93.624 9.397 ;
     RECT  100.8 9.061 100.824 9.397 ;
     RECT  3.84 9.109 6.744 9.541 ;
     RECT  8.256 9.109 9.624 9.541 ;
     RECT  25.152 9.493 25.176 9.541 ;
     RECT  26.688 9.157 28.248 9.541 ;
     RECT  48.84 8.627 50.712 9.589 ;
     RECT  56.064 9.067 56.184 9.589 ;
     RECT  2.112 7.851 2.712 9.637 ;
     RECT  3.84 9.541 9.624 9.637 ;
     RECT  10.896 9.109 13.08 9.637 ;
     RECT  15.744 9.109 22.68 9.637 ;
     RECT  25.152 9.541 28.248 9.637 ;
     RECT  37.248 6.827 39.192 9.637 ;
     RECT  41.28 5.803 41.304 9.637 ;
     RECT  43.008 9.349 47.064 9.637 ;
     RECT  48.72 9.589 50.712 9.637 ;
     RECT  54.24 7.475 54.696 9.637 ;
     RECT  55.68 9.589 56.184 9.637 ;
     RECT  57.408 9.109 60.696 9.637 ;
     RECT  62.016 9.109 62.616 9.637 ;
     RECT  64.08 9.109 67.032 9.637 ;
     RECT  79.68 9.203 79.896 9.637 ;
     RECT  81.12 9.109 83.16 9.637 ;
     RECT  92.04 9.397 94.296 9.637 ;
     RECT  96.96 8.533 97.752 9.637 ;
     RECT  24.96 9.637 28.248 9.685 ;
     RECT  29.952 9.109 35.736 9.685 ;
     RECT  41.28 9.637 41.496 9.685 ;
     RECT  90.816 9.203 90.84 9.685 ;
     RECT  24.96 9.685 35.736 9.717 ;
     RECT  41.28 9.685 41.88 9.717 ;
     RECT  43.008 9.637 50.712 9.717 ;
     RECT  24.96 9.717 36.024 9.779 ;
     RECT  41.28 9.717 50.712 10.165 ;
     RECT  2.112 9.637 13.08 10.213 ;
     RECT  57.216 9.637 60.696 10.213 ;
     RECT  62.016 9.637 67.032 10.213 ;
     RECT  68.352 8.811 70.752 10.213 ;
     RECT  75.84 9.397 78.648 10.213 ;
     RECT  79.68 9.637 80.088 10.213 ;
     RECT  81.072 9.637 83.16 10.213 ;
     RECT  90.624 9.685 90.84 10.213 ;
     RECT  96.192 9.637 97.752 10.213 ;
     RECT  72 9.109 74.328 10.261 ;
     RECT  40.704 10.165 50.712 10.309 ;
     RECT  51.792 9.109 53.208 10.309 ;
     RECT  0.144 9.061 0.552 10.355 ;
     RECT  92.04 9.637 95.064 10.501 ;
     RECT  96.192 10.213 98.328 10.501 ;
     RECT  40.704 10.309 53.208 10.645 ;
     RECT  54.24 9.637 56.184 10.645 ;
     RECT  0.24 10.355 0.552 10.741 ;
     RECT  2.112 10.213 13.848 10.741 ;
     RECT  72 10.261 74.712 10.741 ;
     RECT  75.84 10.213 83.16 10.741 ;
     RECT  100.8 9.397 101.4 10.741 ;
     RECT  14.976 9.637 23.256 10.789 ;
     RECT  24.96 9.779 35.88 10.789 ;
     RECT  37.248 9.637 39.576 10.789 ;
     RECT  68.352 10.213 70.872 10.789 ;
     RECT  88.32 9.109 88.728 10.789 ;
     RECT  89.856 10.213 90.84 10.789 ;
     RECT  92.04 10.501 98.328 10.789 ;
     RECT  102.528 8.675 104.28 10.789 ;
     RECT  68.16 10.789 70.872 10.805 ;
     RECT  72 10.741 83.16 10.805 ;
     RECT  100.032 10.741 101.4 10.805 ;
     RECT  0.24 10.741 13.848 10.837 ;
     RECT  14.976 10.789 23.64 10.837 ;
     RECT  24.96 10.789 39.576 10.837 ;
     RECT  40.704 10.645 56.184 10.837 ;
     RECT  57.216 10.213 67.032 10.837 ;
     RECT  68.16 10.805 83.16 10.837 ;
     RECT  84.672 9.203 87.144 10.837 ;
     RECT  88.128 10.789 88.728 10.837 ;
     RECT  89.856 10.789 98.328 10.837 ;
     RECT  99.648 10.805 101.4 10.837 ;
     RECT  102.528 10.789 104.472 10.837 ;
     RECT  0.24 10.837 23.64 11.029 ;
     RECT  24.96 10.837 56.184 11.029 ;
     RECT  57.216 10.837 87.144 11.029 ;
     RECT  88.128 10.837 104.664 11.029 ;
     RECT  0.24 11.029 104.664 11.363 ;
     RECT  0.384 11.363 104.664 11.728 ;
     RECT  30.576 11.728 30.6 11.795 ;
     RECT  33.552 11.728 33.576 11.795 ;
     RECT  51.792 11.728 51.816 11.795 ;
    LAYER M6 ;
     RECT  1.429 4.544 1.515 4.576 ;
     RECT  1.461 2.816 1.523 2.848 ;
     RECT  0.805 7.808 2.149 7.84 ;
     RECT  2.149 7.424 2.819 7.84 ;
     RECT  2.437 6.016 3.189 6.048 ;
     RECT  3.189 5.056 3.251 6.048 ;
     RECT  1.669 2.304 3.349 2.72 ;
     RECT  3.349 2.304 3.381 2.912 ;
     RECT  3.381 1.088 3.443 2.912 ;
     RECT  3.251 5.696 3.691 6.048 ;
     RECT  3.691 6.016 4.739 6.048 ;
     RECT  3.443 1.344 4.853 2.912 ;
     RECT  2.819 7.424 4.853 7.456 ;
     RECT  4.853 1.088 4.931 3.488 ;
     RECT  4.853 6.784 4.931 8.032 ;
     RECT  4.931 1.088 4.979 3.296 ;
     RECT  4.981 0.192 5.035 0.224 ;
     RECT  4.979 2.304 5.171 3.296 ;
     RECT  6.181 6.272 6.251 6.304 ;
     RECT  5.171 2.752 6.613 3.296 ;
     RECT  6.613 2.752 6.659 4.128 ;
     RECT  6.659 2.752 6.853 2.784 ;
     RECT  6.853 2.624 6.899 2.784 ;
     RECT  6.899 2.624 7.333 2.656 ;
     RECT  7.333 2.304 7.403 2.656 ;
     RECT  4.931 8 7.429 8.032 ;
     RECT  7.349 0.192 7.523 0.224 ;
     RECT  6.901 5.888 7.605 5.92 ;
     RECT  7.429 8 7.605 8.224 ;
     RECT  7.605 5.888 7.659 8.224 ;
     RECT  7.659 5.888 8.373 6.88 ;
     RECT  7.403 2.624 8.485 2.656 ;
     RECT  6.659 4.096 8.485 4.128 ;
     RECT  8.485 2.624 9.301 4.128 ;
     RECT  9.301 2.304 9.387 4.128 ;
     RECT  9.333 0.192 9.443 0.224 ;
     RECT  8.373 5.632 9.587 6.88 ;
     RECT  7.659 8.192 9.589 8.224 ;
     RECT  9.387 2.624 9.707 4.128 ;
     RECT  9.707 3.968 9.731 4.128 ;
     RECT  9.731 4.096 9.829 4.128 ;
     RECT  9.587 5.632 9.829 5.664 ;
     RECT  9.653 0.768 10.741 0.8 ;
     RECT  9.707 2.624 10.741 2.656 ;
     RECT  10.741 0.768 10.795 2.656 ;
     RECT  9.589 7.424 10.883 8.224 ;
     RECT  9.829 4.096 10.923 5.664 ;
     RECT  10.883 7.424 10.979 7.904 ;
     RECT  10.979 7.872 10.987 7.904 ;
     RECT  10.795 0.768 11.459 0.8 ;
     RECT  10.923 4.096 11.459 4.128 ;
     RECT  10.933 9.728 11.459 9.76 ;
     RECT  10.795 2.624 12.373 2.656 ;
     RECT  12.373 2.24 12.419 2.656 ;
     RECT  10.923 5.44 12.901 5.664 ;
     RECT  12.901 4.544 12.971 5.664 ;
     RECT  12.661 10.816 12.971 10.848 ;
     RECT  12.971 5.12 14.133 5.664 ;
     RECT  14.133 5.12 14.195 6.816 ;
     RECT  13.333 8.384 14.387 8.416 ;
     RECT  12.419 2.24 14.629 2.272 ;
     RECT  13.621 3.584 14.629 3.616 ;
     RECT  14.195 5.12 14.629 6.24 ;
     RECT  14.629 2.24 14.709 6.24 ;
     RECT  14.709 2.112 14.963 6.24 ;
     RECT  14.963 2.24 15.347 6.24 ;
     RECT  15.347 2.24 15.915 5.984 ;
     RECT  15.915 2.24 16.019 3.488 ;
     RECT  15.861 7.424 16.019 7.456 ;
     RECT  16.019 2.24 16.501 3.104 ;
     RECT  16.501 1.088 16.555 3.104 ;
     RECT  16.555 1.088 16.931 2.336 ;
     RECT  16.931 2.304 17.259 2.336 ;
     RECT  15.915 4.928 17.269 5.472 ;
     RECT  17.205 0.192 17.315 0.224 ;
     RECT  17.269 4.928 17.323 6.752 ;
     RECT  17.323 4.928 17.941 5.472 ;
     RECT  17.941 2.752 18.613 5.472 ;
     RECT  18.613 1.472 18.709 5.472 ;
     RECT  18.709 1.472 18.795 6.304 ;
     RECT  18.795 1.6 18.851 6.304 ;
     RECT  18.851 2.752 19.861 6.304 ;
     RECT  16.837 8.448 19.861 8.48 ;
     RECT  19.861 2.752 19.947 8.48 ;
     RECT  19.947 2.752 20.003 6.24 ;
     RECT  20.003 2.752 21.109 5.472 ;
     RECT  21.109 2.24 21.163 5.472 ;
     RECT  19.947 8.448 21.779 8.48 ;
     RECT  21.163 2.752 22.197 5.472 ;
     RECT  22.197 2.752 22.741 5.792 ;
     RECT  22.741 2.304 22.883 5.792 ;
     RECT  22.453 7.36 23.269 7.392 ;
     RECT  22.883 3.008 23.285 5.792 ;
     RECT  23.269 7.36 23.285 8.032 ;
     RECT  23.285 3.008 23.339 8.032 ;
     RECT  23.339 3.008 23.467 7.392 ;
     RECT  23.467 3.008 24.563 5.472 ;
     RECT  24.563 3.008 24.659 3.808 ;
     RECT  24.563 5.44 24.757 5.472 ;
     RECT  23.467 6.784 24.757 7.392 ;
     RECT  24.659 3.776 24.811 3.808 ;
     RECT  24.757 5.44 24.811 7.392 ;
     RECT  24.811 6.528 25.141 7.392 ;
     RECT  25.141 6.528 25.235 8.16 ;
     RECT  25.235 6.528 25.859 7.392 ;
     RECT  26.293 0.192 26.347 0.224 ;
     RECT  26.613 3.968 26.629 4 ;
     RECT  26.629 3.968 26.677 4.704 ;
     RECT  26.485 10.816 26.795 10.848 ;
     RECT  26.293 1.728 26.819 1.76 ;
     RECT  25.859 6.528 27.381 6.816 ;
     RECT  27.381 6.528 27.573 8.032 ;
     RECT  27.573 6.528 27.683 8.608 ;
     RECT  26.677 3.328 28.019 4.704 ;
     RECT  28.019 3.328 29.173 4.576 ;
     RECT  29.173 0.192 29.227 0.224 ;
     RECT  29.173 2.304 29.227 4.576 ;
     RECT  29.227 3.328 29.557 4.576 ;
     RECT  27.683 6.528 29.557 7.392 ;
     RECT  29.557 3.328 29.611 7.392 ;
     RECT  29.557 1.088 29.699 1.12 ;
     RECT  30.517 2.88 30.709 2.912 ;
     RECT  29.611 4.416 30.763 7.392 ;
     RECT  30.709 1.664 30.803 2.912 ;
     RECT  30.517 0.192 31.147 0.224 ;
     RECT  30.803 2.688 31.147 2.912 ;
     RECT  30.763 4.416 31.573 4.576 ;
     RECT  30.763 6.528 31.715 7.392 ;
     RECT  31.147 2.688 32.245 2.72 ;
     RECT  31.573 4.16 32.341 4.576 ;
     RECT  32.245 0.512 32.373 0.544 ;
     RECT  32.245 2.368 32.373 2.72 ;
     RECT  32.341 4.16 32.427 5.152 ;
     RECT  32.373 0.512 33.013 2.72 ;
     RECT  33.013 0.192 33.067 2.72 ;
     RECT  32.427 4.16 33.107 4.576 ;
     RECT  33.067 1.088 33.155 2.72 ;
     RECT  33.155 2.688 33.589 2.72 ;
     RECT  33.107 4.16 33.589 4.192 ;
     RECT  33.155 1.088 34.597 1.12 ;
     RECT  34.597 1.024 34.667 1.12 ;
     RECT  33.589 2.688 34.741 4.192 ;
     RECT  31.715 6.528 34.741 6.56 ;
     RECT  34.741 1.728 34.789 4.192 ;
     RECT  34.789 1.728 34.835 4.32 ;
     RECT  34.741 0.192 35.563 0.224 ;
     RECT  34.741 5.76 35.701 6.56 ;
     RECT  35.701 5.76 35.755 6.88 ;
     RECT  35.989 9.728 36.075 9.76 ;
     RECT  35.755 5.76 36.515 6.816 ;
     RECT  34.835 2.688 36.803 4.32 ;
     RECT  36.803 2.688 38.133 2.72 ;
     RECT  38.133 1.408 38.187 2.72 ;
     RECT  36.515 5.76 38.197 6.56 ;
     RECT  38.517 10.304 38.579 10.336 ;
     RECT  38.187 1.408 38.709 1.76 ;
     RECT  36.803 4.288 38.819 4.32 ;
     RECT  38.709 0.192 39.733 1.76 ;
     RECT  39.733 0.192 41.269 2.336 ;
     RECT  41.269 0.192 41.323 4 ;
     RECT  41.323 0.192 41.451 3.488 ;
     RECT  41.451 1.408 41.459 3.488 ;
     RECT  38.197 5.76 41.525 6.816 ;
     RECT  41.525 5.76 41.557 8.032 ;
     RECT  41.557 4.928 41.579 8.032 ;
     RECT  42.037 9.728 42.091 9.76 ;
     RECT  41.459 1.408 42.227 1.44 ;
     RECT  41.459 3.456 42.275 3.488 ;
     RECT  41.579 4.928 43.189 5.792 ;
     RECT  41.579 8 43.189 8.032 ;
     RECT  43.189 8 43.243 8.608 ;
     RECT  43.189 4.544 44.341 5.792 ;
     RECT  43.243 8 44.341 8.032 ;
     RECT  44.341 4.544 44.395 8.032 ;
     RECT  44.149 10.816 44.395 10.848 ;
     RECT  44.395 4.544 44.459 5.792 ;
     RECT  44.395 8 44.483 8.032 ;
     RECT  44.389 2.752 44.725 2.784 ;
     RECT  44.725 0.192 44.779 0.224 ;
     RECT  44.725 2.304 44.779 2.784 ;
     RECT  45.109 3.456 45.163 3.488 ;
     RECT  45.109 1.088 46.117 1.12 ;
     RECT  46.117 1.088 46.187 2.976 ;
     RECT  46.187 1.088 46.211 1.76 ;
     RECT  44.459 5.056 46.309 5.792 ;
     RECT  46.309 4.928 46.693 5.792 ;
     RECT  46.693 4.544 46.709 5.792 ;
     RECT  46.709 3.392 46.763 5.792 ;
     RECT  46.763 3.392 46.787 3.424 ;
     RECT  46.763 4.928 47.411 5.792 ;
     RECT  46.211 1.728 47.557 1.76 ;
     RECT  47.557 1.728 48.117 2.208 ;
     RECT  47.411 5.056 48.117 5.792 ;
     RECT  48.117 1.664 48.181 2.208 ;
     RECT  48.181 1.664 48.235 3.488 ;
     RECT  48.235 1.664 48.563 2.208 ;
     RECT  48.117 5.056 48.755 6.304 ;
     RECT  48.755 5.632 48.757 6.304 ;
     RECT  48.757 5.632 48.811 6.368 ;
     RECT  48.949 0.192 49.003 0.224 ;
     RECT  48.563 1.728 49.283 2.208 ;
     RECT  49.283 1.984 49.667 2.208 ;
     RECT  48.811 6.336 50.677 6.368 ;
     RECT  50.677 5.376 50.731 7.456 ;
     RECT  50.731 5.376 50.771 6.368 ;
     RECT  49.667 1.984 51.253 2.016 ;
     RECT  50.771 5.696 51.307 6.368 ;
     RECT  51.253 8 51.307 8.608 ;
     RECT  51.253 1.344 51.491 2.336 ;
     RECT  51.253 3.84 51.491 3.872 ;
     RECT  51.307 6.208 51.563 6.368 ;
     RECT  51.307 8 51.563 8.032 ;
     RECT  51.491 1.344 51.781 1.376 ;
     RECT  51.781 1.024 51.883 1.376 ;
     RECT  51.829 2.88 51.923 2.912 ;
     RECT  51.883 1.344 51.971 1.376 ;
     RECT  51.563 6.336 53.493 6.368 ;
     RECT  53.493 6.336 53.555 7.456 ;
     RECT  53.493 3.776 53.987 3.808 ;
     RECT  54.085 3.968 54.837 4.384 ;
     RECT  53.555 6.336 54.837 6.368 ;
     RECT  54.837 3.968 54.891 6.368 ;
     RECT  54.891 3.968 54.947 5.664 ;
     RECT  54.947 3.968 55.235 4.64 ;
     RECT  55.093 2.432 55.285 2.464 ;
     RECT  55.285 1.984 55.339 2.464 ;
     RECT  54.613 9.024 56.435 9.056 ;
     RECT  55.339 1.984 57.445 2.016 ;
     RECT  55.235 4.608 57.461 4.64 ;
     RECT  57.461 3.456 57.493 4.64 ;
     RECT  57.445 1.088 57.515 2.016 ;
     RECT  57.493 3.456 57.539 5.728 ;
     RECT  57.539 3.776 57.579 5.728 ;
     RECT  57.579 3.776 57.683 5.088 ;
     RECT  57.515 1.984 58.933 2.016 ;
     RECT  58.933 0.192 58.987 0.224 ;
     RECT  57.683 5.056 59.315 5.088 ;
     RECT  58.933 1.984 60.213 2.336 ;
     RECT  59.509 4.032 60.267 4.064 ;
     RECT  60.213 1.984 60.467 2.72 ;
     RECT  60.467 1.984 61.187 2.336 ;
     RECT  61.621 0.192 61.675 0.224 ;
     RECT  61.187 2.304 61.675 2.336 ;
     RECT  62.453 2.688 62.629 2.848 ;
     RECT  60.757 4.928 62.629 4.96 ;
     RECT  62.581 6.848 62.635 6.88 ;
     RECT  62.629 2.688 62.699 4.96 ;
     RECT  62.645 1.088 62.771 1.12 ;
     RECT  62.699 4.928 62.771 4.96 ;
     RECT  62.699 2.688 63.019 2.912 ;
     RECT  62.965 10.816 63.019 10.848 ;
     RECT  62.965 7.936 63.221 7.968 ;
     RECT  63.205 10.304 63.275 10.336 ;
     RECT  63.221 7.936 63.299 8.48 ;
     RECT  63.299 8.448 63.827 8.48 ;
     RECT  62.965 0.192 64.555 0.224 ;
     RECT  63.109 1.728 64.693 2.336 ;
     RECT  64.309 4.032 64.693 4.064 ;
     RECT  64.069 8.768 64.693 8.8 ;
     RECT  64.693 1.728 64.747 4.576 ;
     RECT  64.693 8.768 64.747 9.12 ;
     RECT  64.693 10.816 64.747 10.848 ;
     RECT  64.747 1.728 65.397 1.76 ;
     RECT  65.397 1.088 65.459 1.76 ;
     RECT  64.747 3.456 65.459 4.384 ;
     RECT  64.747 8.768 66.325 8.8 ;
     RECT  66.325 8 66.411 8.8 ;
     RECT  65.459 4.352 66.467 4.384 ;
     RECT  66.613 0.192 66.667 0.224 ;
     RECT  65.459 1.728 66.755 1.76 ;
     RECT  66.357 5.952 66.755 5.984 ;
     RECT  67.189 6.848 67.243 7.456 ;
     RECT  66.517 4.416 67.317 4.448 ;
     RECT  67.317 4.416 67.379 5.088 ;
     RECT  67.243 7.424 67.379 7.456 ;
     RECT  67.189 2.24 67.637 2.272 ;
     RECT  67.637 2.24 67.691 2.912 ;
     RECT  67.691 2.816 67.813 2.912 ;
     RECT  67.379 4.416 67.813 4.448 ;
     RECT  67.813 2.816 67.859 4.448 ;
     RECT  67.859 2.816 69.349 4 ;
     RECT  69.349 2.304 69.419 4 ;
     RECT  69.365 0.768 69.493 0.8 ;
     RECT  69.419 2.88 69.493 4 ;
     RECT  68.773 6.272 69.547 6.304 ;
     RECT  69.493 0.768 69.587 1.12 ;
     RECT  69.587 0.96 69.731 0.992 ;
     RECT  69.493 2.88 70.309 4.576 ;
     RECT  70.309 2.88 70.379 5.152 ;
     RECT  70.379 2.88 70.709 4.064 ;
     RECT  70.709 2.816 70.883 4.064 ;
     RECT  66.411 8.768 71.029 8.8 ;
     RECT  71.029 10.816 71.083 10.848 ;
     RECT  71.029 8.512 71.123 8.8 ;
     RECT  70.883 2.816 72.565 3.616 ;
     RECT  72.565 2.816 72.619 4.576 ;
     RECT  72.619 2.816 72.661 4.064 ;
     RECT  72.661 2.304 72.693 4.064 ;
     RECT  72.693 1.088 72.757 4.064 ;
     RECT  72.757 0.192 72.947 4.064 ;
     RECT  72.947 0.192 73.579 3.616 ;
     RECT  71.123 8.768 73.859 8.8 ;
     RECT  73.579 1.088 74.099 3.616 ;
     RECT  72.853 6.784 74.195 6.816 ;
     RECT  74.099 2.304 74.549 3.616 ;
     RECT  74.549 2.304 74.581 3.808 ;
     RECT  74.533 10.816 74.603 10.848 ;
     RECT  74.581 2.304 74.667 4.576 ;
     RECT  74.667 2.304 74.723 3.808 ;
     RECT  74.723 2.496 74.771 3.808 ;
     RECT  74.771 2.816 75.155 3.808 ;
     RECT  76.213 1.024 76.725 1.056 ;
     RECT  74.677 6.208 76.837 6.24 ;
     RECT  76.725 1.024 76.853 1.12 ;
     RECT  75.155 2.816 76.853 3.36 ;
     RECT  76.837 6.208 76.981 6.88 ;
     RECT  76.981 6.208 77.035 7.456 ;
     RECT  77.035 6.208 77.219 6.24 ;
     RECT  76.853 1.024 77.365 3.36 ;
     RECT  77.365 0.192 78.083 3.36 ;
     RECT  78.083 2.24 78.565 3.36 ;
     RECT  78.565 2.24 78.635 4.576 ;
     RECT  78.083 0.192 78.827 0.8 ;
     RECT  77.797 7.872 79.141 7.904 ;
     RECT  79.141 5.056 79.211 5.088 ;
     RECT  79.141 7.872 79.211 9.184 ;
     RECT  78.635 2.24 79.283 3.36 ;
     RECT  79.211 7.872 79.331 7.904 ;
     RECT  79.333 6.592 79.717 6.624 ;
     RECT  78.827 0.768 80.293 0.8 ;
     RECT  79.283 2.24 80.293 3.296 ;
     RECT  80.293 0.768 80.309 3.296 ;
     RECT  80.309 0.192 80.483 3.296 ;
     RECT  80.483 1.088 80.869 3.296 ;
     RECT  80.869 1.088 80.939 4 ;
     RECT  80.629 10.816 80.939 10.848 ;
     RECT  80.939 1.088 81.131 3.296 ;
     RECT  81.131 2.24 81.683 3.296 ;
     RECT  79.717 6.016 81.685 6.624 ;
     RECT  81.685 5.12 81.771 6.624 ;
     RECT  81.683 2.24 82.115 2.848 ;
     RECT  81.771 6.016 82.883 6.624 ;
     RECT  82.883 6.016 83.637 6.048 ;
     RECT  83.605 7.424 83.691 7.456 ;
     RECT  83.637 5.056 83.699 6.048 ;
     RECT  82.115 2.24 83.749 2.272 ;
     RECT  83.749 2.24 83.819 3.488 ;
     RECT  83.819 2.304 84.085 3.488 ;
     RECT  84.085 2.304 84.139 4.064 ;
     RECT  83.699 6.016 84.213 6.048 ;
     RECT  84.181 8 84.267 8.032 ;
     RECT  84.213 6.016 84.275 6.368 ;
     RECT  84.277 9.152 84.331 9.184 ;
     RECT  84.275 6.016 84.515 6.24 ;
     RECT  84.515 6.208 84.659 6.24 ;
     RECT  84.853 0.192 84.907 0.224 ;
     RECT  84.139 2.304 84.907 2.848 ;
     RECT  85.429 2.88 85.483 2.912 ;
     RECT  85.429 0.768 85.619 0.8 ;
     RECT  85.813 5.056 85.867 5.088 ;
     RECT  85.813 7.424 85.867 7.456 ;
     RECT  86.533 2.496 87.733 2.528 ;
     RECT  87.733 0.192 87.787 0.224 ;
     RECT  87.733 1.728 87.875 2.528 ;
     RECT  87.875 2.496 88.309 2.528 ;
     RECT  88.309 2.496 88.363 2.912 ;
     RECT  88.309 1.088 88.403 1.12 ;
     RECT  88.363 2.496 89.173 2.528 ;
     RECT  89.173 2.432 89.461 2.528 ;
     RECT  89.461 1.344 89.781 2.528 ;
     RECT  89.781 1.344 89.843 2.912 ;
     RECT  89.843 1.344 90.131 2.464 ;
     RECT  86.005 4.544 90.517 4.576 ;
     RECT  90.517 4.032 90.603 4.576 ;
     RECT  90.131 2.112 90.611 2.464 ;
     RECT  90.611 2.432 91.765 2.464 ;
     RECT  88.693 6.784 91.811 6.816 ;
     RECT  91.765 1.088 91.859 1.12 ;
     RECT  91.765 2.432 91.893 2.912 ;
     RECT  91.893 1.664 91.909 2.912 ;
     RECT  91.909 1.664 91.955 2.976 ;
     RECT  91.955 2.304 92.139 2.976 ;
     RECT  92.085 0.192 92.395 0.224 ;
     RECT  92.139 2.304 92.483 2.464 ;
     RECT  90.709 5.12 92.483 5.152 ;
     RECT  93.589 9.152 93.675 9.184 ;
     RECT  93.621 6.208 94.115 6.24 ;
     RECT  92.483 2.432 94.261 2.464 ;
     RECT  94.261 0.192 94.549 0.224 ;
     RECT  94.261 2.304 94.549 2.464 ;
     RECT  94.549 0.192 94.581 2.464 ;
     RECT  94.581 0.192 94.635 3.488 ;
     RECT  94.635 1.664 94.691 3.488 ;
     RECT  94.549 6.592 96.131 6.624 ;
     RECT  94.691 1.664 96.229 2.784 ;
     RECT  94.635 0.192 96.245 0.224 ;
     RECT  96.229 1.664 96.245 2.912 ;
     RECT  96.245 0.192 96.299 2.912 ;
     RECT  96.299 0.192 96.419 2.784 ;
     RECT  96.419 0.192 96.619 0.224 ;
     RECT  96.419 2.304 96.947 2.784 ;
     RECT  96.947 2.752 97.973 2.784 ;
     RECT  96.133 6.528 98.005 6.56 ;
     RECT  97.973 1.088 98.533 1.12 ;
     RECT  98.005 5.952 99.203 6.56 ;
     RECT  97.973 2.752 99.253 2.912 ;
     RECT  98.533 1.024 99.509 1.12 ;
     RECT  99.253 2.752 99.509 4.064 ;
     RECT  99.509 1.024 99.541 4.064 ;
     RECT  99.541 1.024 99.627 5.152 ;
     RECT  99.627 1.024 99.683 4.576 ;
     RECT  99.683 1.024 99.701 2.976 ;
     RECT  99.701 0.96 99.755 2.976 ;
     RECT  99.755 0.96 99.779 2.336 ;
     RECT  99.637 10.816 100.843 10.848 ;
     RECT  99.683 4.544 100.931 4.576 ;
     RECT  99.829 0.192 101.227 0.224 ;
     RECT  99.779 2.304 101.227 2.336 ;
     RECT  101.685 1.088 101.747 1.12 ;
     RECT  101.685 3.456 101.747 3.488 ;
     RECT  99.203 6.528 101.795 6.56 ;
     RECT  103.605 9.728 103.667 9.76 ;
     RECT  103.605 2.24 103.955 2.272 ;
    LAYER M7 ;
     RECT  30.528 0.181 31.136 0.501 ;
     RECT  33.024 0.181 33.056 0.501 ;
     RECT  9.344 0.181 9.376 0.757 ;
     RECT  77.376 0.181 78.816 0.757 ;
     RECT  80.32 0.181 80.352 0.757 ;
     RECT  84.864 0.181 84.896 0.757 ;
     RECT  69.376 0.757 69.408 0.949 ;
     RECT  99.84 0.181 101.216 0.949 ;
     RECT  34.752 0.181 35.552 1.013 ;
     RECT  77.376 0.757 80.352 1.013 ;
     RECT  99.712 0.949 101.216 1.013 ;
     RECT  4.992 0.181 5.024 1.077 ;
     RECT  17.216 0.181 17.248 1.077 ;
     RECT  29.184 0.181 29.216 1.077 ;
     RECT  30.528 0.501 33.056 1.077 ;
     RECT  34.624 1.013 35.552 1.077 ;
     RECT  44.736 0.181 44.768 1.077 ;
     RECT  61.632 0.181 61.664 1.077 ;
     RECT  62.976 0.181 64.544 1.077 ;
     RECT  66.624 0.181 66.656 1.077 ;
     RECT  72.768 0.181 73.568 1.077 ;
     RECT  76.224 1.013 80.352 1.077 ;
     RECT  87.744 0.181 87.776 1.077 ;
     RECT  92.096 0.181 92.384 1.077 ;
     RECT  94.272 0.181 95.2 1.077 ;
     RECT  96.576 0.181 96.608 1.077 ;
     RECT  98.56 1.013 101.216 1.077 ;
     RECT  3.392 1.077 3.424 1.333 ;
     RECT  4.864 1.077 5.024 1.333 ;
     RECT  51.84 1.013 51.872 1.333 ;
     RECT  87.744 1.077 88.352 1.333 ;
     RECT  38.72 0.181 41.44 1.397 ;
     RECT  18.624 1.461 18.784 1.643 ;
     RECT  48.96 0.181 48.992 1.653 ;
     RECT  87.744 1.333 89.504 1.653 ;
     RECT  9.344 0.757 10.784 1.771 ;
     RECT  26.304 0.181 26.336 1.771 ;
     RECT  38.144 1.397 41.44 1.771 ;
     RECT  48.128 1.653 48.992 1.771 ;
     RECT  61.632 1.077 66.656 1.771 ;
     RECT  87.744 1.653 89.824 1.771 ;
     RECT  88.32 1.771 89.824 2.101 ;
     RECT  91.776 1.077 92.384 2.101 ;
     RECT  58.944 0.181 58.976 2.229 ;
     RECT  84.864 0.757 85.472 2.229 ;
     RECT  3.392 1.333 5.024 2.347 ;
     RECT  7.36 0.181 7.392 2.347 ;
     RECT  16.512 1.077 17.248 2.347 ;
     RECT  29.184 1.077 35.552 2.347 ;
     RECT  39.744 1.771 41.44 2.347 ;
     RECT  51.264 1.333 51.872 2.347 ;
     RECT  58.944 2.229 59.744 2.347 ;
     RECT  61.632 1.771 65.44 2.347 ;
     RECT  72.704 1.077 73.568 2.347 ;
     RECT  76.224 1.077 81.12 2.347 ;
     RECT  83.776 2.229 85.472 2.347 ;
     RECT  88.32 2.101 92.384 2.347 ;
     RECT  94.272 1.077 96.608 2.347 ;
     RECT  97.984 1.077 101.728 2.347 ;
     RECT  55.296 1.973 55.328 2.475 ;
     RECT  76.224 2.347 79.2 2.475 ;
     RECT  3.392 2.347 4.896 2.677 ;
     RECT  59.712 2.347 59.744 2.677 ;
     RECT  38.144 1.771 38.176 2.731 ;
     RECT  44.736 1.077 46.176 2.741 ;
     RECT  21.12 2.229 21.152 2.795 ;
     RECT  94.592 2.347 96.288 2.795 ;
     RECT  2.176 2.677 4.896 2.805 ;
     RECT  9.344 1.771 9.696 2.805 ;
     RECT  14.72 2.101 14.752 2.805 ;
     RECT  16.512 2.347 16.544 2.805 ;
     RECT  67.2 2.229 67.68 2.805 ;
     RECT  69.376 0.949 69.664 2.805 ;
     RECT  72.704 2.347 72.928 2.805 ;
     RECT  76.224 2.475 76.896 2.805 ;
     RECT  80.896 2.347 81.12 2.805 ;
     RECT  62.464 2.347 63.008 2.859 ;
     RECT  1.472 2.805 4.896 2.923 ;
     RECT  8.512 2.805 9.696 2.923 ;
     RECT  29.568 2.347 35.552 2.923 ;
     RECT  51.84 2.347 51.872 2.923 ;
     RECT  62.592 2.859 63.008 2.923 ;
     RECT  67.2 2.805 70.752 2.923 ;
     RECT  78.464 2.475 79.2 2.923 ;
     RECT  85.44 2.347 85.472 2.923 ;
     RECT  88.32 2.347 88.352 2.923 ;
     RECT  89.792 2.347 92.128 2.923 ;
     RECT  96.256 2.795 96.288 2.923 ;
     RECT  97.984 2.347 99.744 2.923 ;
     RECT  44.416 2.741 46.176 2.987 ;
     RECT  92.096 2.923 92.128 2.987 ;
     RECT  99.264 2.923 99.744 2.987 ;
     RECT  68.8 2.923 70.752 3.051 ;
     RECT  14.656 2.805 16.544 3.115 ;
     RECT  33.792 2.923 35.552 3.253 ;
     RECT  75.776 2.805 76.896 3.253 ;
     RECT  74.624 3.253 76.896 3.371 ;
     RECT  33.792 3.253 35.744 3.381 ;
     RECT  3.648 2.923 4.896 3.499 ;
     RECT  33.792 3.381 36.448 3.499 ;
     RECT  44.416 2.987 45.152 3.499 ;
     RECT  48.128 1.771 48.224 3.499 ;
     RECT  57.472 1.077 57.504 3.499 ;
     RECT  64.32 2.347 65.44 3.499 ;
     RECT  83.776 2.347 84.128 3.499 ;
     RECT  94.592 2.795 94.624 3.499 ;
     RECT  101.696 2.347 101.728 3.499 ;
     RECT  74.624 3.371 74.656 3.765 ;
     RECT  26.752 3.381 26.784 3.957 ;
     RECT  59.712 2.677 60.256 4.075 ;
     RECT  62.592 2.923 62.688 4.075 ;
     RECT  64.32 3.499 64.736 4.075 ;
     RECT  70.336 3.051 70.752 4.075 ;
     RECT  72.576 2.805 72.928 4.075 ;
     RECT  84.096 3.499 84.128 4.075 ;
     RECT  90.56 2.923 90.592 4.075 ;
     RECT  99.264 2.987 99.616 4.075 ;
     RECT  33.792 3.499 33.824 4.203 ;
     RECT  8.512 2.923 9.632 4.533 ;
     RECT  44.416 3.499 44.448 4.533 ;
     RECT  68.8 3.051 68.832 4.533 ;
     RECT  70.336 4.075 70.368 4.533 ;
     RECT  99.584 4.075 99.616 4.533 ;
     RECT  1.472 2.923 2.208 4.587 ;
     RECT  14.656 3.115 15.904 4.587 ;
     RECT  26.624 3.957 26.784 4.587 ;
     RECT  43.2 4.533 44.448 4.587 ;
     RECT  46.72 3.381 46.752 4.587 ;
     RECT  64.704 4.075 64.736 4.587 ;
     RECT  72.576 4.075 72.608 4.587 ;
     RECT  74.56 3.765 74.656 4.587 ;
     RECT  78.592 2.923 78.624 4.587 ;
     RECT  14.656 4.587 14.816 4.651 ;
     RECT  55.168 3.957 55.2 4.651 ;
     RECT  23.424 3.957 23.456 4.789 ;
     RECT  2.176 4.587 2.208 5.045 ;
     RECT  3.648 3.499 3.68 5.045 ;
     RECT  67.2 2.923 67.232 5.045 ;
     RECT  14.784 4.651 14.816 5.163 ;
     RECT  32.384 2.923 32.416 5.163 ;
     RECT  68.8 4.533 70.368 5.163 ;
     RECT  80.896 2.805 81.76 5.163 ;
     RECT  99.584 4.533 100.832 5.163 ;
     RECT  51.264 3.829 51.296 5.365 ;
     RECT  29.568 2.923 30.752 5.419 ;
     RECT  8.512 4.533 10.912 5.621 ;
     RECT  41.28 2.347 41.312 5.621 ;
     RECT  43.2 4.587 43.232 5.621 ;
     RECT  48.128 3.499 48.16 5.621 ;
     RECT  2.176 5.045 3.68 5.739 ;
     RECT  30.72 5.419 30.752 5.739 ;
     RECT  57.536 3.765 57.568 5.739 ;
     RECT  22.208 4.789 23.456 5.803 ;
     RECT  67.2 5.045 67.36 5.941 ;
     RECT  12.928 4.533 12.96 6.197 ;
     RECT  18.752 1.643 18.784 6.197 ;
     RECT  50.688 5.365 51.296 6.197 ;
     RECT  76.864 3.371 76.896 6.197 ;
     RECT  83.648 5.045 83.68 6.197 ;
     RECT  6.208 3.253 6.24 6.315 ;
     RECT  18.752 6.197 19.936 6.315 ;
     RECT  35.712 3.499 36.448 6.315 ;
     RECT  48.128 5.621 48.8 6.315 ;
     RECT  68.8 5.163 69.536 6.315 ;
     RECT  48.768 6.315 48.8 6.379 ;
     RECT  54.848 5.621 54.88 6.379 ;
     RECT  24.768 3.765 24.8 6.571 ;
     RECT  23.296 5.803 23.456 6.763 ;
     RECT  8.384 5.621 10.912 6.773 ;
     RECT  26.624 4.587 26.656 6.773 ;
     RECT  38.208 6.517 38.24 6.773 ;
     RECT  41.28 5.621 43.232 6.773 ;
     RECT  26.624 6.773 27.616 6.827 ;
     RECT  38.208 6.773 38.56 6.827 ;
     RECT  41.28 6.773 44.384 6.827 ;
     RECT  7.616 6.773 10.912 6.891 ;
     RECT  35.712 6.315 36.064 6.891 ;
     RECT  62.592 4.075 62.624 6.891 ;
     RECT  76.864 6.197 77.024 6.891 ;
     RECT  2.176 5.739 3.232 7.467 ;
     RECT  9.536 6.891 10.912 7.467 ;
     RECT  15.872 5.941 15.904 7.467 ;
     RECT  19.904 6.315 19.936 7.467 ;
     RECT  50.688 6.197 51.552 7.467 ;
     RECT  53.504 3.765 53.536 7.467 ;
     RECT  66.368 5.941 67.36 7.467 ;
     RECT  76.992 6.891 77.024 7.467 ;
     RECT  83.648 6.197 84.32 7.467 ;
     RECT  85.824 5.045 85.856 7.467 ;
     RECT  4.864 6.773 4.896 8.043 ;
     RECT  7.616 6.891 7.648 8.043 ;
     RECT  23.296 6.763 23.328 8.043 ;
     RECT  41.536 6.827 44.384 8.043 ;
     RECT  51.264 7.467 51.552 8.043 ;
     RECT  66.368 7.467 66.4 8.043 ;
     RECT  84.224 7.467 84.32 8.043 ;
     RECT  25.152 7.349 25.184 8.171 ;
     RECT  9.536 7.467 9.568 8.235 ;
     RECT  12.928 6.197 14.176 8.427 ;
     RECT  62.976 7.925 63.008 8.437 ;
     RECT  17.28 6.709 17.312 8.491 ;
     RECT  26.752 6.827 27.616 8.619 ;
     RECT  42.048 8.043 44.384 8.619 ;
     RECT  51.264 8.043 51.296 8.619 ;
     RECT  79.168 5.045 79.2 9.195 ;
     RECT  84.288 8.043 84.32 9.195 ;
     RECT  93.632 6.197 93.664 9.195 ;
     RECT  10.944 7.861 10.976 9.771 ;
     RECT  36.032 6.891 36.064 9.771 ;
     RECT  42.048 8.619 42.08 9.771 ;
     RECT  103.616 2.229 103.648 9.771 ;
     RECT  38.528 6.827 38.56 10.347 ;
     RECT  62.976 8.437 63.264 10.347 ;
     RECT  12.928 8.427 12.96 10.859 ;
     RECT  26.752 8.619 26.784 10.859 ;
     RECT  44.352 8.619 44.384 10.859 ;
     RECT  62.976 10.347 63.008 10.859 ;
     RECT  64.704 9.077 64.736 10.859 ;
     RECT  71.04 8.501 71.072 10.859 ;
     RECT  74.56 4.587 74.592 10.859 ;
     RECT  80.896 5.163 80.928 10.859 ;
     RECT  99.648 5.163 100.832 10.859 ;
  END
END ot_attn_bank_sn544
END LIBRARY
